# CURRENT-RTL SIGNAL/PG GEOMETRY PROTOTYPE ONLY. NOT A SIGNED VIEW.
# Fresh846-port contract; PG is the unchanged kit pdn.tcl grid, not routed evidence.
VERSION 5.8 ;
BUSBITCHARS "[]" ;
DIVIDERCHAR "/" ;
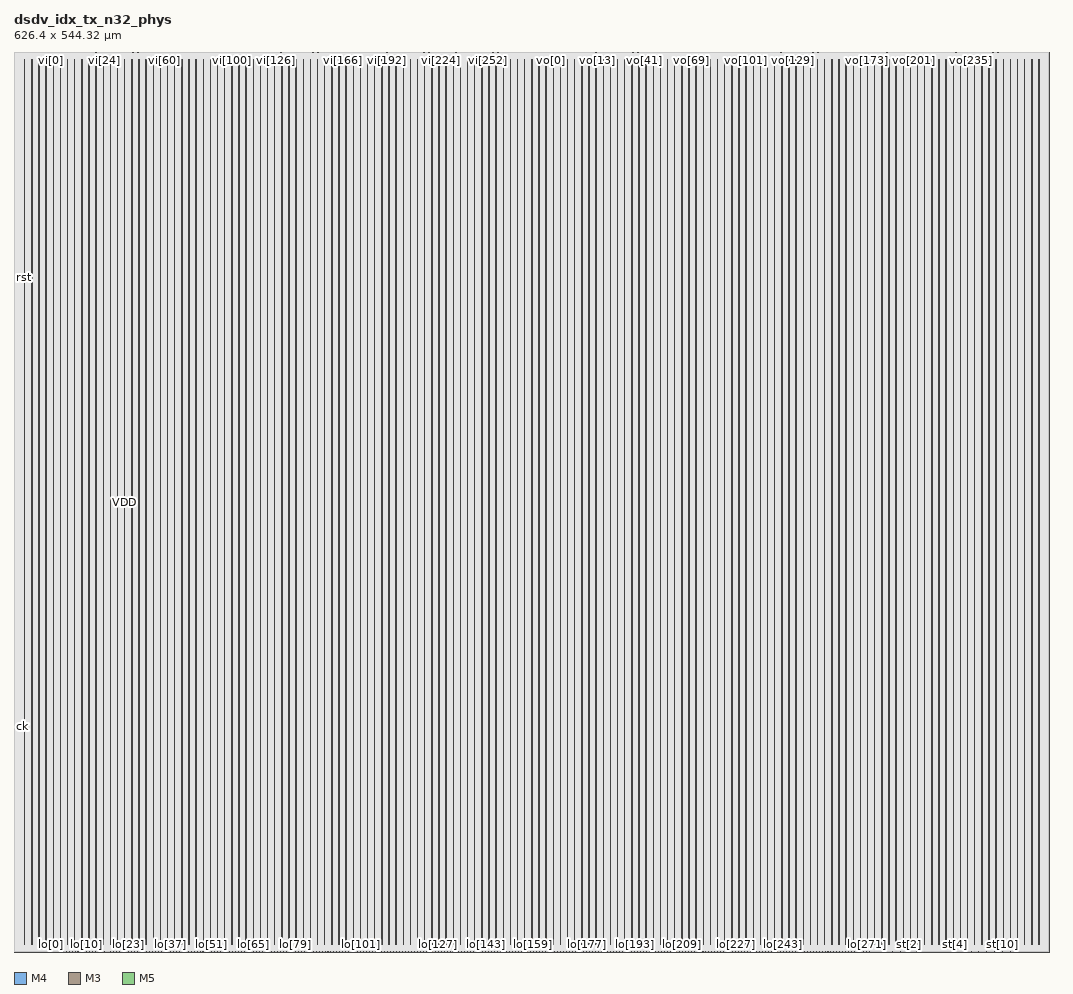
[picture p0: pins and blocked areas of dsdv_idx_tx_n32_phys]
MACRO dsdv_idx_tx_n32_phys
 CLASS BLOCK ;
 ORIGIN 0 0 ;
 SIZE 626.4 BY 544.32 ;
 SYMMETRY X Y ;
 PIN ck
  DIRECTION INPUT ;
  USE SIGNAL ;
  PORT
   LAYER M4 ;
   RECT 0.000000 136.560000 0.084000 136.584000 ;
  END
 END ck
 PIN lo[0]
  DIRECTION OUTPUT ;
  USE SIGNAL ;
  PORT
   LAYER M3 ;
   RECT 22.500000 0.000000 22.518000 0.038000 ;
  END
 END lo[0]
 PIN lo[97]
  DIRECTION OUTPUT ;
  USE SIGNAL ;
  PORT
   LAYER M3 ;
   RECT 202.500000 0.000000 202.518000 0.038000 ;
  END
 END lo[97]
 PIN lo[98]
  DIRECTION OUTPUT ;
  USE SIGNAL ;
  PORT
   LAYER M5 ;
   RECT 204.288000 0.000000 204.312000 0.084000 ;
  END
 END lo[98]
 PIN lo[99]
  DIRECTION OUTPUT ;
  USE SIGNAL ;
  PORT
   LAYER M3 ;
   RECT 206.100000 0.000000 206.118000 0.038000 ;
  END
 END lo[99]
 PIN lo[100]
  DIRECTION OUTPUT ;
  USE SIGNAL ;
  PORT
   LAYER M5 ;
   RECT 207.888000 0.000000 207.912000 0.084000 ;
  END
 END lo[100]
 PIN lo[101]
  DIRECTION OUTPUT ;
  USE SIGNAL ;
  PORT
   LAYER M3 ;
   RECT 209.700000 0.000000 209.718000 0.038000 ;
  END
 END lo[101]
 PIN lo[102]
  DIRECTION OUTPUT ;
  USE SIGNAL ;
  PORT
   LAYER M5 ;
   RECT 211.488000 0.000000 211.512000 0.084000 ;
  END
 END lo[102]
 PIN lo[103]
  DIRECTION OUTPUT ;
  USE SIGNAL ;
  PORT
   LAYER M3 ;
   RECT 213.300000 0.000000 213.318000 0.038000 ;
  END
 END lo[103]
 PIN lo[104]
  DIRECTION OUTPUT ;
  USE SIGNAL ;
  PORT
   LAYER M5 ;
   RECT 215.088000 0.000000 215.112000 0.084000 ;
  END
 END lo[104]
 PIN lo[105]
  DIRECTION OUTPUT ;
  USE SIGNAL ;
  PORT
   LAYER M3 ;
   RECT 216.900000 0.000000 216.918000 0.038000 ;
  END
 END lo[105]
 PIN lo[106]
  DIRECTION OUTPUT ;
  USE SIGNAL ;
  PORT
   LAYER M5 ;
   RECT 218.688000 0.000000 218.712000 0.084000 ;
  END
 END lo[106]
 PIN lo[8]
  DIRECTION OUTPUT ;
  USE SIGNAL ;
  PORT
   LAYER M3 ;
   RECT 40.500000 0.000000 40.518000 0.038000 ;
  END
 END lo[8]
 PIN lo[107]
  DIRECTION OUTPUT ;
  USE SIGNAL ;
  PORT
   LAYER M3 ;
   RECT 220.500000 0.000000 220.518000 0.038000 ;
  END
 END lo[107]
 PIN lo[108]
  DIRECTION OUTPUT ;
  USE SIGNAL ;
  PORT
   LAYER M5 ;
   RECT 222.288000 0.000000 222.312000 0.084000 ;
  END
 END lo[108]
 PIN lo[109]
  DIRECTION OUTPUT ;
  USE SIGNAL ;
  PORT
   LAYER M3 ;
   RECT 224.100000 0.000000 224.118000 0.038000 ;
  END
 END lo[109]
 PIN lo[110]
  DIRECTION OUTPUT ;
  USE SIGNAL ;
  PORT
   LAYER M5 ;
   RECT 225.888000 0.000000 225.912000 0.084000 ;
  END
 END lo[110]
 PIN lo[111]
  DIRECTION OUTPUT ;
  USE SIGNAL ;
  PORT
   LAYER M3 ;
   RECT 227.700000 0.000000 227.718000 0.038000 ;
  END
 END lo[111]
 PIN lo[112]
  DIRECTION OUTPUT ;
  USE SIGNAL ;
  PORT
   LAYER M5 ;
   RECT 229.488000 0.000000 229.512000 0.084000 ;
  END
 END lo[112]
 PIN lo[113]
  DIRECTION OUTPUT ;
  USE SIGNAL ;
  PORT
   LAYER M3 ;
   RECT 231.300000 0.000000 231.318000 0.038000 ;
  END
 END lo[113]
 PIN lo[114]
  DIRECTION OUTPUT ;
  USE SIGNAL ;
  PORT
   LAYER M5 ;
   RECT 233.088000 0.000000 233.112000 0.084000 ;
  END
 END lo[114]
 PIN lo[115]
  DIRECTION OUTPUT ;
  USE SIGNAL ;
  PORT
   LAYER M3 ;
   RECT 234.900000 0.000000 234.918000 0.038000 ;
  END
 END lo[115]
 PIN lo[116]
  DIRECTION OUTPUT ;
  USE SIGNAL ;
  PORT
   LAYER M5 ;
   RECT 236.688000 0.000000 236.712000 0.084000 ;
  END
 END lo[116]
 PIN lo[9]
  DIRECTION OUTPUT ;
  USE SIGNAL ;
  PORT
   LAYER M5 ;
   RECT 42.288000 0.000000 42.312000 0.084000 ;
  END
 END lo[9]
 PIN lo[117]
  DIRECTION OUTPUT ;
  USE SIGNAL ;
  PORT
   LAYER M3 ;
   RECT 238.500000 0.000000 238.518000 0.038000 ;
  END
 END lo[117]
 PIN lo[118]
  DIRECTION OUTPUT ;
  USE SIGNAL ;
  PORT
   LAYER M5 ;
   RECT 240.288000 0.000000 240.312000 0.084000 ;
  END
 END lo[118]
 PIN lo[119]
  DIRECTION OUTPUT ;
  USE SIGNAL ;
  PORT
   LAYER M3 ;
   RECT 242.100000 0.000000 242.118000 0.038000 ;
  END
 END lo[119]
 PIN lo[120]
  DIRECTION OUTPUT ;
  USE SIGNAL ;
  PORT
   LAYER M5 ;
   RECT 243.888000 0.000000 243.912000 0.084000 ;
  END
 END lo[120]
 PIN lo[121]
  DIRECTION OUTPUT ;
  USE SIGNAL ;
  PORT
   LAYER M3 ;
   RECT 245.700000 0.000000 245.718000 0.038000 ;
  END
 END lo[121]
 PIN lo[122]
  DIRECTION OUTPUT ;
  USE SIGNAL ;
  PORT
   LAYER M5 ;
   RECT 247.488000 0.000000 247.512000 0.084000 ;
  END
 END lo[122]
 PIN lo[123]
  DIRECTION OUTPUT ;
  USE SIGNAL ;
  PORT
   LAYER M3 ;
   RECT 249.300000 0.000000 249.318000 0.038000 ;
  END
 END lo[123]
 PIN lo[124]
  DIRECTION OUTPUT ;
  USE SIGNAL ;
  PORT
   LAYER M5 ;
   RECT 251.088000 0.000000 251.112000 0.084000 ;
  END
 END lo[124]
 PIN lo[125]
  DIRECTION OUTPUT ;
  USE SIGNAL ;
  PORT
   LAYER M3 ;
   RECT 252.900000 0.000000 252.918000 0.038000 ;
  END
 END lo[125]
 PIN lo[126]
  DIRECTION OUTPUT ;
  USE SIGNAL ;
  PORT
   LAYER M5 ;
   RECT 254.688000 0.000000 254.712000 0.084000 ;
  END
 END lo[126]
 PIN lo[10]
  DIRECTION OUTPUT ;
  USE SIGNAL ;
  PORT
   LAYER M3 ;
   RECT 44.100000 0.000000 44.118000 0.038000 ;
  END
 END lo[10]
 PIN lo[127]
  DIRECTION OUTPUT ;
  USE SIGNAL ;
  PORT
   LAYER M3 ;
   RECT 256.500000 0.000000 256.518000 0.038000 ;
  END
 END lo[127]
 PIN lo[128]
  DIRECTION OUTPUT ;
  USE SIGNAL ;
  PORT
   LAYER M5 ;
   RECT 258.288000 0.000000 258.312000 0.084000 ;
  END
 END lo[128]
 PIN lo[129]
  DIRECTION OUTPUT ;
  USE SIGNAL ;
  PORT
   LAYER M3 ;
   RECT 260.100000 0.000000 260.118000 0.038000 ;
  END
 END lo[129]
 PIN lo[130]
  DIRECTION OUTPUT ;
  USE SIGNAL ;
  PORT
   LAYER M5 ;
   RECT 261.888000 0.000000 261.912000 0.084000 ;
  END
 END lo[130]
 PIN lo[131]
  DIRECTION OUTPUT ;
  USE SIGNAL ;
  PORT
   LAYER M3 ;
   RECT 263.700000 0.000000 263.718000 0.038000 ;
  END
 END lo[131]
 PIN lo[132]
  DIRECTION OUTPUT ;
  USE SIGNAL ;
  PORT
   LAYER M5 ;
   RECT 265.488000 0.000000 265.512000 0.084000 ;
  END
 END lo[132]
 PIN lo[133]
  DIRECTION OUTPUT ;
  USE SIGNAL ;
  PORT
   LAYER M3 ;
   RECT 267.300000 0.000000 267.318000 0.038000 ;
  END
 END lo[133]
 PIN lo[134]
  DIRECTION OUTPUT ;
  USE SIGNAL ;
  PORT
   LAYER M5 ;
   RECT 269.088000 0.000000 269.112000 0.084000 ;
  END
 END lo[134]
 PIN lo[135]
  DIRECTION OUTPUT ;
  USE SIGNAL ;
  PORT
   LAYER M3 ;
   RECT 270.900000 0.000000 270.918000 0.038000 ;
  END
 END lo[135]
 PIN lo[136]
  DIRECTION OUTPUT ;
  USE SIGNAL ;
  PORT
   LAYER M5 ;
   RECT 272.688000 0.000000 272.712000 0.084000 ;
  END
 END lo[136]
 PIN lo[11]
  DIRECTION OUTPUT ;
  USE SIGNAL ;
  PORT
   LAYER M5 ;
   RECT 45.888000 0.000000 45.912000 0.084000 ;
  END
 END lo[11]
 PIN lo[137]
  DIRECTION OUTPUT ;
  USE SIGNAL ;
  PORT
   LAYER M3 ;
   RECT 274.500000 0.000000 274.518000 0.038000 ;
  END
 END lo[137]
 PIN lo[138]
  DIRECTION OUTPUT ;
  USE SIGNAL ;
  PORT
   LAYER M5 ;
   RECT 276.288000 0.000000 276.312000 0.084000 ;
  END
 END lo[138]
 PIN lo[139]
  DIRECTION OUTPUT ;
  USE SIGNAL ;
  PORT
   LAYER M3 ;
   RECT 278.100000 0.000000 278.118000 0.038000 ;
  END
 END lo[139]
 PIN lo[140]
  DIRECTION OUTPUT ;
  USE SIGNAL ;
  PORT
   LAYER M5 ;
   RECT 279.888000 0.000000 279.912000 0.084000 ;
  END
 END lo[140]
 PIN lo[141]
  DIRECTION OUTPUT ;
  USE SIGNAL ;
  PORT
   LAYER M3 ;
   RECT 281.700000 0.000000 281.718000 0.038000 ;
  END
 END lo[141]
 PIN lo[142]
  DIRECTION OUTPUT ;
  USE SIGNAL ;
  PORT
   LAYER M5 ;
   RECT 283.488000 0.000000 283.512000 0.084000 ;
  END
 END lo[142]
 PIN lo[143]
  DIRECTION OUTPUT ;
  USE SIGNAL ;
  PORT
   LAYER M3 ;
   RECT 285.300000 0.000000 285.318000 0.038000 ;
  END
 END lo[143]
 PIN lo[144]
  DIRECTION OUTPUT ;
  USE SIGNAL ;
  PORT
   LAYER M5 ;
   RECT 287.088000 0.000000 287.112000 0.084000 ;
  END
 END lo[144]
 PIN lo[145]
  DIRECTION OUTPUT ;
  USE SIGNAL ;
  PORT
   LAYER M3 ;
   RECT 288.900000 0.000000 288.918000 0.038000 ;
  END
 END lo[145]
 PIN lo[146]
  DIRECTION OUTPUT ;
  USE SIGNAL ;
  PORT
   LAYER M5 ;
   RECT 290.688000 0.000000 290.712000 0.084000 ;
  END
 END lo[146]
 PIN lo[12]
  DIRECTION OUTPUT ;
  USE SIGNAL ;
  PORT
   LAYER M3 ;
   RECT 47.700000 0.000000 47.718000 0.038000 ;
  END
 END lo[12]
 PIN lo[147]
  DIRECTION OUTPUT ;
  USE SIGNAL ;
  PORT
   LAYER M3 ;
   RECT 292.500000 0.000000 292.518000 0.038000 ;
  END
 END lo[147]
 PIN lo[148]
  DIRECTION OUTPUT ;
  USE SIGNAL ;
  PORT
   LAYER M5 ;
   RECT 294.288000 0.000000 294.312000 0.084000 ;
  END
 END lo[148]
 PIN lo[149]
  DIRECTION OUTPUT ;
  USE SIGNAL ;
  PORT
   LAYER M3 ;
   RECT 296.100000 0.000000 296.118000 0.038000 ;
  END
 END lo[149]
 PIN lo[150]
  DIRECTION OUTPUT ;
  USE SIGNAL ;
  PORT
   LAYER M5 ;
   RECT 297.888000 0.000000 297.912000 0.084000 ;
  END
 END lo[150]
 PIN lo[151]
  DIRECTION OUTPUT ;
  USE SIGNAL ;
  PORT
   LAYER M3 ;
   RECT 299.736000 0.000000 299.754000 0.038000 ;
  END
 END lo[151]
 PIN lo[152]
  DIRECTION OUTPUT ;
  USE SIGNAL ;
  PORT
   LAYER M5 ;
   RECT 301.488000 0.000000 301.512000 0.084000 ;
  END
 END lo[152]
 PIN lo[153]
  DIRECTION OUTPUT ;
  USE SIGNAL ;
  PORT
   LAYER M3 ;
   RECT 303.300000 0.000000 303.318000 0.038000 ;
  END
 END lo[153]
 PIN lo[154]
  DIRECTION OUTPUT ;
  USE SIGNAL ;
  PORT
   LAYER M5 ;
   RECT 305.088000 0.000000 305.112000 0.084000 ;
  END
 END lo[154]
 PIN lo[155]
  DIRECTION OUTPUT ;
  USE SIGNAL ;
  PORT
   LAYER M3 ;
   RECT 306.900000 0.000000 306.918000 0.038000 ;
  END
 END lo[155]
 PIN lo[156]
  DIRECTION OUTPUT ;
  USE SIGNAL ;
  PORT
   LAYER M5 ;
   RECT 308.688000 0.000000 308.712000 0.084000 ;
  END
 END lo[156]
 PIN lo[13]
  DIRECTION OUTPUT ;
  USE SIGNAL ;
  PORT
   LAYER M5 ;
   RECT 49.488000 0.000000 49.512000 0.084000 ;
  END
 END lo[13]
 PIN lo[157]
  DIRECTION OUTPUT ;
  USE SIGNAL ;
  PORT
   LAYER M3 ;
   RECT 310.500000 0.000000 310.518000 0.038000 ;
  END
 END lo[157]
 PIN lo[158]
  DIRECTION OUTPUT ;
  USE SIGNAL ;
  PORT
   LAYER M5 ;
   RECT 312.288000 0.000000 312.312000 0.084000 ;
  END
 END lo[158]
 PIN lo[159]
  DIRECTION OUTPUT ;
  USE SIGNAL ;
  PORT
   LAYER M3 ;
   RECT 314.100000 0.000000 314.118000 0.038000 ;
  END
 END lo[159]
 PIN lo[160]
  DIRECTION OUTPUT ;
  USE SIGNAL ;
  PORT
   LAYER M5 ;
   RECT 315.888000 0.000000 315.912000 0.084000 ;
  END
 END lo[160]
 PIN lo[161]
  DIRECTION OUTPUT ;
  USE SIGNAL ;
  PORT
   LAYER M3 ;
   RECT 317.700000 0.000000 317.718000 0.038000 ;
  END
 END lo[161]
 PIN lo[162]
  DIRECTION OUTPUT ;
  USE SIGNAL ;
  PORT
   LAYER M5 ;
   RECT 319.488000 0.000000 319.512000 0.084000 ;
  END
 END lo[162]
 PIN lo[163]
  DIRECTION OUTPUT ;
  USE SIGNAL ;
  PORT
   LAYER M3 ;
   RECT 321.300000 0.000000 321.318000 0.038000 ;
  END
 END lo[163]
 PIN lo[164]
  DIRECTION OUTPUT ;
  USE SIGNAL ;
  PORT
   LAYER M5 ;
   RECT 323.088000 0.000000 323.112000 0.084000 ;
  END
 END lo[164]
 PIN lo[165]
  DIRECTION OUTPUT ;
  USE SIGNAL ;
  PORT
   LAYER M3 ;
   RECT 324.900000 0.000000 324.918000 0.038000 ;
  END
 END lo[165]
 PIN lo[166]
  DIRECTION OUTPUT ;
  USE SIGNAL ;
  PORT
   LAYER M5 ;
   RECT 326.688000 0.000000 326.712000 0.084000 ;
  END
 END lo[166]
 PIN lo[14]
  DIRECTION OUTPUT ;
  USE SIGNAL ;
  PORT
   LAYER M3 ;
   RECT 51.300000 0.000000 51.318000 0.038000 ;
  END
 END lo[14]
 PIN lo[167]
  DIRECTION OUTPUT ;
  USE SIGNAL ;
  PORT
   LAYER M3 ;
   RECT 328.500000 0.000000 328.518000 0.038000 ;
  END
 END lo[167]
 PIN lo[168]
  DIRECTION OUTPUT ;
  USE SIGNAL ;
  PORT
   LAYER M5 ;
   RECT 330.288000 0.000000 330.312000 0.084000 ;
  END
 END lo[168]
 PIN lo[169]
  DIRECTION OUTPUT ;
  USE SIGNAL ;
  PORT
   LAYER M3 ;
   RECT 332.100000 0.000000 332.118000 0.038000 ;
  END
 END lo[169]
 PIN lo[170]
  DIRECTION OUTPUT ;
  USE SIGNAL ;
  PORT
   LAYER M5 ;
   RECT 333.888000 0.000000 333.912000 0.084000 ;
  END
 END lo[170]
 PIN lo[171]
  DIRECTION OUTPUT ;
  USE SIGNAL ;
  PORT
   LAYER M3 ;
   RECT 335.700000 0.000000 335.718000 0.038000 ;
  END
 END lo[171]
 PIN lo[172]
  DIRECTION OUTPUT ;
  USE SIGNAL ;
  PORT
   LAYER M5 ;
   RECT 337.488000 0.000000 337.512000 0.084000 ;
  END
 END lo[172]
 PIN lo[173]
  DIRECTION OUTPUT ;
  USE SIGNAL ;
  PORT
   LAYER M3 ;
   RECT 339.300000 0.000000 339.318000 0.038000 ;
  END
 END lo[173]
 PIN lo[174]
  DIRECTION OUTPUT ;
  USE SIGNAL ;
  PORT
   LAYER M5 ;
   RECT 341.088000 0.000000 341.112000 0.084000 ;
  END
 END lo[174]
 PIN lo[175]
  DIRECTION OUTPUT ;
  USE SIGNAL ;
  PORT
   LAYER M3 ;
   RECT 342.900000 0.000000 342.918000 0.038000 ;
  END
 END lo[175]
 PIN lo[176]
  DIRECTION OUTPUT ;
  USE SIGNAL ;
  PORT
   LAYER M5 ;
   RECT 344.688000 0.000000 344.712000 0.084000 ;
  END
 END lo[176]
 PIN lo[15]
  DIRECTION OUTPUT ;
  USE SIGNAL ;
  PORT
   LAYER M5 ;
   RECT 53.088000 0.000000 53.112000 0.084000 ;
  END
 END lo[15]
 PIN lo[177]
  DIRECTION OUTPUT ;
  USE SIGNAL ;
  PORT
   LAYER M3 ;
   RECT 346.500000 0.000000 346.518000 0.038000 ;
  END
 END lo[177]
 PIN lo[178]
  DIRECTION OUTPUT ;
  USE SIGNAL ;
  PORT
   LAYER M5 ;
   RECT 348.288000 0.000000 348.312000 0.084000 ;
  END
 END lo[178]
 PIN lo[179]
  DIRECTION OUTPUT ;
  USE SIGNAL ;
  PORT
   LAYER M3 ;
   RECT 350.100000 0.000000 350.118000 0.038000 ;
  END
 END lo[179]
 PIN lo[180]
  DIRECTION OUTPUT ;
  USE SIGNAL ;
  PORT
   LAYER M5 ;
   RECT 351.888000 0.000000 351.912000 0.084000 ;
  END
 END lo[180]
 PIN lo[181]
  DIRECTION OUTPUT ;
  USE SIGNAL ;
  PORT
   LAYER M3 ;
   RECT 353.700000 0.000000 353.718000 0.038000 ;
  END
 END lo[181]
 PIN lo[182]
  DIRECTION OUTPUT ;
  USE SIGNAL ;
  PORT
   LAYER M5 ;
   RECT 355.488000 0.000000 355.512000 0.084000 ;
  END
 END lo[182]
 PIN lo[183]
  DIRECTION OUTPUT ;
  USE SIGNAL ;
  PORT
   LAYER M3 ;
   RECT 357.300000 0.000000 357.318000 0.038000 ;
  END
 END lo[183]
 PIN lo[184]
  DIRECTION OUTPUT ;
  USE SIGNAL ;
  PORT
   LAYER M5 ;
   RECT 359.088000 0.000000 359.112000 0.084000 ;
  END
 END lo[184]
 PIN lo[185]
  DIRECTION OUTPUT ;
  USE SIGNAL ;
  PORT
   LAYER M3 ;
   RECT 360.900000 0.000000 360.918000 0.038000 ;
  END
 END lo[185]
 PIN lo[186]
  DIRECTION OUTPUT ;
  USE SIGNAL ;
  PORT
   LAYER M5 ;
   RECT 362.688000 0.000000 362.712000 0.084000 ;
  END
 END lo[186]
 PIN lo[16]
  DIRECTION OUTPUT ;
  USE SIGNAL ;
  PORT
   LAYER M3 ;
   RECT 54.900000 0.000000 54.918000 0.038000 ;
  END
 END lo[16]
 PIN lo[187]
  DIRECTION OUTPUT ;
  USE SIGNAL ;
  PORT
   LAYER M3 ;
   RECT 364.500000 0.000000 364.518000 0.038000 ;
  END
 END lo[187]
 PIN lo[188]
  DIRECTION OUTPUT ;
  USE SIGNAL ;
  PORT
   LAYER M5 ;
   RECT 366.288000 0.000000 366.312000 0.084000 ;
  END
 END lo[188]
 PIN lo[189]
  DIRECTION OUTPUT ;
  USE SIGNAL ;
  PORT
   LAYER M3 ;
   RECT 368.100000 0.000000 368.118000 0.038000 ;
  END
 END lo[189]
 PIN lo[190]
  DIRECTION OUTPUT ;
  USE SIGNAL ;
  PORT
   LAYER M5 ;
   RECT 369.888000 0.000000 369.912000 0.084000 ;
  END
 END lo[190]
 PIN lo[191]
  DIRECTION OUTPUT ;
  USE SIGNAL ;
  PORT
   LAYER M3 ;
   RECT 371.700000 0.000000 371.718000 0.038000 ;
  END
 END lo[191]
 PIN lo[192]
  DIRECTION OUTPUT ;
  USE SIGNAL ;
  PORT
   LAYER M5 ;
   RECT 373.488000 0.000000 373.512000 0.084000 ;
  END
 END lo[192]
 PIN lo[193]
  DIRECTION OUTPUT ;
  USE SIGNAL ;
  PORT
   LAYER M3 ;
   RECT 375.300000 0.000000 375.318000 0.038000 ;
  END
 END lo[193]
 PIN lo[194]
  DIRECTION OUTPUT ;
  USE SIGNAL ;
  PORT
   LAYER M5 ;
   RECT 377.088000 0.000000 377.112000 0.084000 ;
  END
 END lo[194]
 PIN lo[195]
  DIRECTION OUTPUT ;
  USE SIGNAL ;
  PORT
   LAYER M3 ;
   RECT 378.900000 0.000000 378.918000 0.038000 ;
  END
 END lo[195]
 PIN lo[196]
  DIRECTION OUTPUT ;
  USE SIGNAL ;
  PORT
   LAYER M5 ;
   RECT 380.688000 0.000000 380.712000 0.084000 ;
  END
 END lo[196]
 PIN lo[197]
  DIRECTION OUTPUT ;
  USE SIGNAL ;
  PORT
   LAYER M3 ;
   RECT 382.500000 0.000000 382.518000 0.038000 ;
  END
 END lo[197]
 PIN lo[198]
  DIRECTION OUTPUT ;
  USE SIGNAL ;
  PORT
   LAYER M5 ;
   RECT 384.288000 0.000000 384.312000 0.084000 ;
  END
 END lo[198]
 PIN lo[199]
  DIRECTION OUTPUT ;
  USE SIGNAL ;
  PORT
   LAYER M3 ;
   RECT 386.100000 0.000000 386.118000 0.038000 ;
  END
 END lo[199]
 PIN lo[200]
  DIRECTION OUTPUT ;
  USE SIGNAL ;
  PORT
   LAYER M5 ;
   RECT 387.888000 0.000000 387.912000 0.084000 ;
  END
 END lo[200]
 PIN lo[201]
  DIRECTION OUTPUT ;
  USE SIGNAL ;
  PORT
   LAYER M3 ;
   RECT 389.700000 0.000000 389.718000 0.038000 ;
  END
 END lo[201]
 PIN lo[202]
  DIRECTION OUTPUT ;
  USE SIGNAL ;
  PORT
   LAYER M5 ;
   RECT 391.488000 0.000000 391.512000 0.084000 ;
  END
 END lo[202]
 PIN lo[203]
  DIRECTION OUTPUT ;
  USE SIGNAL ;
  PORT
   LAYER M3 ;
   RECT 393.300000 0.000000 393.318000 0.038000 ;
  END
 END lo[203]
 PIN lo[204]
  DIRECTION OUTPUT ;
  USE SIGNAL ;
  PORT
   LAYER M5 ;
   RECT 395.088000 0.000000 395.112000 0.084000 ;
  END
 END lo[204]
 PIN lo[205]
  DIRECTION OUTPUT ;
  USE SIGNAL ;
  PORT
   LAYER M3 ;
   RECT 396.900000 0.000000 396.918000 0.038000 ;
  END
 END lo[205]
 PIN lo[206]
  DIRECTION OUTPUT ;
  USE SIGNAL ;
  PORT
   LAYER M5 ;
   RECT 398.688000 0.000000 398.712000 0.084000 ;
  END
 END lo[206]
 PIN lo[17]
  DIRECTION OUTPUT ;
  USE SIGNAL ;
  PORT
   LAYER M3 ;
   RECT 58.500000 0.000000 58.518000 0.038000 ;
  END
 END lo[17]
 PIN lo[207]
  DIRECTION OUTPUT ;
  USE SIGNAL ;
  PORT
   LAYER M3 ;
   RECT 400.500000 0.000000 400.518000 0.038000 ;
  END
 END lo[207]
 PIN lo[208]
  DIRECTION OUTPUT ;
  USE SIGNAL ;
  PORT
   LAYER M5 ;
   RECT 402.288000 0.000000 402.312000 0.084000 ;
  END
 END lo[208]
 PIN lo[209]
  DIRECTION OUTPUT ;
  USE SIGNAL ;
  PORT
   LAYER M3 ;
   RECT 404.100000 0.000000 404.118000 0.038000 ;
  END
 END lo[209]
 PIN lo[210]
  DIRECTION OUTPUT ;
  USE SIGNAL ;
  PORT
   LAYER M5 ;
   RECT 405.888000 0.000000 405.912000 0.084000 ;
  END
 END lo[210]
 PIN lo[211]
  DIRECTION OUTPUT ;
  USE SIGNAL ;
  PORT
   LAYER M3 ;
   RECT 407.700000 0.000000 407.718000 0.038000 ;
  END
 END lo[211]
 PIN lo[212]
  DIRECTION OUTPUT ;
  USE SIGNAL ;
  PORT
   LAYER M5 ;
   RECT 409.488000 0.000000 409.512000 0.084000 ;
  END
 END lo[212]
 PIN lo[213]
  DIRECTION OUTPUT ;
  USE SIGNAL ;
  PORT
   LAYER M3 ;
   RECT 411.300000 0.000000 411.318000 0.038000 ;
  END
 END lo[213]
 PIN lo[214]
  DIRECTION OUTPUT ;
  USE SIGNAL ;
  PORT
   LAYER M5 ;
   RECT 413.088000 0.000000 413.112000 0.084000 ;
  END
 END lo[214]
 PIN lo[215]
  DIRECTION OUTPUT ;
  USE SIGNAL ;
  PORT
   LAYER M3 ;
   RECT 414.900000 0.000000 414.918000 0.038000 ;
  END
 END lo[215]
 PIN lo[216]
  DIRECTION OUTPUT ;
  USE SIGNAL ;
  PORT
   LAYER M5 ;
   RECT 416.688000 0.000000 416.712000 0.084000 ;
  END
 END lo[216]
 PIN lo[18]
  DIRECTION OUTPUT ;
  USE SIGNAL ;
  PORT
   LAYER M5 ;
   RECT 60.288000 0.000000 60.312000 0.084000 ;
  END
 END lo[18]
 PIN lo[217]
  DIRECTION OUTPUT ;
  USE SIGNAL ;
  PORT
   LAYER M3 ;
   RECT 418.500000 0.000000 418.518000 0.038000 ;
  END
 END lo[217]
 PIN lo[218]
  DIRECTION OUTPUT ;
  USE SIGNAL ;
  PORT
   LAYER M5 ;
   RECT 420.288000 0.000000 420.312000 0.084000 ;
  END
 END lo[218]
 PIN lo[219]
  DIRECTION OUTPUT ;
  USE SIGNAL ;
  PORT
   LAYER M3 ;
   RECT 422.100000 0.000000 422.118000 0.038000 ;
  END
 END lo[219]
 PIN lo[220]
  DIRECTION OUTPUT ;
  USE SIGNAL ;
  PORT
   LAYER M5 ;
   RECT 423.888000 0.000000 423.912000 0.084000 ;
  END
 END lo[220]
 PIN lo[221]
  DIRECTION OUTPUT ;
  USE SIGNAL ;
  PORT
   LAYER M3 ;
   RECT 425.700000 0.000000 425.718000 0.038000 ;
  END
 END lo[221]
 PIN lo[222]
  DIRECTION OUTPUT ;
  USE SIGNAL ;
  PORT
   LAYER M5 ;
   RECT 427.488000 0.000000 427.512000 0.084000 ;
  END
 END lo[222]
 PIN lo[223]
  DIRECTION OUTPUT ;
  USE SIGNAL ;
  PORT
   LAYER M3 ;
   RECT 429.300000 0.000000 429.318000 0.038000 ;
  END
 END lo[223]
 PIN lo[224]
  DIRECTION OUTPUT ;
  USE SIGNAL ;
  PORT
   LAYER M5 ;
   RECT 431.088000 0.000000 431.112000 0.084000 ;
  END
 END lo[224]
 PIN lo[225]
  DIRECTION OUTPUT ;
  USE SIGNAL ;
  PORT
   LAYER M3 ;
   RECT 432.900000 0.000000 432.918000 0.038000 ;
  END
 END lo[225]
 PIN lo[226]
  DIRECTION OUTPUT ;
  USE SIGNAL ;
  PORT
   LAYER M5 ;
   RECT 434.688000 0.000000 434.712000 0.084000 ;
  END
 END lo[226]
 PIN lo[19]
  DIRECTION OUTPUT ;
  USE SIGNAL ;
  PORT
   LAYER M3 ;
   RECT 62.100000 0.000000 62.118000 0.038000 ;
  END
 END lo[19]
 PIN lo[227]
  DIRECTION OUTPUT ;
  USE SIGNAL ;
  PORT
   LAYER M3 ;
   RECT 436.500000 0.000000 436.518000 0.038000 ;
  END
 END lo[227]
 PIN lo[228]
  DIRECTION OUTPUT ;
  USE SIGNAL ;
  PORT
   LAYER M5 ;
   RECT 438.288000 0.000000 438.312000 0.084000 ;
  END
 END lo[228]
 PIN lo[229]
  DIRECTION OUTPUT ;
  USE SIGNAL ;
  PORT
   LAYER M3 ;
   RECT 440.100000 0.000000 440.118000 0.038000 ;
  END
 END lo[229]
 PIN lo[230]
  DIRECTION OUTPUT ;
  USE SIGNAL ;
  PORT
   LAYER M5 ;
   RECT 441.888000 0.000000 441.912000 0.084000 ;
  END
 END lo[230]
 PIN lo[231]
  DIRECTION OUTPUT ;
  USE SIGNAL ;
  PORT
   LAYER M3 ;
   RECT 443.700000 0.000000 443.718000 0.038000 ;
  END
 END lo[231]
 PIN lo[232]
  DIRECTION OUTPUT ;
  USE SIGNAL ;
  PORT
   LAYER M5 ;
   RECT 445.488000 0.000000 445.512000 0.084000 ;
  END
 END lo[232]
 PIN lo[233]
  DIRECTION OUTPUT ;
  USE SIGNAL ;
  PORT
   LAYER M3 ;
   RECT 447.300000 0.000000 447.318000 0.038000 ;
  END
 END lo[233]
 PIN lo[234]
  DIRECTION OUTPUT ;
  USE SIGNAL ;
  PORT
   LAYER M5 ;
   RECT 449.088000 0.000000 449.112000 0.084000 ;
  END
 END lo[234]
 PIN lo[235]
  DIRECTION OUTPUT ;
  USE SIGNAL ;
  PORT
   LAYER M3 ;
   RECT 450.900000 0.000000 450.918000 0.038000 ;
  END
 END lo[235]
 PIN lo[236]
  DIRECTION OUTPUT ;
  USE SIGNAL ;
  PORT
   LAYER M5 ;
   RECT 452.688000 0.000000 452.712000 0.084000 ;
  END
 END lo[236]
 PIN lo[20]
  DIRECTION OUTPUT ;
  USE SIGNAL ;
  PORT
   LAYER M5 ;
   RECT 63.888000 0.000000 63.912000 0.084000 ;
  END
 END lo[20]
 PIN lo[237]
  DIRECTION OUTPUT ;
  USE SIGNAL ;
  PORT
   LAYER M3 ;
   RECT 454.500000 0.000000 454.518000 0.038000 ;
  END
 END lo[237]
 PIN lo[238]
  DIRECTION OUTPUT ;
  USE SIGNAL ;
  PORT
   LAYER M5 ;
   RECT 456.288000 0.000000 456.312000 0.084000 ;
  END
 END lo[238]
 PIN lo[239]
  DIRECTION OUTPUT ;
  USE SIGNAL ;
  PORT
   LAYER M3 ;
   RECT 458.100000 0.000000 458.118000 0.038000 ;
  END
 END lo[239]
 PIN lo[240]
  DIRECTION OUTPUT ;
  USE SIGNAL ;
  PORT
   LAYER M5 ;
   RECT 459.888000 0.000000 459.912000 0.084000 ;
  END
 END lo[240]
 PIN lo[241]
  DIRECTION OUTPUT ;
  USE SIGNAL ;
  PORT
   LAYER M3 ;
   RECT 461.700000 0.000000 461.718000 0.038000 ;
  END
 END lo[241]
 PIN lo[242]
  DIRECTION OUTPUT ;
  USE SIGNAL ;
  PORT
   LAYER M5 ;
   RECT 463.488000 0.000000 463.512000 0.084000 ;
  END
 END lo[242]
 PIN lo[243]
  DIRECTION OUTPUT ;
  USE SIGNAL ;
  PORT
   LAYER M3 ;
   RECT 465.300000 0.000000 465.318000 0.038000 ;
  END
 END lo[243]
 PIN lo[244]
  DIRECTION OUTPUT ;
  USE SIGNAL ;
  PORT
   LAYER M5 ;
   RECT 467.088000 0.000000 467.112000 0.084000 ;
  END
 END lo[244]
 PIN lo[245]
  DIRECTION OUTPUT ;
  USE SIGNAL ;
  PORT
   LAYER M3 ;
   RECT 468.900000 0.000000 468.918000 0.038000 ;
  END
 END lo[245]
 PIN lo[246]
  DIRECTION OUTPUT ;
  USE SIGNAL ;
  PORT
   LAYER M5 ;
   RECT 470.688000 0.000000 470.712000 0.084000 ;
  END
 END lo[246]
 PIN lo[21]
  DIRECTION OUTPUT ;
  USE SIGNAL ;
  PORT
   LAYER M3 ;
   RECT 65.700000 0.000000 65.718000 0.038000 ;
  END
 END lo[21]
 PIN lo[247]
  DIRECTION OUTPUT ;
  USE SIGNAL ;
  PORT
   LAYER M3 ;
   RECT 472.500000 0.000000 472.518000 0.038000 ;
  END
 END lo[247]
 PIN lo[248]
  DIRECTION OUTPUT ;
  USE SIGNAL ;
  PORT
   LAYER M5 ;
   RECT 474.288000 0.000000 474.312000 0.084000 ;
  END
 END lo[248]
 PIN lo[249]
  DIRECTION OUTPUT ;
  USE SIGNAL ;
  PORT
   LAYER M3 ;
   RECT 476.100000 0.000000 476.118000 0.038000 ;
  END
 END lo[249]
 PIN lo[250]
  DIRECTION OUTPUT ;
  USE SIGNAL ;
  PORT
   LAYER M5 ;
   RECT 477.888000 0.000000 477.912000 0.084000 ;
  END
 END lo[250]
 PIN lo[251]
  DIRECTION OUTPUT ;
  USE SIGNAL ;
  PORT
   LAYER M3 ;
   RECT 479.700000 0.000000 479.718000 0.038000 ;
  END
 END lo[251]
 PIN lo[252]
  DIRECTION OUTPUT ;
  USE SIGNAL ;
  PORT
   LAYER M5 ;
   RECT 481.488000 0.000000 481.512000 0.084000 ;
  END
 END lo[252]
 PIN lo[253]
  DIRECTION OUTPUT ;
  USE SIGNAL ;
  PORT
   LAYER M3 ;
   RECT 483.300000 0.000000 483.318000 0.038000 ;
  END
 END lo[253]
 PIN lo[254]
  DIRECTION OUTPUT ;
  USE SIGNAL ;
  PORT
   LAYER M5 ;
   RECT 485.088000 0.000000 485.112000 0.084000 ;
  END
 END lo[254]
 PIN lo[255]
  DIRECTION OUTPUT ;
  USE SIGNAL ;
  PORT
   LAYER M3 ;
   RECT 486.900000 0.000000 486.918000 0.038000 ;
  END
 END lo[255]
 PIN lo[256]
  DIRECTION OUTPUT ;
  USE SIGNAL ;
  PORT
   LAYER M5 ;
   RECT 488.688000 0.000000 488.712000 0.084000 ;
  END
 END lo[256]
 PIN lo[22]
  DIRECTION OUTPUT ;
  USE SIGNAL ;
  PORT
   LAYER M5 ;
   RECT 67.488000 0.000000 67.512000 0.084000 ;
  END
 END lo[22]
 PIN lo[257]
  DIRECTION OUTPUT ;
  USE SIGNAL ;
  PORT
   LAYER M3 ;
   RECT 490.500000 0.000000 490.518000 0.038000 ;
  END
 END lo[257]
 PIN lo[258]
  DIRECTION OUTPUT ;
  USE SIGNAL ;
  PORT
   LAYER M5 ;
   RECT 492.288000 0.000000 492.312000 0.084000 ;
  END
 END lo[258]
 PIN lo[259]
  DIRECTION OUTPUT ;
  USE SIGNAL ;
  PORT
   LAYER M3 ;
   RECT 494.100000 0.000000 494.118000 0.038000 ;
  END
 END lo[259]
 PIN lo[260]
  DIRECTION OUTPUT ;
  USE SIGNAL ;
  PORT
   LAYER M5 ;
   RECT 495.888000 0.000000 495.912000 0.084000 ;
  END
 END lo[260]
 PIN lo[261]
  DIRECTION OUTPUT ;
  USE SIGNAL ;
  PORT
   LAYER M3 ;
   RECT 497.700000 0.000000 497.718000 0.038000 ;
  END
 END lo[261]
 PIN lo[262]
  DIRECTION OUTPUT ;
  USE SIGNAL ;
  PORT
   LAYER M5 ;
   RECT 499.488000 0.000000 499.512000 0.084000 ;
  END
 END lo[262]
 PIN lo[263]
  DIRECTION OUTPUT ;
  USE SIGNAL ;
  PORT
   LAYER M3 ;
   RECT 501.300000 0.000000 501.318000 0.038000 ;
  END
 END lo[263]
 PIN lo[264]
  DIRECTION OUTPUT ;
  USE SIGNAL ;
  PORT
   LAYER M5 ;
   RECT 503.088000 0.000000 503.112000 0.084000 ;
  END
 END lo[264]
 PIN lo[265]
  DIRECTION OUTPUT ;
  USE SIGNAL ;
  PORT
   LAYER M3 ;
   RECT 504.900000 0.000000 504.918000 0.038000 ;
  END
 END lo[265]
 PIN lo[266]
  DIRECTION OUTPUT ;
  USE SIGNAL ;
  PORT
   LAYER M5 ;
   RECT 506.688000 0.000000 506.712000 0.084000 ;
  END
 END lo[266]
 PIN lo[23]
  DIRECTION OUTPUT ;
  USE SIGNAL ;
  PORT
   LAYER M3 ;
   RECT 69.300000 0.000000 69.318000 0.038000 ;
  END
 END lo[23]
 PIN lo[267]
  DIRECTION OUTPUT ;
  USE SIGNAL ;
  PORT
   LAYER M3 ;
   RECT 508.500000 0.000000 508.518000 0.038000 ;
  END
 END lo[267]
 PIN lo[268]
  DIRECTION OUTPUT ;
  USE SIGNAL ;
  PORT
   LAYER M5 ;
   RECT 510.288000 0.000000 510.312000 0.084000 ;
  END
 END lo[268]
 PIN lo[269]
  DIRECTION OUTPUT ;
  USE SIGNAL ;
  PORT
   LAYER M3 ;
   RECT 512.100000 0.000000 512.118000 0.038000 ;
  END
 END lo[269]
 PIN lo[270]
  DIRECTION OUTPUT ;
  USE SIGNAL ;
  PORT
   LAYER M5 ;
   RECT 513.888000 0.000000 513.912000 0.084000 ;
  END
 END lo[270]
 PIN lo[271]
  DIRECTION OUTPUT ;
  USE SIGNAL ;
  PORT
   LAYER M3 ;
   RECT 515.700000 0.000000 515.718000 0.038000 ;
  END
 END lo[271]
 PIN lo[272]
  DIRECTION OUTPUT ;
  USE SIGNAL ;
  PORT
   LAYER M5 ;
   RECT 517.488000 0.000000 517.512000 0.084000 ;
  END
 END lo[272]
 PIN lo[24]
  DIRECTION OUTPUT ;
  USE SIGNAL ;
  PORT
   LAYER M5 ;
   RECT 71.088000 0.000000 71.112000 0.084000 ;
  END
 END lo[24]
 PIN lo[25]
  DIRECTION OUTPUT ;
  USE SIGNAL ;
  PORT
   LAYER M3 ;
   RECT 72.900000 0.000000 72.918000 0.038000 ;
  END
 END lo[25]
 PIN lo[26]
  DIRECTION OUTPUT ;
  USE SIGNAL ;
  PORT
   LAYER M5 ;
   RECT 74.688000 0.000000 74.712000 0.084000 ;
  END
 END lo[26]
 PIN lo[27]
  DIRECTION OUTPUT ;
  USE SIGNAL ;
  PORT
   LAYER M3 ;
   RECT 76.500000 0.000000 76.518000 0.038000 ;
  END
 END lo[27]
 PIN lo[28]
  DIRECTION OUTPUT ;
  USE SIGNAL ;
  PORT
   LAYER M5 ;
   RECT 78.288000 0.000000 78.312000 0.084000 ;
  END
 END lo[28]
 PIN lo[29]
  DIRECTION OUTPUT ;
  USE SIGNAL ;
  PORT
   LAYER M3 ;
   RECT 80.100000 0.000000 80.118000 0.038000 ;
  END
 END lo[29]
 PIN lo[30]
  DIRECTION OUTPUT ;
  USE SIGNAL ;
  PORT
   LAYER M5 ;
   RECT 81.888000 0.000000 81.912000 0.084000 ;
  END
 END lo[30]
 PIN lo[31]
  DIRECTION OUTPUT ;
  USE SIGNAL ;
  PORT
   LAYER M3 ;
   RECT 83.700000 0.000000 83.718000 0.038000 ;
  END
 END lo[31]
 PIN lo[32]
  DIRECTION OUTPUT ;
  USE SIGNAL ;
  PORT
   LAYER M5 ;
   RECT 85.488000 0.000000 85.512000 0.084000 ;
  END
 END lo[32]
 PIN lo[33]
  DIRECTION OUTPUT ;
  USE SIGNAL ;
  PORT
   LAYER M3 ;
   RECT 87.300000 0.000000 87.318000 0.038000 ;
  END
 END lo[33]
 PIN lo[34]
  DIRECTION OUTPUT ;
  USE SIGNAL ;
  PORT
   LAYER M5 ;
   RECT 89.088000 0.000000 89.112000 0.084000 ;
  END
 END lo[34]
 PIN lo[35]
  DIRECTION OUTPUT ;
  USE SIGNAL ;
  PORT
   LAYER M3 ;
   RECT 90.900000 0.000000 90.918000 0.038000 ;
  END
 END lo[35]
 PIN lo[36]
  DIRECTION OUTPUT ;
  USE SIGNAL ;
  PORT
   LAYER M5 ;
   RECT 92.688000 0.000000 92.712000 0.084000 ;
  END
 END lo[36]
 PIN lo[1]
  DIRECTION OUTPUT ;
  USE SIGNAL ;
  PORT
   LAYER M5 ;
   RECT 27.888000 0.000000 27.912000 0.084000 ;
  END
 END lo[1]
 PIN lo[37]
  DIRECTION OUTPUT ;
  USE SIGNAL ;
  PORT
   LAYER M3 ;
   RECT 94.500000 0.000000 94.518000 0.038000 ;
  END
 END lo[37]
 PIN lo[38]
  DIRECTION OUTPUT ;
  USE SIGNAL ;
  PORT
   LAYER M5 ;
   RECT 96.288000 0.000000 96.312000 0.084000 ;
  END
 END lo[38]
 PIN lo[39]
  DIRECTION OUTPUT ;
  USE SIGNAL ;
  PORT
   LAYER M3 ;
   RECT 98.100000 0.000000 98.118000 0.038000 ;
  END
 END lo[39]
 PIN lo[40]
  DIRECTION OUTPUT ;
  USE SIGNAL ;
  PORT
   LAYER M5 ;
   RECT 99.888000 0.000000 99.912000 0.084000 ;
  END
 END lo[40]
 PIN lo[41]
  DIRECTION OUTPUT ;
  USE SIGNAL ;
  PORT
   LAYER M3 ;
   RECT 101.700000 0.000000 101.718000 0.038000 ;
  END
 END lo[41]
 PIN lo[42]
  DIRECTION OUTPUT ;
  USE SIGNAL ;
  PORT
   LAYER M5 ;
   RECT 103.488000 0.000000 103.512000 0.084000 ;
  END
 END lo[42]
 PIN lo[43]
  DIRECTION OUTPUT ;
  USE SIGNAL ;
  PORT
   LAYER M3 ;
   RECT 105.300000 0.000000 105.318000 0.038000 ;
  END
 END lo[43]
 PIN lo[44]
  DIRECTION OUTPUT ;
  USE SIGNAL ;
  PORT
   LAYER M5 ;
   RECT 107.088000 0.000000 107.112000 0.084000 ;
  END
 END lo[44]
 PIN lo[45]
  DIRECTION OUTPUT ;
  USE SIGNAL ;
  PORT
   LAYER M3 ;
   RECT 108.900000 0.000000 108.918000 0.038000 ;
  END
 END lo[45]
 PIN lo[46]
  DIRECTION OUTPUT ;
  USE SIGNAL ;
  PORT
   LAYER M5 ;
   RECT 110.688000 0.000000 110.712000 0.084000 ;
  END
 END lo[46]
 PIN lo[2]
  DIRECTION OUTPUT ;
  USE SIGNAL ;
  PORT
   LAYER M3 ;
   RECT 29.700000 0.000000 29.718000 0.038000 ;
  END
 END lo[2]
 PIN lo[47]
  DIRECTION OUTPUT ;
  USE SIGNAL ;
  PORT
   LAYER M3 ;
   RECT 112.500000 0.000000 112.518000 0.038000 ;
  END
 END lo[47]
 PIN lo[48]
  DIRECTION OUTPUT ;
  USE SIGNAL ;
  PORT
   LAYER M5 ;
   RECT 114.288000 0.000000 114.312000 0.084000 ;
  END
 END lo[48]
 PIN lo[49]
  DIRECTION OUTPUT ;
  USE SIGNAL ;
  PORT
   LAYER M3 ;
   RECT 116.100000 0.000000 116.118000 0.038000 ;
  END
 END lo[49]
 PIN lo[50]
  DIRECTION OUTPUT ;
  USE SIGNAL ;
  PORT
   LAYER M5 ;
   RECT 117.888000 0.000000 117.912000 0.084000 ;
  END
 END lo[50]
 PIN lo[51]
  DIRECTION OUTPUT ;
  USE SIGNAL ;
  PORT
   LAYER M3 ;
   RECT 119.700000 0.000000 119.718000 0.038000 ;
  END
 END lo[51]
 PIN lo[52]
  DIRECTION OUTPUT ;
  USE SIGNAL ;
  PORT
   LAYER M5 ;
   RECT 121.488000 0.000000 121.512000 0.084000 ;
  END
 END lo[52]
 PIN lo[53]
  DIRECTION OUTPUT ;
  USE SIGNAL ;
  PORT
   LAYER M3 ;
   RECT 123.300000 0.000000 123.318000 0.038000 ;
  END
 END lo[53]
 PIN lo[54]
  DIRECTION OUTPUT ;
  USE SIGNAL ;
  PORT
   LAYER M5 ;
   RECT 125.088000 0.000000 125.112000 0.084000 ;
  END
 END lo[54]
 PIN lo[55]
  DIRECTION OUTPUT ;
  USE SIGNAL ;
  PORT
   LAYER M3 ;
   RECT 126.900000 0.000000 126.918000 0.038000 ;
  END
 END lo[55]
 PIN lo[56]
  DIRECTION OUTPUT ;
  USE SIGNAL ;
  PORT
   LAYER M5 ;
   RECT 128.688000 0.000000 128.712000 0.084000 ;
  END
 END lo[56]
 PIN lo[3]
  DIRECTION OUTPUT ;
  USE SIGNAL ;
  PORT
   LAYER M5 ;
   RECT 31.488000 0.000000 31.512000 0.084000 ;
  END
 END lo[3]
 PIN lo[57]
  DIRECTION OUTPUT ;
  USE SIGNAL ;
  PORT
   LAYER M3 ;
   RECT 130.500000 0.000000 130.518000 0.038000 ;
  END
 END lo[57]
 PIN lo[58]
  DIRECTION OUTPUT ;
  USE SIGNAL ;
  PORT
   LAYER M5 ;
   RECT 132.288000 0.000000 132.312000 0.084000 ;
  END
 END lo[58]
 PIN lo[59]
  DIRECTION OUTPUT ;
  USE SIGNAL ;
  PORT
   LAYER M3 ;
   RECT 134.100000 0.000000 134.118000 0.038000 ;
  END
 END lo[59]
 PIN lo[60]
  DIRECTION OUTPUT ;
  USE SIGNAL ;
  PORT
   LAYER M5 ;
   RECT 135.888000 0.000000 135.912000 0.084000 ;
  END
 END lo[60]
 PIN lo[61]
  DIRECTION OUTPUT ;
  USE SIGNAL ;
  PORT
   LAYER M3 ;
   RECT 137.700000 0.000000 137.718000 0.038000 ;
  END
 END lo[61]
 PIN lo[62]
  DIRECTION OUTPUT ;
  USE SIGNAL ;
  PORT
   LAYER M5 ;
   RECT 139.488000 0.000000 139.512000 0.084000 ;
  END
 END lo[62]
 PIN lo[63]
  DIRECTION OUTPUT ;
  USE SIGNAL ;
  PORT
   LAYER M3 ;
   RECT 141.300000 0.000000 141.318000 0.038000 ;
  END
 END lo[63]
 PIN lo[64]
  DIRECTION OUTPUT ;
  USE SIGNAL ;
  PORT
   LAYER M5 ;
   RECT 143.088000 0.000000 143.112000 0.084000 ;
  END
 END lo[64]
 PIN lo[65]
  DIRECTION OUTPUT ;
  USE SIGNAL ;
  PORT
   LAYER M3 ;
   RECT 144.900000 0.000000 144.918000 0.038000 ;
  END
 END lo[65]
 PIN lo[66]
  DIRECTION OUTPUT ;
  USE SIGNAL ;
  PORT
   LAYER M5 ;
   RECT 146.688000 0.000000 146.712000 0.084000 ;
  END
 END lo[66]
 PIN lo[4]
  DIRECTION OUTPUT ;
  USE SIGNAL ;
  PORT
   LAYER M3 ;
   RECT 33.300000 0.000000 33.318000 0.038000 ;
  END
 END lo[4]
 PIN lo[67]
  DIRECTION OUTPUT ;
  USE SIGNAL ;
  PORT
   LAYER M3 ;
   RECT 148.500000 0.000000 148.518000 0.038000 ;
  END
 END lo[67]
 PIN lo[68]
  DIRECTION OUTPUT ;
  USE SIGNAL ;
  PORT
   LAYER M5 ;
   RECT 150.288000 0.000000 150.312000 0.084000 ;
  END
 END lo[68]
 PIN lo[69]
  DIRECTION OUTPUT ;
  USE SIGNAL ;
  PORT
   LAYER M3 ;
   RECT 152.100000 0.000000 152.118000 0.038000 ;
  END
 END lo[69]
 PIN lo[70]
  DIRECTION OUTPUT ;
  USE SIGNAL ;
  PORT
   LAYER M5 ;
   RECT 153.888000 0.000000 153.912000 0.084000 ;
  END
 END lo[70]
 PIN lo[71]
  DIRECTION OUTPUT ;
  USE SIGNAL ;
  PORT
   LAYER M3 ;
   RECT 155.700000 0.000000 155.718000 0.038000 ;
  END
 END lo[71]
 PIN lo[72]
  DIRECTION OUTPUT ;
  USE SIGNAL ;
  PORT
   LAYER M5 ;
   RECT 157.488000 0.000000 157.512000 0.084000 ;
  END
 END lo[72]
 PIN lo[73]
  DIRECTION OUTPUT ;
  USE SIGNAL ;
  PORT
   LAYER M3 ;
   RECT 159.300000 0.000000 159.318000 0.038000 ;
  END
 END lo[73]
 PIN lo[74]
  DIRECTION OUTPUT ;
  USE SIGNAL ;
  PORT
   LAYER M5 ;
   RECT 161.088000 0.000000 161.112000 0.084000 ;
  END
 END lo[74]
 PIN lo[75]
  DIRECTION OUTPUT ;
  USE SIGNAL ;
  PORT
   LAYER M3 ;
   RECT 162.900000 0.000000 162.918000 0.038000 ;
  END
 END lo[75]
 PIN lo[76]
  DIRECTION OUTPUT ;
  USE SIGNAL ;
  PORT
   LAYER M5 ;
   RECT 164.688000 0.000000 164.712000 0.084000 ;
  END
 END lo[76]
 PIN lo[5]
  DIRECTION OUTPUT ;
  USE SIGNAL ;
  PORT
   LAYER M5 ;
   RECT 35.088000 0.000000 35.112000 0.084000 ;
  END
 END lo[5]
 PIN lo[77]
  DIRECTION OUTPUT ;
  USE SIGNAL ;
  PORT
   LAYER M3 ;
   RECT 166.500000 0.000000 166.518000 0.038000 ;
  END
 END lo[77]
 PIN lo[78]
  DIRECTION OUTPUT ;
  USE SIGNAL ;
  PORT
   LAYER M5 ;
   RECT 168.288000 0.000000 168.312000 0.084000 ;
  END
 END lo[78]
 PIN lo[79]
  DIRECTION OUTPUT ;
  USE SIGNAL ;
  PORT
   LAYER M3 ;
   RECT 170.100000 0.000000 170.118000 0.038000 ;
  END
 END lo[79]
 PIN lo[80]
  DIRECTION OUTPUT ;
  USE SIGNAL ;
  PORT
   LAYER M5 ;
   RECT 171.888000 0.000000 171.912000 0.084000 ;
  END
 END lo[80]
 PIN lo[81]
  DIRECTION OUTPUT ;
  USE SIGNAL ;
  PORT
   LAYER M3 ;
   RECT 173.700000 0.000000 173.718000 0.038000 ;
  END
 END lo[81]
 PIN lo[82]
  DIRECTION OUTPUT ;
  USE SIGNAL ;
  PORT
   LAYER M5 ;
   RECT 175.488000 0.000000 175.512000 0.084000 ;
  END
 END lo[82]
 PIN lo[83]
  DIRECTION OUTPUT ;
  USE SIGNAL ;
  PORT
   LAYER M3 ;
   RECT 177.300000 0.000000 177.318000 0.038000 ;
  END
 END lo[83]
 PIN lo[84]
  DIRECTION OUTPUT ;
  USE SIGNAL ;
  PORT
   LAYER M5 ;
   RECT 179.088000 0.000000 179.112000 0.084000 ;
  END
 END lo[84]
 PIN lo[85]
  DIRECTION OUTPUT ;
  USE SIGNAL ;
  PORT
   LAYER M3 ;
   RECT 180.900000 0.000000 180.918000 0.038000 ;
  END
 END lo[85]
 PIN lo[86]
  DIRECTION OUTPUT ;
  USE SIGNAL ;
  PORT
   LAYER M5 ;
   RECT 182.688000 0.000000 182.712000 0.084000 ;
  END
 END lo[86]
 PIN lo[6]
  DIRECTION OUTPUT ;
  USE SIGNAL ;
  PORT
   LAYER M3 ;
   RECT 36.900000 0.000000 36.918000 0.038000 ;
  END
 END lo[6]
 PIN lo[87]
  DIRECTION OUTPUT ;
  USE SIGNAL ;
  PORT
   LAYER M3 ;
   RECT 184.500000 0.000000 184.518000 0.038000 ;
  END
 END lo[87]
 PIN lo[88]
  DIRECTION OUTPUT ;
  USE SIGNAL ;
  PORT
   LAYER M5 ;
   RECT 186.288000 0.000000 186.312000 0.084000 ;
  END
 END lo[88]
 PIN lo[89]
  DIRECTION OUTPUT ;
  USE SIGNAL ;
  PORT
   LAYER M3 ;
   RECT 188.100000 0.000000 188.118000 0.038000 ;
  END
 END lo[89]
 PIN lo[90]
  DIRECTION OUTPUT ;
  USE SIGNAL ;
  PORT
   LAYER M5 ;
   RECT 189.888000 0.000000 189.912000 0.084000 ;
  END
 END lo[90]
 PIN lo[91]
  DIRECTION OUTPUT ;
  USE SIGNAL ;
  PORT
   LAYER M3 ;
   RECT 191.700000 0.000000 191.718000 0.038000 ;
  END
 END lo[91]
 PIN lo[92]
  DIRECTION OUTPUT ;
  USE SIGNAL ;
  PORT
   LAYER M5 ;
   RECT 193.488000 0.000000 193.512000 0.084000 ;
  END
 END lo[92]
 PIN lo[93]
  DIRECTION OUTPUT ;
  USE SIGNAL ;
  PORT
   LAYER M3 ;
   RECT 195.300000 0.000000 195.318000 0.038000 ;
  END
 END lo[93]
 PIN lo[94]
  DIRECTION OUTPUT ;
  USE SIGNAL ;
  PORT
   LAYER M5 ;
   RECT 197.088000 0.000000 197.112000 0.084000 ;
  END
 END lo[94]
 PIN lo[95]
  DIRECTION OUTPUT ;
  USE SIGNAL ;
  PORT
   LAYER M3 ;
   RECT 198.900000 0.000000 198.918000 0.038000 ;
  END
 END lo[95]
 PIN lo[96]
  DIRECTION OUTPUT ;
  USE SIGNAL ;
  PORT
   LAYER M5 ;
   RECT 200.688000 0.000000 200.712000 0.084000 ;
  END
 END lo[96]
 PIN lo[7]
  DIRECTION OUTPUT ;
  USE SIGNAL ;
  PORT
   LAYER M5 ;
   RECT 38.688000 0.000000 38.712000 0.084000 ;
  END
 END lo[7]
 PIN rst
  DIRECTION INPUT ;
  USE SIGNAL ;
  PORT
   LAYER M4 ;
   RECT 0.000000 407.712000 0.084000 407.736000 ;
  END
 END rst
 PIN st[0]
  DIRECTION OUTPUT ;
  USE SIGNAL ;
  PORT
   LAYER M3 ;
   RECT 531.540000 0.000000 531.558000 0.038000 ;
  END
 END st[0]
 PIN st[6]
  DIRECTION OUTPUT ;
  USE SIGNAL ;
  PORT
   LAYER M3 ;
   RECT 578.808000 0.000000 578.826000 0.038000 ;
  END
 END st[6]
 PIN st[7]
  DIRECTION OUTPUT ;
  USE SIGNAL ;
  PORT
   LAYER M5 ;
   RECT 583.536000 0.000000 583.560000 0.084000 ;
  END
 END st[7]
 PIN st[8]
  DIRECTION OUTPUT ;
  USE SIGNAL ;
  PORT
   LAYER M3 ;
   RECT 588.240000 0.000000 588.258000 0.038000 ;
  END
 END st[8]
 PIN st[9]
  DIRECTION OUTPUT ;
  USE SIGNAL ;
  PORT
   LAYER M5 ;
   RECT 592.992000 0.000000 593.016000 0.084000 ;
  END
 END st[9]
 PIN st[10]
  DIRECTION OUTPUT ;
  USE SIGNAL ;
  PORT
   LAYER M3 ;
   RECT 597.708000 0.000000 597.726000 0.038000 ;
  END
 END st[10]
 PIN st[11]
  DIRECTION OUTPUT ;
  USE SIGNAL ;
  PORT
   LAYER M5 ;
   RECT 602.448000 0.000000 602.472000 0.084000 ;
  END
 END st[11]
 PIN st[1]
  DIRECTION OUTPUT ;
  USE SIGNAL ;
  PORT
   LAYER M5 ;
   RECT 536.256000 0.000000 536.280000 0.084000 ;
  END
 END st[1]
 PIN st[2]
  DIRECTION OUTPUT ;
  USE SIGNAL ;
  PORT
   LAYER M3 ;
   RECT 541.008000 0.000000 541.026000 0.038000 ;
  END
 END st[2]
 PIN st[3]
  DIRECTION OUTPUT ;
  USE SIGNAL ;
  PORT
   LAYER M5 ;
   RECT 545.712000 0.000000 545.736000 0.084000 ;
  END
 END st[3]
 PIN st[4]
  DIRECTION OUTPUT ;
  USE SIGNAL ;
  PORT
   LAYER M3 ;
   RECT 569.340000 0.000000 569.358000 0.038000 ;
  END
 END st[4]
 PIN st[5]
  DIRECTION OUTPUT ;
  USE SIGNAL ;
  PORT
   LAYER M5 ;
   RECT 574.080000 0.000000 574.104000 0.084000 ;
  END
 END st[5]
 PIN vi[0]
  DIRECTION INPUT ;
  USE SIGNAL ;
  PORT
   LAYER M3 ;
   RECT 22.104000 544.282000 22.122000 544.320000 ;
  END
 END vi[0]
 PIN vi[92]
  DIRECTION INPUT ;
  USE SIGNAL ;
  PORT
   LAYER M3 ;
   RECT 123.840000 544.282000 123.858000 544.320000 ;
  END
 END vi[92]
 PIN vi[93]
  DIRECTION INPUT ;
  USE SIGNAL ;
  PORT
   LAYER M5 ;
   RECT 124.848000 544.236000 124.872000 544.320000 ;
  END
 END vi[93]
 PIN vi[94]
  DIRECTION INPUT ;
  USE SIGNAL ;
  PORT
   LAYER M3 ;
   RECT 125.892000 544.282000 125.910000 544.320000 ;
  END
 END vi[94]
 PIN vi[95]
  DIRECTION INPUT ;
  USE SIGNAL ;
  PORT
   LAYER M5 ;
   RECT 126.912000 544.236000 126.936000 544.320000 ;
  END
 END vi[95]
 PIN vi[96]
  DIRECTION INPUT ;
  USE SIGNAL ;
  PORT
   LAYER M3 ;
   RECT 127.908000 544.282000 127.926000 544.320000 ;
  END
 END vi[96]
 PIN vi[97]
  DIRECTION INPUT ;
  USE SIGNAL ;
  PORT
   LAYER M5 ;
   RECT 128.928000 544.236000 128.952000 544.320000 ;
  END
 END vi[97]
 PIN vi[98]
  DIRECTION INPUT ;
  USE SIGNAL ;
  PORT
   LAYER M3 ;
   RECT 129.960000 544.282000 129.978000 544.320000 ;
  END
 END vi[98]
 PIN vi[99]
  DIRECTION INPUT ;
  USE SIGNAL ;
  PORT
   LAYER M5 ;
   RECT 130.944000 544.236000 130.968000 544.320000 ;
  END
 END vi[99]
 PIN vi[100]
  DIRECTION INPUT ;
  USE SIGNAL ;
  PORT
   LAYER M3 ;
   RECT 131.976000 544.282000 131.994000 544.320000 ;
  END
 END vi[100]
 PIN vi[101]
  DIRECTION INPUT ;
  USE SIGNAL ;
  PORT
   LAYER M5 ;
   RECT 133.008000 544.236000 133.032000 544.320000 ;
  END
 END vi[101]
 PIN vi[102]
  DIRECTION INPUT ;
  USE SIGNAL ;
  PORT
   LAYER M3 ;
   RECT 134.028000 544.282000 134.046000 544.320000 ;
  END
 END vi[102]
 PIN vi[103]
  DIRECTION INPUT ;
  USE SIGNAL ;
  PORT
   LAYER M5 ;
   RECT 135.024000 544.236000 135.048000 544.320000 ;
  END
 END vi[103]
 PIN vi[104]
  DIRECTION INPUT ;
  USE SIGNAL ;
  PORT
   LAYER M3 ;
   RECT 136.044000 544.282000 136.062000 544.320000 ;
  END
 END vi[104]
 PIN vi[105]
  DIRECTION INPUT ;
  USE SIGNAL ;
  PORT
   LAYER M5 ;
   RECT 137.040000 544.236000 137.064000 544.320000 ;
  END
 END vi[105]
 PIN vi[106]
  DIRECTION INPUT ;
  USE SIGNAL ;
  PORT
   LAYER M3 ;
   RECT 138.096000 544.282000 138.114000 544.320000 ;
  END
 END vi[106]
 PIN vi[107]
  DIRECTION INPUT ;
  USE SIGNAL ;
  PORT
   LAYER M5 ;
   RECT 139.104000 544.236000 139.128000 544.320000 ;
  END
 END vi[107]
 PIN vi[108]
  DIRECTION INPUT ;
  USE SIGNAL ;
  PORT
   LAYER M3 ;
   RECT 140.112000 544.282000 140.130000 544.320000 ;
  END
 END vi[108]
 PIN vi[109]
  DIRECTION INPUT ;
  USE SIGNAL ;
  PORT
   LAYER M5 ;
   RECT 141.120000 544.236000 141.144000 544.320000 ;
  END
 END vi[109]
 PIN vi[110]
  DIRECTION INPUT ;
  USE SIGNAL ;
  PORT
   LAYER M3 ;
   RECT 142.164000 544.282000 142.182000 544.320000 ;
  END
 END vi[110]
 PIN vi[111]
  DIRECTION INPUT ;
  USE SIGNAL ;
  PORT
   LAYER M5 ;
   RECT 143.184000 544.236000 143.208000 544.320000 ;
  END
 END vi[111]
 PIN vi[112]
  DIRECTION INPUT ;
  USE SIGNAL ;
  PORT
   LAYER M3 ;
   RECT 144.180000 544.282000 144.198000 544.320000 ;
  END
 END vi[112]
 PIN vi[113]
  DIRECTION INPUT ;
  USE SIGNAL ;
  PORT
   LAYER M5 ;
   RECT 145.200000 544.236000 145.224000 544.320000 ;
  END
 END vi[113]
 PIN vi[114]
  DIRECTION INPUT ;
  USE SIGNAL ;
  PORT
   LAYER M3 ;
   RECT 146.232000 544.282000 146.250000 544.320000 ;
  END
 END vi[114]
 PIN vi[115]
  DIRECTION INPUT ;
  USE SIGNAL ;
  PORT
   LAYER M5 ;
   RECT 147.216000 544.236000 147.240000 544.320000 ;
  END
 END vi[115]
 PIN vi[116]
  DIRECTION INPUT ;
  USE SIGNAL ;
  PORT
   LAYER M3 ;
   RECT 148.248000 544.282000 148.266000 544.320000 ;
  END
 END vi[116]
 PIN vi[117]
  DIRECTION INPUT ;
  USE SIGNAL ;
  PORT
   LAYER M5 ;
   RECT 149.280000 544.236000 149.304000 544.320000 ;
  END
 END vi[117]
 PIN vi[118]
  DIRECTION INPUT ;
  USE SIGNAL ;
  PORT
   LAYER M3 ;
   RECT 150.300000 544.282000 150.318000 544.320000 ;
  END
 END vi[118]
 PIN vi[119]
  DIRECTION INPUT ;
  USE SIGNAL ;
  PORT
   LAYER M5 ;
   RECT 151.296000 544.236000 151.320000 544.320000 ;
  END
 END vi[119]
 PIN vi[120]
  DIRECTION INPUT ;
  USE SIGNAL ;
  PORT
   LAYER M3 ;
   RECT 152.316000 544.282000 152.334000 544.320000 ;
  END
 END vi[120]
 PIN vi[121]
  DIRECTION INPUT ;
  USE SIGNAL ;
  PORT
   LAYER M5 ;
   RECT 153.360000 544.236000 153.384000 544.320000 ;
  END
 END vi[121]
 PIN vi[122]
  DIRECTION INPUT ;
  USE SIGNAL ;
  PORT
   LAYER M3 ;
   RECT 154.368000 544.282000 154.386000 544.320000 ;
  END
 END vi[122]
 PIN vi[123]
  DIRECTION INPUT ;
  USE SIGNAL ;
  PORT
   LAYER M5 ;
   RECT 155.376000 544.236000 155.400000 544.320000 ;
  END
 END vi[123]
 PIN vi[124]
  DIRECTION INPUT ;
  USE SIGNAL ;
  PORT
   LAYER M3 ;
   RECT 156.384000 544.282000 156.402000 544.320000 ;
  END
 END vi[124]
 PIN vi[125]
  DIRECTION INPUT ;
  USE SIGNAL ;
  PORT
   LAYER M5 ;
   RECT 157.392000 544.236000 157.416000 544.320000 ;
  END
 END vi[125]
 PIN vi[126]
  DIRECTION INPUT ;
  USE SIGNAL ;
  PORT
   LAYER M3 ;
   RECT 158.436000 544.282000 158.454000 544.320000 ;
  END
 END vi[126]
 PIN vi[127]
  DIRECTION INPUT ;
  USE SIGNAL ;
  PORT
   LAYER M5 ;
   RECT 159.456000 544.236000 159.480000 544.320000 ;
  END
 END vi[127]
 PIN vi[128]
  DIRECTION INPUT ;
  USE SIGNAL ;
  PORT
   LAYER M3 ;
   RECT 160.452000 544.282000 160.470000 544.320000 ;
  END
 END vi[128]
 PIN vi[129]
  DIRECTION INPUT ;
  USE SIGNAL ;
  PORT
   LAYER M5 ;
   RECT 161.472000 544.236000 161.496000 544.320000 ;
  END
 END vi[129]
 PIN vi[130]
  DIRECTION INPUT ;
  USE SIGNAL ;
  PORT
   LAYER M3 ;
   RECT 162.504000 544.282000 162.522000 544.320000 ;
  END
 END vi[130]
 PIN vi[131]
  DIRECTION INPUT ;
  USE SIGNAL ;
  PORT
   LAYER M5 ;
   RECT 163.536000 544.236000 163.560000 544.320000 ;
  END
 END vi[131]
 PIN vi[132]
  DIRECTION INPUT ;
  USE SIGNAL ;
  PORT
   LAYER M3 ;
   RECT 164.520000 544.282000 164.538000 544.320000 ;
  END
 END vi[132]
 PIN vi[133]
  DIRECTION INPUT ;
  USE SIGNAL ;
  PORT
   LAYER M5 ;
   RECT 165.552000 544.236000 165.576000 544.320000 ;
  END
 END vi[133]
 PIN vi[134]
  DIRECTION INPUT ;
  USE SIGNAL ;
  PORT
   LAYER M3 ;
   RECT 166.572000 544.282000 166.590000 544.320000 ;
  END
 END vi[134]
 PIN vi[135]
  DIRECTION INPUT ;
  USE SIGNAL ;
  PORT
   LAYER M5 ;
   RECT 167.568000 544.236000 167.592000 544.320000 ;
  END
 END vi[135]
 PIN vi[136]
  DIRECTION INPUT ;
  USE SIGNAL ;
  PORT
   LAYER M3 ;
   RECT 168.588000 544.282000 168.606000 544.320000 ;
  END
 END vi[136]
 PIN vi[137]
  DIRECTION INPUT ;
  USE SIGNAL ;
  PORT
   LAYER M5 ;
   RECT 169.632000 544.236000 169.656000 544.320000 ;
  END
 END vi[137]
 PIN vi[138]
  DIRECTION INPUT ;
  USE SIGNAL ;
  PORT
   LAYER M3 ;
   RECT 170.640000 544.282000 170.658000 544.320000 ;
  END
 END vi[138]
 PIN vi[139]
  DIRECTION INPUT ;
  USE SIGNAL ;
  PORT
   LAYER M5 ;
   RECT 171.648000 544.236000 171.672000 544.320000 ;
  END
 END vi[139]
 PIN vi[140]
  DIRECTION INPUT ;
  USE SIGNAL ;
  PORT
   LAYER M3 ;
   RECT 172.692000 544.282000 172.710000 544.320000 ;
  END
 END vi[140]
 PIN vi[141]
  DIRECTION INPUT ;
  USE SIGNAL ;
  PORT
   LAYER M5 ;
   RECT 173.712000 544.236000 173.736000 544.320000 ;
  END
 END vi[141]
 PIN vi[142]
  DIRECTION INPUT ;
  USE SIGNAL ;
  PORT
   LAYER M3 ;
   RECT 174.852000 544.282000 174.870000 544.320000 ;
  END
 END vi[142]
 PIN vi[143]
  DIRECTION INPUT ;
  USE SIGNAL ;
  PORT
   LAYER M5 ;
   RECT 175.728000 544.236000 175.752000 544.320000 ;
  END
 END vi[143]
 PIN vi[144]
  DIRECTION INPUT ;
  USE SIGNAL ;
  PORT
   LAYER M3 ;
   RECT 176.760000 544.282000 176.778000 544.320000 ;
  END
 END vi[144]
 PIN vi[145]
  DIRECTION INPUT ;
  USE SIGNAL ;
  PORT
   LAYER M5 ;
   RECT 177.744000 544.236000 177.768000 544.320000 ;
  END
 END vi[145]
 PIN vi[146]
  DIRECTION INPUT ;
  USE SIGNAL ;
  PORT
   LAYER M3 ;
   RECT 178.776000 544.282000 178.794000 544.320000 ;
  END
 END vi[146]
 PIN vi[147]
  DIRECTION INPUT ;
  USE SIGNAL ;
  PORT
   LAYER M5 ;
   RECT 179.808000 544.236000 179.832000 544.320000 ;
  END
 END vi[147]
 PIN vi[148]
  DIRECTION INPUT ;
  USE SIGNAL ;
  PORT
   LAYER M3 ;
   RECT 180.828000 544.282000 180.846000 544.320000 ;
  END
 END vi[148]
 PIN vi[149]
  DIRECTION INPUT ;
  USE SIGNAL ;
  PORT
   LAYER M5 ;
   RECT 181.824000 544.236000 181.848000 544.320000 ;
  END
 END vi[149]
 PIN vi[150]
  DIRECTION INPUT ;
  USE SIGNAL ;
  PORT
   LAYER M3 ;
   RECT 182.844000 544.282000 182.862000 544.320000 ;
  END
 END vi[150]
 PIN vi[151]
  DIRECTION INPUT ;
  USE SIGNAL ;
  PORT
   LAYER M5 ;
   RECT 183.840000 544.236000 183.864000 544.320000 ;
  END
 END vi[151]
 PIN vi[152]
  DIRECTION INPUT ;
  USE SIGNAL ;
  PORT
   LAYER M3 ;
   RECT 184.896000 544.282000 184.914000 544.320000 ;
  END
 END vi[152]
 PIN vi[153]
  DIRECTION INPUT ;
  USE SIGNAL ;
  PORT
   LAYER M5 ;
   RECT 185.904000 544.236000 185.928000 544.320000 ;
  END
 END vi[153]
 PIN vi[154]
  DIRECTION INPUT ;
  USE SIGNAL ;
  PORT
   LAYER M3 ;
   RECT 186.912000 544.282000 186.930000 544.320000 ;
  END
 END vi[154]
 PIN vi[155]
  DIRECTION INPUT ;
  USE SIGNAL ;
  PORT
   LAYER M5 ;
   RECT 187.920000 544.236000 187.944000 544.320000 ;
  END
 END vi[155]
 PIN vi[156]
  DIRECTION INPUT ;
  USE SIGNAL ;
  PORT
   LAYER M3 ;
   RECT 188.964000 544.282000 188.982000 544.320000 ;
  END
 END vi[156]
 PIN vi[157]
  DIRECTION INPUT ;
  USE SIGNAL ;
  PORT
   LAYER M5 ;
   RECT 189.984000 544.236000 190.008000 544.320000 ;
  END
 END vi[157]
 PIN vi[158]
  DIRECTION INPUT ;
  USE SIGNAL ;
  PORT
   LAYER M3 ;
   RECT 190.980000 544.282000 190.998000 544.320000 ;
  END
 END vi[158]
 PIN vi[159]
  DIRECTION INPUT ;
  USE SIGNAL ;
  PORT
   LAYER M5 ;
   RECT 192.000000 544.236000 192.024000 544.320000 ;
  END
 END vi[159]
 PIN vi[160]
  DIRECTION INPUT ;
  USE SIGNAL ;
  PORT
   LAYER M3 ;
   RECT 193.032000 544.282000 193.050000 544.320000 ;
  END
 END vi[160]
 PIN vi[161]
  DIRECTION INPUT ;
  USE SIGNAL ;
  PORT
   LAYER M5 ;
   RECT 194.016000 544.236000 194.040000 544.320000 ;
  END
 END vi[161]
 PIN vi[8]
  DIRECTION INPUT ;
  USE SIGNAL ;
  PORT
   LAYER M3 ;
   RECT 38.376000 544.282000 38.394000 544.320000 ;
  END
 END vi[8]
 PIN vi[162]
  DIRECTION INPUT ;
  USE SIGNAL ;
  PORT
   LAYER M3 ;
   RECT 195.048000 544.282000 195.066000 544.320000 ;
  END
 END vi[162]
 PIN vi[163]
  DIRECTION INPUT ;
  USE SIGNAL ;
  PORT
   LAYER M5 ;
   RECT 196.080000 544.236000 196.104000 544.320000 ;
  END
 END vi[163]
 PIN vi[164]
  DIRECTION INPUT ;
  USE SIGNAL ;
  PORT
   LAYER M3 ;
   RECT 197.100000 544.282000 197.118000 544.320000 ;
  END
 END vi[164]
 PIN vi[165]
  DIRECTION INPUT ;
  USE SIGNAL ;
  PORT
   LAYER M5 ;
   RECT 198.096000 544.236000 198.120000 544.320000 ;
  END
 END vi[165]
 PIN vi[166]
  DIRECTION INPUT ;
  USE SIGNAL ;
  PORT
   LAYER M3 ;
   RECT 199.116000 544.282000 199.134000 544.320000 ;
  END
 END vi[166]
 PIN vi[167]
  DIRECTION INPUT ;
  USE SIGNAL ;
  PORT
   LAYER M5 ;
   RECT 200.160000 544.236000 200.184000 544.320000 ;
  END
 END vi[167]
 PIN vi[168]
  DIRECTION INPUT ;
  USE SIGNAL ;
  PORT
   LAYER M3 ;
   RECT 201.168000 544.282000 201.186000 544.320000 ;
  END
 END vi[168]
 PIN vi[169]
  DIRECTION INPUT ;
  USE SIGNAL ;
  PORT
   LAYER M5 ;
   RECT 202.176000 544.236000 202.200000 544.320000 ;
  END
 END vi[169]
 PIN vi[170]
  DIRECTION INPUT ;
  USE SIGNAL ;
  PORT
   LAYER M3 ;
   RECT 203.184000 544.282000 203.202000 544.320000 ;
  END
 END vi[170]
 PIN vi[171]
  DIRECTION INPUT ;
  USE SIGNAL ;
  PORT
   LAYER M5 ;
   RECT 204.192000 544.236000 204.216000 544.320000 ;
  END
 END vi[171]
 PIN vi[9]
  DIRECTION INPUT ;
  USE SIGNAL ;
  PORT
   LAYER M5 ;
   RECT 39.408000 544.236000 39.432000 544.320000 ;
  END
 END vi[9]
 PIN vi[172]
  DIRECTION INPUT ;
  USE SIGNAL ;
  PORT
   LAYER M3 ;
   RECT 205.236000 544.282000 205.254000 544.320000 ;
  END
 END vi[172]
 PIN vi[173]
  DIRECTION INPUT ;
  USE SIGNAL ;
  PORT
   LAYER M5 ;
   RECT 206.256000 544.236000 206.280000 544.320000 ;
  END
 END vi[173]
 PIN vi[174]
  DIRECTION INPUT ;
  USE SIGNAL ;
  PORT
   LAYER M3 ;
   RECT 207.252000 544.282000 207.270000 544.320000 ;
  END
 END vi[174]
 PIN vi[175]
  DIRECTION INPUT ;
  USE SIGNAL ;
  PORT
   LAYER M5 ;
   RECT 208.272000 544.236000 208.296000 544.320000 ;
  END
 END vi[175]
 PIN vi[176]
  DIRECTION INPUT ;
  USE SIGNAL ;
  PORT
   LAYER M3 ;
   RECT 209.304000 544.282000 209.322000 544.320000 ;
  END
 END vi[176]
 PIN vi[177]
  DIRECTION INPUT ;
  USE SIGNAL ;
  PORT
   LAYER M5 ;
   RECT 210.336000 544.236000 210.360000 544.320000 ;
  END
 END vi[177]
 PIN vi[178]
  DIRECTION INPUT ;
  USE SIGNAL ;
  PORT
   LAYER M3 ;
   RECT 211.320000 544.282000 211.338000 544.320000 ;
  END
 END vi[178]
 PIN vi[179]
  DIRECTION INPUT ;
  USE SIGNAL ;
  PORT
   LAYER M5 ;
   RECT 212.352000 544.236000 212.376000 544.320000 ;
  END
 END vi[179]
 PIN vi[180]
  DIRECTION INPUT ;
  USE SIGNAL ;
  PORT
   LAYER M3 ;
   RECT 213.372000 544.282000 213.390000 544.320000 ;
  END
 END vi[180]
 PIN vi[181]
  DIRECTION INPUT ;
  USE SIGNAL ;
  PORT
   LAYER M5 ;
   RECT 214.368000 544.236000 214.392000 544.320000 ;
  END
 END vi[181]
 PIN vi[10]
  DIRECTION INPUT ;
  USE SIGNAL ;
  PORT
   LAYER M3 ;
   RECT 40.428000 544.282000 40.446000 544.320000 ;
  END
 END vi[10]
 PIN vi[182]
  DIRECTION INPUT ;
  USE SIGNAL ;
  PORT
   LAYER M3 ;
   RECT 215.388000 544.282000 215.406000 544.320000 ;
  END
 END vi[182]
 PIN vi[183]
  DIRECTION INPUT ;
  USE SIGNAL ;
  PORT
   LAYER M5 ;
   RECT 216.432000 544.236000 216.456000 544.320000 ;
  END
 END vi[183]
 PIN vi[184]
  DIRECTION INPUT ;
  USE SIGNAL ;
  PORT
   LAYER M3 ;
   RECT 217.440000 544.282000 217.458000 544.320000 ;
  END
 END vi[184]
 PIN vi[185]
  DIRECTION INPUT ;
  USE SIGNAL ;
  PORT
   LAYER M5 ;
   RECT 218.448000 544.236000 218.472000 544.320000 ;
  END
 END vi[185]
 PIN vi[186]
  DIRECTION INPUT ;
  USE SIGNAL ;
  PORT
   LAYER M3 ;
   RECT 219.492000 544.282000 219.510000 544.320000 ;
  END
 END vi[186]
 PIN vi[187]
  DIRECTION INPUT ;
  USE SIGNAL ;
  PORT
   LAYER M5 ;
   RECT 220.512000 544.236000 220.536000 544.320000 ;
  END
 END vi[187]
 PIN vi[188]
  DIRECTION INPUT ;
  USE SIGNAL ;
  PORT
   LAYER M3 ;
   RECT 221.508000 544.282000 221.526000 544.320000 ;
  END
 END vi[188]
 PIN vi[189]
  DIRECTION INPUT ;
  USE SIGNAL ;
  PORT
   LAYER M5 ;
   RECT 222.528000 544.236000 222.552000 544.320000 ;
  END
 END vi[189]
 PIN vi[190]
  DIRECTION INPUT ;
  USE SIGNAL ;
  PORT
   LAYER M3 ;
   RECT 223.560000 544.282000 223.578000 544.320000 ;
  END
 END vi[190]
 PIN vi[191]
  DIRECTION INPUT ;
  USE SIGNAL ;
  PORT
   LAYER M5 ;
   RECT 224.544000 544.236000 224.568000 544.320000 ;
  END
 END vi[191]
 PIN vi[11]
  DIRECTION INPUT ;
  USE SIGNAL ;
  PORT
   LAYER M5 ;
   RECT 41.424000 544.236000 41.448000 544.320000 ;
  END
 END vi[11]
 PIN vi[1]
  DIRECTION INPUT ;
  USE SIGNAL ;
  PORT
   LAYER M5 ;
   RECT 23.136000 544.236000 23.160000 544.320000 ;
  END
 END vi[1]
 PIN vi[192]
  DIRECTION INPUT ;
  USE SIGNAL ;
  PORT
   LAYER M3 ;
   RECT 225.576000 544.282000 225.594000 544.320000 ;
  END
 END vi[192]
 PIN vi[193]
  DIRECTION INPUT ;
  USE SIGNAL ;
  PORT
   LAYER M5 ;
   RECT 226.608000 544.236000 226.632000 544.320000 ;
  END
 END vi[193]
 PIN vi[194]
  DIRECTION INPUT ;
  USE SIGNAL ;
  PORT
   LAYER M3 ;
   RECT 227.628000 544.282000 227.646000 544.320000 ;
  END
 END vi[194]
 PIN vi[195]
  DIRECTION INPUT ;
  USE SIGNAL ;
  PORT
   LAYER M5 ;
   RECT 228.624000 544.236000 228.648000 544.320000 ;
  END
 END vi[195]
 PIN vi[196]
  DIRECTION INPUT ;
  USE SIGNAL ;
  PORT
   LAYER M3 ;
   RECT 229.644000 544.282000 229.662000 544.320000 ;
  END
 END vi[196]
 PIN vi[197]
  DIRECTION INPUT ;
  USE SIGNAL ;
  PORT
   LAYER M5 ;
   RECT 230.640000 544.236000 230.664000 544.320000 ;
  END
 END vi[197]
 PIN vi[198]
  DIRECTION INPUT ;
  USE SIGNAL ;
  PORT
   LAYER M3 ;
   RECT 231.696000 544.282000 231.714000 544.320000 ;
  END
 END vi[198]
 PIN vi[199]
  DIRECTION INPUT ;
  USE SIGNAL ;
  PORT
   LAYER M5 ;
   RECT 232.704000 544.236000 232.728000 544.320000 ;
  END
 END vi[199]
 PIN vi[200]
  DIRECTION INPUT ;
  USE SIGNAL ;
  PORT
   LAYER M3 ;
   RECT 233.712000 544.282000 233.730000 544.320000 ;
  END
 END vi[200]
 PIN vi[201]
  DIRECTION INPUT ;
  USE SIGNAL ;
  PORT
   LAYER M5 ;
   RECT 234.720000 544.236000 234.744000 544.320000 ;
  END
 END vi[201]
 PIN vi[12]
  DIRECTION INPUT ;
  USE SIGNAL ;
  PORT
   LAYER M3 ;
   RECT 42.444000 544.282000 42.462000 544.320000 ;
  END
 END vi[12]
 PIN vi[202]
  DIRECTION INPUT ;
  USE SIGNAL ;
  PORT
   LAYER M3 ;
   RECT 235.764000 544.282000 235.782000 544.320000 ;
  END
 END vi[202]
 PIN vi[203]
  DIRECTION INPUT ;
  USE SIGNAL ;
  PORT
   LAYER M5 ;
   RECT 236.784000 544.236000 236.808000 544.320000 ;
  END
 END vi[203]
 PIN vi[204]
  DIRECTION INPUT ;
  USE SIGNAL ;
  PORT
   LAYER M3 ;
   RECT 237.780000 544.282000 237.798000 544.320000 ;
  END
 END vi[204]
 PIN vi[205]
  DIRECTION INPUT ;
  USE SIGNAL ;
  PORT
   LAYER M5 ;
   RECT 238.800000 544.236000 238.824000 544.320000 ;
  END
 END vi[205]
 PIN vi[206]
  DIRECTION INPUT ;
  USE SIGNAL ;
  PORT
   LAYER M3 ;
   RECT 239.832000 544.282000 239.850000 544.320000 ;
  END
 END vi[206]
 PIN vi[207]
  DIRECTION INPUT ;
  USE SIGNAL ;
  PORT
   LAYER M5 ;
   RECT 240.336000 544.236000 240.360000 544.320000 ;
  END
 END vi[207]
 PIN vi[208]
  DIRECTION INPUT ;
  USE SIGNAL ;
  PORT
   LAYER M3 ;
   RECT 241.848000 544.282000 241.866000 544.320000 ;
  END
 END vi[208]
 PIN vi[209]
  DIRECTION INPUT ;
  USE SIGNAL ;
  PORT
   LAYER M5 ;
   RECT 242.880000 544.236000 242.904000 544.320000 ;
  END
 END vi[209]
 PIN vi[210]
  DIRECTION INPUT ;
  USE SIGNAL ;
  PORT
   LAYER M3 ;
   RECT 243.900000 544.282000 243.918000 544.320000 ;
  END
 END vi[210]
 PIN vi[211]
  DIRECTION INPUT ;
  USE SIGNAL ;
  PORT
   LAYER M5 ;
   RECT 244.896000 544.236000 244.920000 544.320000 ;
  END
 END vi[211]
 PIN vi[13]
  DIRECTION INPUT ;
  USE SIGNAL ;
  PORT
   LAYER M5 ;
   RECT 43.440000 544.236000 43.464000 544.320000 ;
  END
 END vi[13]
 PIN vi[212]
  DIRECTION INPUT ;
  USE SIGNAL ;
  PORT
   LAYER M3 ;
   RECT 245.916000 544.282000 245.934000 544.320000 ;
  END
 END vi[212]
 PIN vi[213]
  DIRECTION INPUT ;
  USE SIGNAL ;
  PORT
   LAYER M5 ;
   RECT 246.960000 544.236000 246.984000 544.320000 ;
  END
 END vi[213]
 PIN vi[214]
  DIRECTION INPUT ;
  USE SIGNAL ;
  PORT
   LAYER M3 ;
   RECT 247.968000 544.282000 247.986000 544.320000 ;
  END
 END vi[214]
 PIN vi[215]
  DIRECTION INPUT ;
  USE SIGNAL ;
  PORT
   LAYER M5 ;
   RECT 248.976000 544.236000 249.000000 544.320000 ;
  END
 END vi[215]
 PIN vi[216]
  DIRECTION INPUT ;
  USE SIGNAL ;
  PORT
   LAYER M3 ;
   RECT 249.984000 544.282000 250.002000 544.320000 ;
  END
 END vi[216]
 PIN vi[217]
  DIRECTION INPUT ;
  USE SIGNAL ;
  PORT
   LAYER M5 ;
   RECT 250.992000 544.236000 251.016000 544.320000 ;
  END
 END vi[217]
 PIN vi[218]
  DIRECTION INPUT ;
  USE SIGNAL ;
  PORT
   LAYER M3 ;
   RECT 252.036000 544.282000 252.054000 544.320000 ;
  END
 END vi[218]
 PIN vi[219]
  DIRECTION INPUT ;
  USE SIGNAL ;
  PORT
   LAYER M5 ;
   RECT 253.056000 544.236000 253.080000 544.320000 ;
  END
 END vi[219]
 PIN vi[220]
  DIRECTION INPUT ;
  USE SIGNAL ;
  PORT
   LAYER M3 ;
   RECT 254.052000 544.282000 254.070000 544.320000 ;
  END
 END vi[220]
 PIN vi[221]
  DIRECTION INPUT ;
  USE SIGNAL ;
  PORT
   LAYER M5 ;
   RECT 255.072000 544.236000 255.096000 544.320000 ;
  END
 END vi[221]
 PIN vi[14]
  DIRECTION INPUT ;
  USE SIGNAL ;
  PORT
   LAYER M3 ;
   RECT 44.496000 544.282000 44.514000 544.320000 ;
  END
 END vi[14]
 PIN vi[222]
  DIRECTION INPUT ;
  USE SIGNAL ;
  PORT
   LAYER M3 ;
   RECT 256.104000 544.282000 256.122000 544.320000 ;
  END
 END vi[222]
 PIN vi[223]
  DIRECTION INPUT ;
  USE SIGNAL ;
  PORT
   LAYER M5 ;
   RECT 257.136000 544.236000 257.160000 544.320000 ;
  END
 END vi[223]
 PIN vi[224]
  DIRECTION INPUT ;
  USE SIGNAL ;
  PORT
   LAYER M3 ;
   RECT 258.120000 544.282000 258.138000 544.320000 ;
  END
 END vi[224]
 PIN vi[225]
  DIRECTION INPUT ;
  USE SIGNAL ;
  PORT
   LAYER M5 ;
   RECT 259.152000 544.236000 259.176000 544.320000 ;
  END
 END vi[225]
 PIN vi[226]
  DIRECTION INPUT ;
  USE SIGNAL ;
  PORT
   LAYER M3 ;
   RECT 260.172000 544.282000 260.190000 544.320000 ;
  END
 END vi[226]
 PIN vi[227]
  DIRECTION INPUT ;
  USE SIGNAL ;
  PORT
   LAYER M5 ;
   RECT 261.168000 544.236000 261.192000 544.320000 ;
  END
 END vi[227]
 PIN vi[228]
  DIRECTION INPUT ;
  USE SIGNAL ;
  PORT
   LAYER M3 ;
   RECT 262.188000 544.282000 262.206000 544.320000 ;
  END
 END vi[228]
 PIN vi[229]
  DIRECTION INPUT ;
  USE SIGNAL ;
  PORT
   LAYER M5 ;
   RECT 263.232000 544.236000 263.256000 544.320000 ;
  END
 END vi[229]
 PIN vi[230]
  DIRECTION INPUT ;
  USE SIGNAL ;
  PORT
   LAYER M3 ;
   RECT 264.240000 544.282000 264.258000 544.320000 ;
  END
 END vi[230]
 PIN vi[231]
  DIRECTION INPUT ;
  USE SIGNAL ;
  PORT
   LAYER M5 ;
   RECT 265.248000 544.236000 265.272000 544.320000 ;
  END
 END vi[231]
 PIN vi[15]
  DIRECTION INPUT ;
  USE SIGNAL ;
  PORT
   LAYER M5 ;
   RECT 45.504000 544.236000 45.528000 544.320000 ;
  END
 END vi[15]
 PIN vi[232]
  DIRECTION INPUT ;
  USE SIGNAL ;
  PORT
   LAYER M3 ;
   RECT 266.292000 544.282000 266.310000 544.320000 ;
  END
 END vi[232]
 PIN vi[233]
  DIRECTION INPUT ;
  USE SIGNAL ;
  PORT
   LAYER M5 ;
   RECT 267.312000 544.236000 267.336000 544.320000 ;
  END
 END vi[233]
 PIN vi[234]
  DIRECTION INPUT ;
  USE SIGNAL ;
  PORT
   LAYER M3 ;
   RECT 268.308000 544.282000 268.326000 544.320000 ;
  END
 END vi[234]
 PIN vi[235]
  DIRECTION INPUT ;
  USE SIGNAL ;
  PORT
   LAYER M5 ;
   RECT 269.328000 544.236000 269.352000 544.320000 ;
  END
 END vi[235]
 PIN vi[236]
  DIRECTION INPUT ;
  USE SIGNAL ;
  PORT
   LAYER M3 ;
   RECT 270.360000 544.282000 270.378000 544.320000 ;
  END
 END vi[236]
 PIN vi[237]
  DIRECTION INPUT ;
  USE SIGNAL ;
  PORT
   LAYER M5 ;
   RECT 271.344000 544.236000 271.368000 544.320000 ;
  END
 END vi[237]
 PIN vi[238]
  DIRECTION INPUT ;
  USE SIGNAL ;
  PORT
   LAYER M3 ;
   RECT 272.376000 544.282000 272.394000 544.320000 ;
  END
 END vi[238]
 PIN vi[239]
  DIRECTION INPUT ;
  USE SIGNAL ;
  PORT
   LAYER M5 ;
   RECT 273.408000 544.236000 273.432000 544.320000 ;
  END
 END vi[239]
 PIN vi[240]
  DIRECTION INPUT ;
  USE SIGNAL ;
  PORT
   LAYER M3 ;
   RECT 274.428000 544.282000 274.446000 544.320000 ;
  END
 END vi[240]
 PIN vi[241]
  DIRECTION INPUT ;
  USE SIGNAL ;
  PORT
   LAYER M5 ;
   RECT 275.424000 544.236000 275.448000 544.320000 ;
  END
 END vi[241]
 PIN vi[16]
  DIRECTION INPUT ;
  USE SIGNAL ;
  PORT
   LAYER M3 ;
   RECT 46.512000 544.282000 46.530000 544.320000 ;
  END
 END vi[16]
 PIN vi[242]
  DIRECTION INPUT ;
  USE SIGNAL ;
  PORT
   LAYER M3 ;
   RECT 276.444000 544.282000 276.462000 544.320000 ;
  END
 END vi[242]
 PIN vi[243]
  DIRECTION INPUT ;
  USE SIGNAL ;
  PORT
   LAYER M5 ;
   RECT 277.440000 544.236000 277.464000 544.320000 ;
  END
 END vi[243]
 PIN vi[244]
  DIRECTION INPUT ;
  USE SIGNAL ;
  PORT
   LAYER M3 ;
   RECT 278.496000 544.282000 278.514000 544.320000 ;
  END
 END vi[244]
 PIN vi[245]
  DIRECTION INPUT ;
  USE SIGNAL ;
  PORT
   LAYER M5 ;
   RECT 279.504000 544.236000 279.528000 544.320000 ;
  END
 END vi[245]
 PIN vi[246]
  DIRECTION INPUT ;
  USE SIGNAL ;
  PORT
   LAYER M3 ;
   RECT 280.512000 544.282000 280.530000 544.320000 ;
  END
 END vi[246]
 PIN vi[247]
  DIRECTION INPUT ;
  USE SIGNAL ;
  PORT
   LAYER M5 ;
   RECT 281.520000 544.236000 281.544000 544.320000 ;
  END
 END vi[247]
 PIN vi[248]
  DIRECTION INPUT ;
  USE SIGNAL ;
  PORT
   LAYER M3 ;
   RECT 282.564000 544.282000 282.582000 544.320000 ;
  END
 END vi[248]
 PIN vi[249]
  DIRECTION INPUT ;
  USE SIGNAL ;
  PORT
   LAYER M5 ;
   RECT 283.584000 544.236000 283.608000 544.320000 ;
  END
 END vi[249]
 PIN vi[250]
  DIRECTION INPUT ;
  USE SIGNAL ;
  PORT
   LAYER M3 ;
   RECT 284.580000 544.282000 284.598000 544.320000 ;
  END
 END vi[250]
 PIN vi[251]
  DIRECTION INPUT ;
  USE SIGNAL ;
  PORT
   LAYER M5 ;
   RECT 285.600000 544.236000 285.624000 544.320000 ;
  END
 END vi[251]
 PIN vi[17]
  DIRECTION INPUT ;
  USE SIGNAL ;
  PORT
   LAYER M5 ;
   RECT 47.520000 544.236000 47.544000 544.320000 ;
  END
 END vi[17]
 PIN vi[252]
  DIRECTION INPUT ;
  USE SIGNAL ;
  PORT
   LAYER M3 ;
   RECT 286.632000 544.282000 286.650000 544.320000 ;
  END
 END vi[252]
 PIN vi[253]
  DIRECTION INPUT ;
  USE SIGNAL ;
  PORT
   LAYER M5 ;
   RECT 287.616000 544.236000 287.640000 544.320000 ;
  END
 END vi[253]
 PIN vi[254]
  DIRECTION INPUT ;
  USE SIGNAL ;
  PORT
   LAYER M3 ;
   RECT 288.648000 544.282000 288.666000 544.320000 ;
  END
 END vi[254]
 PIN vi[255]
  DIRECTION INPUT ;
  USE SIGNAL ;
  PORT
   LAYER M5 ;
   RECT 289.680000 544.236000 289.704000 544.320000 ;
  END
 END vi[255]
 PIN vi[256]
  DIRECTION INPUT ;
  USE SIGNAL ;
  PORT
   LAYER M3 ;
   RECT 290.700000 544.282000 290.718000 544.320000 ;
  END
 END vi[256]
 PIN vi[257]
  DIRECTION INPUT ;
  USE SIGNAL ;
  PORT
   LAYER M5 ;
   RECT 291.696000 544.236000 291.720000 544.320000 ;
  END
 END vi[257]
 PIN vi[258]
  DIRECTION INPUT ;
  USE SIGNAL ;
  PORT
   LAYER M3 ;
   RECT 292.716000 544.282000 292.734000 544.320000 ;
  END
 END vi[258]
 PIN vi[259]
  DIRECTION INPUT ;
  USE SIGNAL ;
  PORT
   LAYER M5 ;
   RECT 293.760000 544.236000 293.784000 544.320000 ;
  END
 END vi[259]
 PIN vi[260]
  DIRECTION INPUT ;
  USE SIGNAL ;
  PORT
   LAYER M3 ;
   RECT 294.768000 544.282000 294.786000 544.320000 ;
  END
 END vi[260]
 PIN vi[261]
  DIRECTION INPUT ;
  USE SIGNAL ;
  PORT
   LAYER M5 ;
   RECT 295.776000 544.236000 295.800000 544.320000 ;
  END
 END vi[261]
 PIN vi[18]
  DIRECTION INPUT ;
  USE SIGNAL ;
  PORT
   LAYER M3 ;
   RECT 48.564000 544.282000 48.582000 544.320000 ;
  END
 END vi[18]
 PIN vi[262]
  DIRECTION INPUT ;
  USE SIGNAL ;
  PORT
   LAYER M3 ;
   RECT 296.784000 544.282000 296.802000 544.320000 ;
  END
 END vi[262]
 PIN vi[263]
  DIRECTION INPUT ;
  USE SIGNAL ;
  PORT
   LAYER M5 ;
   RECT 297.792000 544.236000 297.816000 544.320000 ;
  END
 END vi[263]
 PIN vi[264]
  DIRECTION INPUT ;
  USE SIGNAL ;
  PORT
   LAYER M3 ;
   RECT 298.836000 544.282000 298.854000 544.320000 ;
  END
 END vi[264]
 PIN vi[265]
  DIRECTION INPUT ;
  USE SIGNAL ;
  PORT
   LAYER M5 ;
   RECT 299.856000 544.236000 299.880000 544.320000 ;
  END
 END vi[265]
 PIN vi[266]
  DIRECTION INPUT ;
  USE SIGNAL ;
  PORT
   LAYER M3 ;
   RECT 300.852000 544.282000 300.870000 544.320000 ;
  END
 END vi[266]
 PIN vi[267]
  DIRECTION INPUT ;
  USE SIGNAL ;
  PORT
   LAYER M5 ;
   RECT 301.872000 544.236000 301.896000 544.320000 ;
  END
 END vi[267]
 PIN vi[19]
  DIRECTION INPUT ;
  USE SIGNAL ;
  PORT
   LAYER M5 ;
   RECT 49.584000 544.236000 49.608000 544.320000 ;
  END
 END vi[19]
 PIN vi[20]
  DIRECTION INPUT ;
  USE SIGNAL ;
  PORT
   LAYER M3 ;
   RECT 50.580000 544.282000 50.598000 544.320000 ;
  END
 END vi[20]
 PIN vi[21]
  DIRECTION INPUT ;
  USE SIGNAL ;
  PORT
   LAYER M5 ;
   RECT 51.600000 544.236000 51.624000 544.320000 ;
  END
 END vi[21]
 PIN vi[2]
  DIRECTION INPUT ;
  USE SIGNAL ;
  PORT
   LAYER M3 ;
   RECT 24.120000 544.282000 24.138000 544.320000 ;
  END
 END vi[2]
 PIN vi[22]
  DIRECTION INPUT ;
  USE SIGNAL ;
  PORT
   LAYER M3 ;
   RECT 52.632000 544.282000 52.650000 544.320000 ;
  END
 END vi[22]
 PIN vi[23]
  DIRECTION INPUT ;
  USE SIGNAL ;
  PORT
   LAYER M5 ;
   RECT 53.616000 544.236000 53.640000 544.320000 ;
  END
 END vi[23]
 PIN vi[24]
  DIRECTION INPUT ;
  USE SIGNAL ;
  PORT
   LAYER M3 ;
   RECT 54.648000 544.282000 54.666000 544.320000 ;
  END
 END vi[24]
 PIN vi[25]
  DIRECTION INPUT ;
  USE SIGNAL ;
  PORT
   LAYER M5 ;
   RECT 55.680000 544.236000 55.704000 544.320000 ;
  END
 END vi[25]
 PIN vi[26]
  DIRECTION INPUT ;
  USE SIGNAL ;
  PORT
   LAYER M3 ;
   RECT 56.700000 544.282000 56.718000 544.320000 ;
  END
 END vi[26]
 PIN vi[27]
  DIRECTION INPUT ;
  USE SIGNAL ;
  PORT
   LAYER M5 ;
   RECT 57.696000 544.236000 57.720000 544.320000 ;
  END
 END vi[27]
 PIN vi[28]
  DIRECTION INPUT ;
  USE SIGNAL ;
  PORT
   LAYER M3 ;
   RECT 58.716000 544.282000 58.734000 544.320000 ;
  END
 END vi[28]
 PIN vi[29]
  DIRECTION INPUT ;
  USE SIGNAL ;
  PORT
   LAYER M5 ;
   RECT 59.760000 544.236000 59.784000 544.320000 ;
  END
 END vi[29]
 PIN vi[30]
  DIRECTION INPUT ;
  USE SIGNAL ;
  PORT
   LAYER M3 ;
   RECT 60.768000 544.282000 60.786000 544.320000 ;
  END
 END vi[30]
 PIN vi[31]
  DIRECTION INPUT ;
  USE SIGNAL ;
  PORT
   LAYER M5 ;
   RECT 61.776000 544.236000 61.800000 544.320000 ;
  END
 END vi[31]
 PIN vi[3]
  DIRECTION INPUT ;
  USE SIGNAL ;
  PORT
   LAYER M5 ;
   RECT 25.152000 544.236000 25.176000 544.320000 ;
  END
 END vi[3]
 PIN vi[32]
  DIRECTION INPUT ;
  USE SIGNAL ;
  PORT
   LAYER M3 ;
   RECT 62.784000 544.282000 62.802000 544.320000 ;
  END
 END vi[32]
 PIN vi[33]
  DIRECTION INPUT ;
  USE SIGNAL ;
  PORT
   LAYER M5 ;
   RECT 63.792000 544.236000 63.816000 544.320000 ;
  END
 END vi[33]
 PIN vi[34]
  DIRECTION INPUT ;
  USE SIGNAL ;
  PORT
   LAYER M3 ;
   RECT 64.836000 544.282000 64.854000 544.320000 ;
  END
 END vi[34]
 PIN vi[35]
  DIRECTION INPUT ;
  USE SIGNAL ;
  PORT
   LAYER M5 ;
   RECT 65.856000 544.236000 65.880000 544.320000 ;
  END
 END vi[35]
 PIN vi[36]
  DIRECTION INPUT ;
  USE SIGNAL ;
  PORT
   LAYER M3 ;
   RECT 66.852000 544.282000 66.870000 544.320000 ;
  END
 END vi[36]
 PIN vi[37]
  DIRECTION INPUT ;
  USE SIGNAL ;
  PORT
   LAYER M5 ;
   RECT 67.872000 544.236000 67.896000 544.320000 ;
  END
 END vi[37]
 PIN vi[38]
  DIRECTION INPUT ;
  USE SIGNAL ;
  PORT
   LAYER M3 ;
   RECT 68.904000 544.282000 68.922000 544.320000 ;
  END
 END vi[38]
 PIN vi[39]
  DIRECTION INPUT ;
  USE SIGNAL ;
  PORT
   LAYER M5 ;
   RECT 69.936000 544.236000 69.960000 544.320000 ;
  END
 END vi[39]
 PIN vi[40]
  DIRECTION INPUT ;
  USE SIGNAL ;
  PORT
   LAYER M3 ;
   RECT 70.920000 544.282000 70.938000 544.320000 ;
  END
 END vi[40]
 PIN vi[41]
  DIRECTION INPUT ;
  USE SIGNAL ;
  PORT
   LAYER M5 ;
   RECT 71.952000 544.236000 71.976000 544.320000 ;
  END
 END vi[41]
 PIN vi[4]
  DIRECTION INPUT ;
  USE SIGNAL ;
  PORT
   LAYER M3 ;
   RECT 26.172000 544.282000 26.190000 544.320000 ;
  END
 END vi[4]
 PIN vi[42]
  DIRECTION INPUT ;
  USE SIGNAL ;
  PORT
   LAYER M3 ;
   RECT 72.972000 544.282000 72.990000 544.320000 ;
  END
 END vi[42]
 PIN vi[43]
  DIRECTION INPUT ;
  USE SIGNAL ;
  PORT
   LAYER M5 ;
   RECT 73.968000 544.236000 73.992000 544.320000 ;
  END
 END vi[43]
 PIN vi[44]
  DIRECTION INPUT ;
  USE SIGNAL ;
  PORT
   LAYER M3 ;
   RECT 74.988000 544.282000 75.006000 544.320000 ;
  END
 END vi[44]
 PIN vi[45]
  DIRECTION INPUT ;
  USE SIGNAL ;
  PORT
   LAYER M5 ;
   RECT 76.032000 544.236000 76.056000 544.320000 ;
  END
 END vi[45]
 PIN vi[46]
  DIRECTION INPUT ;
  USE SIGNAL ;
  PORT
   LAYER M3 ;
   RECT 77.040000 544.282000 77.058000 544.320000 ;
  END
 END vi[46]
 PIN vi[47]
  DIRECTION INPUT ;
  USE SIGNAL ;
  PORT
   LAYER M5 ;
   RECT 78.048000 544.236000 78.072000 544.320000 ;
  END
 END vi[47]
 PIN vi[48]
  DIRECTION INPUT ;
  USE SIGNAL ;
  PORT
   LAYER M3 ;
   RECT 79.092000 544.282000 79.110000 544.320000 ;
  END
 END vi[48]
 PIN vi[49]
  DIRECTION INPUT ;
  USE SIGNAL ;
  PORT
   LAYER M5 ;
   RECT 80.112000 544.236000 80.136000 544.320000 ;
  END
 END vi[49]
 PIN vi[50]
  DIRECTION INPUT ;
  USE SIGNAL ;
  PORT
   LAYER M3 ;
   RECT 81.108000 544.282000 81.126000 544.320000 ;
  END
 END vi[50]
 PIN vi[51]
  DIRECTION INPUT ;
  USE SIGNAL ;
  PORT
   LAYER M5 ;
   RECT 82.128000 544.236000 82.152000 544.320000 ;
  END
 END vi[51]
 PIN vi[5]
  DIRECTION INPUT ;
  USE SIGNAL ;
  PORT
   LAYER M5 ;
   RECT 27.168000 544.236000 27.192000 544.320000 ;
  END
 END vi[5]
 PIN vi[52]
  DIRECTION INPUT ;
  USE SIGNAL ;
  PORT
   LAYER M3 ;
   RECT 83.160000 544.282000 83.178000 544.320000 ;
  END
 END vi[52]
 PIN vi[53]
  DIRECTION INPUT ;
  USE SIGNAL ;
  PORT
   LAYER M5 ;
   RECT 84.144000 544.236000 84.168000 544.320000 ;
  END
 END vi[53]
 PIN vi[54]
  DIRECTION INPUT ;
  USE SIGNAL ;
  PORT
   LAYER M3 ;
   RECT 85.176000 544.282000 85.194000 544.320000 ;
  END
 END vi[54]
 PIN vi[55]
  DIRECTION INPUT ;
  USE SIGNAL ;
  PORT
   LAYER M5 ;
   RECT 86.208000 544.236000 86.232000 544.320000 ;
  END
 END vi[55]
 PIN vi[56]
  DIRECTION INPUT ;
  USE SIGNAL ;
  PORT
   LAYER M3 ;
   RECT 87.228000 544.282000 87.246000 544.320000 ;
  END
 END vi[56]
 PIN vi[57]
  DIRECTION INPUT ;
  USE SIGNAL ;
  PORT
   LAYER M5 ;
   RECT 88.224000 544.236000 88.248000 544.320000 ;
  END
 END vi[57]
 PIN vi[58]
  DIRECTION INPUT ;
  USE SIGNAL ;
  PORT
   LAYER M3 ;
   RECT 89.244000 544.282000 89.262000 544.320000 ;
  END
 END vi[58]
 PIN vi[59]
  DIRECTION INPUT ;
  USE SIGNAL ;
  PORT
   LAYER M5 ;
   RECT 90.240000 544.236000 90.264000 544.320000 ;
  END
 END vi[59]
 PIN vi[60]
  DIRECTION INPUT ;
  USE SIGNAL ;
  PORT
   LAYER M3 ;
   RECT 91.296000 544.282000 91.314000 544.320000 ;
  END
 END vi[60]
 PIN vi[61]
  DIRECTION INPUT ;
  USE SIGNAL ;
  PORT
   LAYER M5 ;
   RECT 92.304000 544.236000 92.328000 544.320000 ;
  END
 END vi[61]
 PIN vi[6]
  DIRECTION INPUT ;
  USE SIGNAL ;
  PORT
   LAYER M3 ;
   RECT 28.188000 544.282000 28.206000 544.320000 ;
  END
 END vi[6]
 PIN vi[62]
  DIRECTION INPUT ;
  USE SIGNAL ;
  PORT
   LAYER M3 ;
   RECT 93.312000 544.282000 93.330000 544.320000 ;
  END
 END vi[62]
 PIN vi[63]
  DIRECTION INPUT ;
  USE SIGNAL ;
  PORT
   LAYER M5 ;
   RECT 94.320000 544.236000 94.344000 544.320000 ;
  END
 END vi[63]
 PIN vi[64]
  DIRECTION INPUT ;
  USE SIGNAL ;
  PORT
   LAYER M3 ;
   RECT 95.364000 544.282000 95.382000 544.320000 ;
  END
 END vi[64]
 PIN vi[65]
  DIRECTION INPUT ;
  USE SIGNAL ;
  PORT
   LAYER M5 ;
   RECT 96.384000 544.236000 96.408000 544.320000 ;
  END
 END vi[65]
 PIN vi[66]
  DIRECTION INPUT ;
  USE SIGNAL ;
  PORT
   LAYER M3 ;
   RECT 97.380000 544.282000 97.398000 544.320000 ;
  END
 END vi[66]
 PIN vi[67]
  DIRECTION INPUT ;
  USE SIGNAL ;
  PORT
   LAYER M5 ;
   RECT 98.400000 544.236000 98.424000 544.320000 ;
  END
 END vi[67]
 PIN vi[68]
  DIRECTION INPUT ;
  USE SIGNAL ;
  PORT
   LAYER M3 ;
   RECT 99.432000 544.282000 99.450000 544.320000 ;
  END
 END vi[68]
 PIN vi[69]
  DIRECTION INPUT ;
  USE SIGNAL ;
  PORT
   LAYER M5 ;
   RECT 100.416000 544.236000 100.440000 544.320000 ;
  END
 END vi[69]
 PIN vi[70]
  DIRECTION INPUT ;
  USE SIGNAL ;
  PORT
   LAYER M3 ;
   RECT 101.484000 544.282000 101.502000 544.320000 ;
  END
 END vi[70]
 PIN vi[71]
  DIRECTION INPUT ;
  USE SIGNAL ;
  PORT
   LAYER M5 ;
   RECT 102.480000 544.236000 102.504000 544.320000 ;
  END
 END vi[71]
 PIN vi[7]
  DIRECTION INPUT ;
  USE SIGNAL ;
  PORT
   LAYER M5 ;
   RECT 29.232000 544.236000 29.256000 544.320000 ;
  END
 END vi[7]
 PIN vi[72]
  DIRECTION INPUT ;
  USE SIGNAL ;
  PORT
   LAYER M3 ;
   RECT 103.500000 544.282000 103.518000 544.320000 ;
  END
 END vi[72]
 PIN vi[73]
  DIRECTION INPUT ;
  USE SIGNAL ;
  PORT
   LAYER M5 ;
   RECT 104.496000 544.236000 104.520000 544.320000 ;
  END
 END vi[73]
 PIN vi[74]
  DIRECTION INPUT ;
  USE SIGNAL ;
  PORT
   LAYER M3 ;
   RECT 105.516000 544.282000 105.534000 544.320000 ;
  END
 END vi[74]
 PIN vi[75]
  DIRECTION INPUT ;
  USE SIGNAL ;
  PORT
   LAYER M5 ;
   RECT 106.560000 544.236000 106.584000 544.320000 ;
  END
 END vi[75]
 PIN vi[76]
  DIRECTION INPUT ;
  USE SIGNAL ;
  PORT
   LAYER M3 ;
   RECT 107.568000 544.282000 107.586000 544.320000 ;
  END
 END vi[76]
 PIN vi[77]
  DIRECTION INPUT ;
  USE SIGNAL ;
  PORT
   LAYER M5 ;
   RECT 108.576000 544.236000 108.600000 544.320000 ;
  END
 END vi[77]
 PIN vi[78]
  DIRECTION INPUT ;
  USE SIGNAL ;
  PORT
   LAYER M3 ;
   RECT 109.584000 544.282000 109.602000 544.320000 ;
  END
 END vi[78]
 PIN vi[79]
  DIRECTION INPUT ;
  USE SIGNAL ;
  PORT
   LAYER M5 ;
   RECT 110.592000 544.236000 110.616000 544.320000 ;
  END
 END vi[79]
 PIN vi[80]
  DIRECTION INPUT ;
  USE SIGNAL ;
  PORT
   LAYER M3 ;
   RECT 111.636000 544.282000 111.654000 544.320000 ;
  END
 END vi[80]
 PIN vi[81]
  DIRECTION INPUT ;
  USE SIGNAL ;
  PORT
   LAYER M5 ;
   RECT 112.656000 544.236000 112.680000 544.320000 ;
  END
 END vi[81]
 PIN vi[82]
  DIRECTION INPUT ;
  USE SIGNAL ;
  PORT
   LAYER M3 ;
   RECT 113.652000 544.282000 113.670000 544.320000 ;
  END
 END vi[82]
 PIN vi[83]
  DIRECTION INPUT ;
  USE SIGNAL ;
  PORT
   LAYER M5 ;
   RECT 114.672000 544.236000 114.696000 544.320000 ;
  END
 END vi[83]
 PIN vi[84]
  DIRECTION INPUT ;
  USE SIGNAL ;
  PORT
   LAYER M3 ;
   RECT 115.704000 544.282000 115.722000 544.320000 ;
  END
 END vi[84]
 PIN vi[85]
  DIRECTION INPUT ;
  USE SIGNAL ;
  PORT
   LAYER M5 ;
   RECT 116.736000 544.236000 116.760000 544.320000 ;
  END
 END vi[85]
 PIN vi[86]
  DIRECTION INPUT ;
  USE SIGNAL ;
  PORT
   LAYER M3 ;
   RECT 117.720000 544.282000 117.738000 544.320000 ;
  END
 END vi[86]
 PIN vi[87]
  DIRECTION INPUT ;
  USE SIGNAL ;
  PORT
   LAYER M5 ;
   RECT 118.752000 544.236000 118.776000 544.320000 ;
  END
 END vi[87]
 PIN vi[88]
  DIRECTION INPUT ;
  USE SIGNAL ;
  PORT
   LAYER M3 ;
   RECT 119.772000 544.282000 119.790000 544.320000 ;
  END
 END vi[88]
 PIN vi[89]
  DIRECTION INPUT ;
  USE SIGNAL ;
  PORT
   LAYER M5 ;
   RECT 120.768000 544.236000 120.792000 544.320000 ;
  END
 END vi[89]
 PIN vi[90]
  DIRECTION INPUT ;
  USE SIGNAL ;
  PORT
   LAYER M3 ;
   RECT 121.788000 544.282000 121.806000 544.320000 ;
  END
 END vi[90]
 PIN vi[91]
  DIRECTION INPUT ;
  USE SIGNAL ;
  PORT
   LAYER M5 ;
   RECT 122.832000 544.236000 122.856000 544.320000 ;
  END
 END vi[91]
 PIN vo[0]
  DIRECTION INPUT ;
  USE SIGNAL ;
  PORT
   LAYER M3 ;
   RECT 324.468000 544.282000 324.486000 544.320000 ;
  END
 END vo[0]
 PIN vo[85]
  DIRECTION INPUT ;
  USE SIGNAL ;
  PORT
   LAYER M3 ;
   RECT 426.240000 544.282000 426.258000 544.320000 ;
  END
 END vo[85]
 PIN vo[86]
  DIRECTION INPUT ;
  USE SIGNAL ;
  PORT
   LAYER M5 ;
   RECT 427.248000 544.236000 427.272000 544.320000 ;
  END
 END vo[86]
 PIN vo[87]
  DIRECTION INPUT ;
  USE SIGNAL ;
  PORT
   LAYER M3 ;
   RECT 428.292000 544.282000 428.310000 544.320000 ;
  END
 END vo[87]
 PIN vo[88]
  DIRECTION INPUT ;
  USE SIGNAL ;
  PORT
   LAYER M5 ;
   RECT 429.312000 544.236000 429.336000 544.320000 ;
  END
 END vo[88]
 PIN vo[89]
  DIRECTION INPUT ;
  USE SIGNAL ;
  PORT
   LAYER M3 ;
   RECT 430.308000 544.282000 430.326000 544.320000 ;
  END
 END vo[89]
 PIN vo[90]
  DIRECTION INPUT ;
  USE SIGNAL ;
  PORT
   LAYER M5 ;
   RECT 431.328000 544.236000 431.352000 544.320000 ;
  END
 END vo[90]
 PIN vo[91]
  DIRECTION INPUT ;
  USE SIGNAL ;
  PORT
   LAYER M3 ;
   RECT 432.360000 544.282000 432.378000 544.320000 ;
  END
 END vo[91]
 PIN vo[92]
  DIRECTION INPUT ;
  USE SIGNAL ;
  PORT
   LAYER M5 ;
   RECT 433.344000 544.236000 433.368000 544.320000 ;
  END
 END vo[92]
 PIN vo[93]
  DIRECTION INPUT ;
  USE SIGNAL ;
  PORT
   LAYER M3 ;
   RECT 434.376000 544.282000 434.394000 544.320000 ;
  END
 END vo[93]
 PIN vo[94]
  DIRECTION INPUT ;
  USE SIGNAL ;
  PORT
   LAYER M5 ;
   RECT 435.408000 544.236000 435.432000 544.320000 ;
  END
 END vo[94]
 PIN vo[95]
  DIRECTION INPUT ;
  USE SIGNAL ;
  PORT
   LAYER M3 ;
   RECT 436.428000 544.282000 436.446000 544.320000 ;
  END
 END vo[95]
 PIN vo[96]
  DIRECTION INPUT ;
  USE SIGNAL ;
  PORT
   LAYER M5 ;
   RECT 437.424000 544.236000 437.448000 544.320000 ;
  END
 END vo[96]
 PIN vo[97]
  DIRECTION INPUT ;
  USE SIGNAL ;
  PORT
   LAYER M3 ;
   RECT 438.444000 544.282000 438.462000 544.320000 ;
  END
 END vo[97]
 PIN vo[98]
  DIRECTION INPUT ;
  USE SIGNAL ;
  PORT
   LAYER M5 ;
   RECT 439.440000 544.236000 439.464000 544.320000 ;
  END
 END vo[98]
 PIN vo[99]
  DIRECTION INPUT ;
  USE SIGNAL ;
  PORT
   LAYER M3 ;
   RECT 440.496000 544.282000 440.514000 544.320000 ;
  END
 END vo[99]
 PIN vo[100]
  DIRECTION INPUT ;
  USE SIGNAL ;
  PORT
   LAYER M5 ;
   RECT 441.504000 544.236000 441.528000 544.320000 ;
  END
 END vo[100]
 PIN vo[101]
  DIRECTION INPUT ;
  USE SIGNAL ;
  PORT
   LAYER M3 ;
   RECT 442.512000 544.282000 442.530000 544.320000 ;
  END
 END vo[101]
 PIN vo[102]
  DIRECTION INPUT ;
  USE SIGNAL ;
  PORT
   LAYER M5 ;
   RECT 443.520000 544.236000 443.544000 544.320000 ;
  END
 END vo[102]
 PIN vo[103]
  DIRECTION INPUT ;
  USE SIGNAL ;
  PORT
   LAYER M3 ;
   RECT 444.564000 544.282000 444.582000 544.320000 ;
  END
 END vo[103]
 PIN vo[104]
  DIRECTION INPUT ;
  USE SIGNAL ;
  PORT
   LAYER M5 ;
   RECT 445.584000 544.236000 445.608000 544.320000 ;
  END
 END vo[104]
 PIN vo[105]
  DIRECTION INPUT ;
  USE SIGNAL ;
  PORT
   LAYER M3 ;
   RECT 446.580000 544.282000 446.598000 544.320000 ;
  END
 END vo[105]
 PIN vo[106]
  DIRECTION INPUT ;
  USE SIGNAL ;
  PORT
   LAYER M5 ;
   RECT 447.600000 544.236000 447.624000 544.320000 ;
  END
 END vo[106]
 PIN vo[107]
  DIRECTION INPUT ;
  USE SIGNAL ;
  PORT
   LAYER M3 ;
   RECT 448.632000 544.282000 448.650000 544.320000 ;
  END
 END vo[107]
 PIN vo[108]
  DIRECTION INPUT ;
  USE SIGNAL ;
  PORT
   LAYER M5 ;
   RECT 449.616000 544.236000 449.640000 544.320000 ;
  END
 END vo[108]
 PIN vo[109]
  DIRECTION INPUT ;
  USE SIGNAL ;
  PORT
   LAYER M3 ;
   RECT 450.648000 544.282000 450.666000 544.320000 ;
  END
 END vo[109]
 PIN vo[110]
  DIRECTION INPUT ;
  USE SIGNAL ;
  PORT
   LAYER M5 ;
   RECT 451.680000 544.236000 451.704000 544.320000 ;
  END
 END vo[110]
 PIN vo[111]
  DIRECTION INPUT ;
  USE SIGNAL ;
  PORT
   LAYER M3 ;
   RECT 452.700000 544.282000 452.718000 544.320000 ;
  END
 END vo[111]
 PIN vo[112]
  DIRECTION INPUT ;
  USE SIGNAL ;
  PORT
   LAYER M5 ;
   RECT 453.696000 544.236000 453.720000 544.320000 ;
  END
 END vo[112]
 PIN vo[113]
  DIRECTION INPUT ;
  USE SIGNAL ;
  PORT
   LAYER M3 ;
   RECT 454.716000 544.282000 454.734000 544.320000 ;
  END
 END vo[113]
 PIN vo[114]
  DIRECTION INPUT ;
  USE SIGNAL ;
  PORT
   LAYER M5 ;
   RECT 455.760000 544.236000 455.784000 544.320000 ;
  END
 END vo[114]
 PIN vo[115]
  DIRECTION INPUT ;
  USE SIGNAL ;
  PORT
   LAYER M3 ;
   RECT 456.768000 544.282000 456.786000 544.320000 ;
  END
 END vo[115]
 PIN vo[116]
  DIRECTION INPUT ;
  USE SIGNAL ;
  PORT
   LAYER M5 ;
   RECT 457.776000 544.236000 457.800000 544.320000 ;
  END
 END vo[116]
 PIN vo[117]
  DIRECTION INPUT ;
  USE SIGNAL ;
  PORT
   LAYER M3 ;
   RECT 458.784000 544.282000 458.802000 544.320000 ;
  END
 END vo[117]
 PIN vo[118]
  DIRECTION INPUT ;
  USE SIGNAL ;
  PORT
   LAYER M5 ;
   RECT 459.792000 544.236000 459.816000 544.320000 ;
  END
 END vo[118]
 PIN vo[119]
  DIRECTION INPUT ;
  USE SIGNAL ;
  PORT
   LAYER M3 ;
   RECT 460.836000 544.282000 460.854000 544.320000 ;
  END
 END vo[119]
 PIN vo[120]
  DIRECTION INPUT ;
  USE SIGNAL ;
  PORT
   LAYER M5 ;
   RECT 461.856000 544.236000 461.880000 544.320000 ;
  END
 END vo[120]
 PIN vo[121]
  DIRECTION INPUT ;
  USE SIGNAL ;
  PORT
   LAYER M3 ;
   RECT 462.852000 544.282000 462.870000 544.320000 ;
  END
 END vo[121]
 PIN vo[122]
  DIRECTION INPUT ;
  USE SIGNAL ;
  PORT
   LAYER M5 ;
   RECT 463.872000 544.236000 463.896000 544.320000 ;
  END
 END vo[122]
 PIN vo[123]
  DIRECTION INPUT ;
  USE SIGNAL ;
  PORT
   LAYER M3 ;
   RECT 464.904000 544.282000 464.922000 544.320000 ;
  END
 END vo[123]
 PIN vo[124]
  DIRECTION INPUT ;
  USE SIGNAL ;
  PORT
   LAYER M5 ;
   RECT 466.368000 544.236000 466.392000 544.320000 ;
  END
 END vo[124]
 PIN vo[125]
  DIRECTION INPUT ;
  USE SIGNAL ;
  PORT
   LAYER M3 ;
   RECT 466.920000 544.282000 466.938000 544.320000 ;
  END
 END vo[125]
 PIN vo[126]
  DIRECTION INPUT ;
  USE SIGNAL ;
  PORT
   LAYER M5 ;
   RECT 467.952000 544.236000 467.976000 544.320000 ;
  END
 END vo[126]
 PIN vo[127]
  DIRECTION INPUT ;
  USE SIGNAL ;
  PORT
   LAYER M3 ;
   RECT 468.972000 544.282000 468.990000 544.320000 ;
  END
 END vo[127]
 PIN vo[128]
  DIRECTION INPUT ;
  USE SIGNAL ;
  PORT
   LAYER M5 ;
   RECT 469.968000 544.236000 469.992000 544.320000 ;
  END
 END vo[128]
 PIN vo[129]
  DIRECTION INPUT ;
  USE SIGNAL ;
  PORT
   LAYER M3 ;
   RECT 470.988000 544.282000 471.006000 544.320000 ;
  END
 END vo[129]
 PIN vo[130]
  DIRECTION INPUT ;
  USE SIGNAL ;
  PORT
   LAYER M5 ;
   RECT 472.032000 544.236000 472.056000 544.320000 ;
  END
 END vo[130]
 PIN vo[131]
  DIRECTION INPUT ;
  USE SIGNAL ;
  PORT
   LAYER M3 ;
   RECT 473.040000 544.282000 473.058000 544.320000 ;
  END
 END vo[131]
 PIN vo[132]
  DIRECTION INPUT ;
  USE SIGNAL ;
  PORT
   LAYER M5 ;
   RECT 474.048000 544.236000 474.072000 544.320000 ;
  END
 END vo[132]
 PIN vo[133]
  DIRECTION INPUT ;
  USE SIGNAL ;
  PORT
   LAYER M3 ;
   RECT 475.092000 544.282000 475.110000 544.320000 ;
  END
 END vo[133]
 PIN vo[134]
  DIRECTION INPUT ;
  USE SIGNAL ;
  PORT
   LAYER M5 ;
   RECT 476.112000 544.236000 476.136000 544.320000 ;
  END
 END vo[134]
 PIN vo[135]
  DIRECTION INPUT ;
  USE SIGNAL ;
  PORT
   LAYER M3 ;
   RECT 477.108000 544.282000 477.126000 544.320000 ;
  END
 END vo[135]
 PIN vo[136]
  DIRECTION INPUT ;
  USE SIGNAL ;
  PORT
   LAYER M5 ;
   RECT 478.128000 544.236000 478.152000 544.320000 ;
  END
 END vo[136]
 PIN vo[137]
  DIRECTION INPUT ;
  USE SIGNAL ;
  PORT
   LAYER M3 ;
   RECT 479.160000 544.282000 479.178000 544.320000 ;
  END
 END vo[137]
 PIN vo[138]
  DIRECTION INPUT ;
  USE SIGNAL ;
  PORT
   LAYER M5 ;
   RECT 480.144000 544.236000 480.168000 544.320000 ;
  END
 END vo[138]
 PIN vo[139]
  DIRECTION INPUT ;
  USE SIGNAL ;
  PORT
   LAYER M3 ;
   RECT 481.176000 544.282000 481.194000 544.320000 ;
  END
 END vo[139]
 PIN vo[140]
  DIRECTION INPUT ;
  USE SIGNAL ;
  PORT
   LAYER M5 ;
   RECT 482.208000 544.236000 482.232000 544.320000 ;
  END
 END vo[140]
 PIN vo[141]
  DIRECTION INPUT ;
  USE SIGNAL ;
  PORT
   LAYER M3 ;
   RECT 483.228000 544.282000 483.246000 544.320000 ;
  END
 END vo[141]
 PIN vo[142]
  DIRECTION INPUT ;
  USE SIGNAL ;
  PORT
   LAYER M5 ;
   RECT 484.224000 544.236000 484.248000 544.320000 ;
  END
 END vo[142]
 PIN vo[143]
  DIRECTION INPUT ;
  USE SIGNAL ;
  PORT
   LAYER M3 ;
   RECT 485.244000 544.282000 485.262000 544.320000 ;
  END
 END vo[143]
 PIN vo[144]
  DIRECTION INPUT ;
  USE SIGNAL ;
  PORT
   LAYER M5 ;
   RECT 486.240000 544.236000 486.264000 544.320000 ;
  END
 END vo[144]
 PIN vo[145]
  DIRECTION INPUT ;
  USE SIGNAL ;
  PORT
   LAYER M3 ;
   RECT 487.296000 544.282000 487.314000 544.320000 ;
  END
 END vo[145]
 PIN vo[146]
  DIRECTION INPUT ;
  USE SIGNAL ;
  PORT
   LAYER M5 ;
   RECT 488.304000 544.236000 488.328000 544.320000 ;
  END
 END vo[146]
 PIN vo[147]
  DIRECTION INPUT ;
  USE SIGNAL ;
  PORT
   LAYER M3 ;
   RECT 489.312000 544.282000 489.330000 544.320000 ;
  END
 END vo[147]
 PIN vo[148]
  DIRECTION INPUT ;
  USE SIGNAL ;
  PORT
   LAYER M5 ;
   RECT 490.320000 544.236000 490.344000 544.320000 ;
  END
 END vo[148]
 PIN vo[149]
  DIRECTION INPUT ;
  USE SIGNAL ;
  PORT
   LAYER M3 ;
   RECT 491.364000 544.282000 491.382000 544.320000 ;
  END
 END vo[149]
 PIN vo[150]
  DIRECTION INPUT ;
  USE SIGNAL ;
  PORT
   LAYER M5 ;
   RECT 492.384000 544.236000 492.408000 544.320000 ;
  END
 END vo[150]
 PIN vo[151]
  DIRECTION INPUT ;
  USE SIGNAL ;
  PORT
   LAYER M3 ;
   RECT 493.380000 544.282000 493.398000 544.320000 ;
  END
 END vo[151]
 PIN vo[152]
  DIRECTION INPUT ;
  USE SIGNAL ;
  PORT
   LAYER M5 ;
   RECT 494.400000 544.236000 494.424000 544.320000 ;
  END
 END vo[152]
 PIN vo[153]
  DIRECTION INPUT ;
  USE SIGNAL ;
  PORT
   LAYER M3 ;
   RECT 495.432000 544.282000 495.450000 544.320000 ;
  END
 END vo[153]
 PIN vo[154]
  DIRECTION INPUT ;
  USE SIGNAL ;
  PORT
   LAYER M5 ;
   RECT 496.416000 544.236000 496.440000 544.320000 ;
  END
 END vo[154]
 PIN vo[155]
  DIRECTION INPUT ;
  USE SIGNAL ;
  PORT
   LAYER M3 ;
   RECT 497.448000 544.282000 497.466000 544.320000 ;
  END
 END vo[155]
 PIN vo[156]
  DIRECTION INPUT ;
  USE SIGNAL ;
  PORT
   LAYER M5 ;
   RECT 498.480000 544.236000 498.504000 544.320000 ;
  END
 END vo[156]
 PIN vo[157]
  DIRECTION INPUT ;
  USE SIGNAL ;
  PORT
   LAYER M3 ;
   RECT 499.500000 544.282000 499.518000 544.320000 ;
  END
 END vo[157]
 PIN vo[158]
  DIRECTION INPUT ;
  USE SIGNAL ;
  PORT
   LAYER M5 ;
   RECT 500.496000 544.236000 500.520000 544.320000 ;
  END
 END vo[158]
 PIN vo[159]
  DIRECTION INPUT ;
  USE SIGNAL ;
  PORT
   LAYER M3 ;
   RECT 501.516000 544.282000 501.534000 544.320000 ;
  END
 END vo[159]
 PIN vo[160]
  DIRECTION INPUT ;
  USE SIGNAL ;
  PORT
   LAYER M5 ;
   RECT 502.560000 544.236000 502.584000 544.320000 ;
  END
 END vo[160]
 PIN vo[161]
  DIRECTION INPUT ;
  USE SIGNAL ;
  PORT
   LAYER M3 ;
   RECT 503.568000 544.282000 503.586000 544.320000 ;
  END
 END vo[161]
 PIN vo[162]
  DIRECTION INPUT ;
  USE SIGNAL ;
  PORT
   LAYER M5 ;
   RECT 504.576000 544.236000 504.600000 544.320000 ;
  END
 END vo[162]
 PIN vo[163]
  DIRECTION INPUT ;
  USE SIGNAL ;
  PORT
   LAYER M3 ;
   RECT 505.584000 544.282000 505.602000 544.320000 ;
  END
 END vo[163]
 PIN vo[164]
  DIRECTION INPUT ;
  USE SIGNAL ;
  PORT
   LAYER M5 ;
   RECT 506.592000 544.236000 506.616000 544.320000 ;
  END
 END vo[164]
 PIN vo[165]
  DIRECTION INPUT ;
  USE SIGNAL ;
  PORT
   LAYER M3 ;
   RECT 507.636000 544.282000 507.654000 544.320000 ;
  END
 END vo[165]
 PIN vo[166]
  DIRECTION INPUT ;
  USE SIGNAL ;
  PORT
   LAYER M5 ;
   RECT 508.656000 544.236000 508.680000 544.320000 ;
  END
 END vo[166]
 PIN vo[167]
  DIRECTION INPUT ;
  USE SIGNAL ;
  PORT
   LAYER M3 ;
   RECT 509.652000 544.282000 509.670000 544.320000 ;
  END
 END vo[167]
 PIN vo[168]
  DIRECTION INPUT ;
  USE SIGNAL ;
  PORT
   LAYER M5 ;
   RECT 510.672000 544.236000 510.696000 544.320000 ;
  END
 END vo[168]
 PIN vo[169]
  DIRECTION INPUT ;
  USE SIGNAL ;
  PORT
   LAYER M3 ;
   RECT 511.704000 544.282000 511.722000 544.320000 ;
  END
 END vo[169]
 PIN vo[170]
  DIRECTION INPUT ;
  USE SIGNAL ;
  PORT
   LAYER M5 ;
   RECT 512.736000 544.236000 512.760000 544.320000 ;
  END
 END vo[170]
 PIN vo[171]
  DIRECTION INPUT ;
  USE SIGNAL ;
  PORT
   LAYER M3 ;
   RECT 513.720000 544.282000 513.738000 544.320000 ;
  END
 END vo[171]
 PIN vo[172]
  DIRECTION INPUT ;
  USE SIGNAL ;
  PORT
   LAYER M5 ;
   RECT 514.752000 544.236000 514.776000 544.320000 ;
  END
 END vo[172]
 PIN vo[173]
  DIRECTION INPUT ;
  USE SIGNAL ;
  PORT
   LAYER M3 ;
   RECT 515.772000 544.282000 515.790000 544.320000 ;
  END
 END vo[173]
 PIN vo[174]
  DIRECTION INPUT ;
  USE SIGNAL ;
  PORT
   LAYER M5 ;
   RECT 516.768000 544.236000 516.792000 544.320000 ;
  END
 END vo[174]
 PIN vo[175]
  DIRECTION INPUT ;
  USE SIGNAL ;
  PORT
   LAYER M3 ;
   RECT 517.788000 544.282000 517.806000 544.320000 ;
  END
 END vo[175]
 PIN vo[176]
  DIRECTION INPUT ;
  USE SIGNAL ;
  PORT
   LAYER M5 ;
   RECT 518.832000 544.236000 518.856000 544.320000 ;
  END
 END vo[176]
 PIN vo[177]
  DIRECTION INPUT ;
  USE SIGNAL ;
  PORT
   LAYER M3 ;
   RECT 519.840000 544.282000 519.858000 544.320000 ;
  END
 END vo[177]
 PIN vo[178]
  DIRECTION INPUT ;
  USE SIGNAL ;
  PORT
   LAYER M5 ;
   RECT 520.848000 544.236000 520.872000 544.320000 ;
  END
 END vo[178]
 PIN vo[179]
  DIRECTION INPUT ;
  USE SIGNAL ;
  PORT
   LAYER M3 ;
   RECT 521.892000 544.282000 521.910000 544.320000 ;
  END
 END vo[179]
 PIN vo[180]
  DIRECTION INPUT ;
  USE SIGNAL ;
  PORT
   LAYER M5 ;
   RECT 522.912000 544.236000 522.936000 544.320000 ;
  END
 END vo[180]
 PIN vo[181]
  DIRECTION INPUT ;
  USE SIGNAL ;
  PORT
   LAYER M3 ;
   RECT 523.908000 544.282000 523.926000 544.320000 ;
  END
 END vo[181]
 PIN vo[182]
  DIRECTION INPUT ;
  USE SIGNAL ;
  PORT
   LAYER M5 ;
   RECT 524.928000 544.236000 524.952000 544.320000 ;
  END
 END vo[182]
 PIN vo[183]
  DIRECTION INPUT ;
  USE SIGNAL ;
  PORT
   LAYER M3 ;
   RECT 525.960000 544.282000 525.978000 544.320000 ;
  END
 END vo[183]
 PIN vo[184]
  DIRECTION INPUT ;
  USE SIGNAL ;
  PORT
   LAYER M5 ;
   RECT 526.464000 544.236000 526.488000 544.320000 ;
  END
 END vo[184]
 PIN vo[1]
  DIRECTION INPUT ;
  USE SIGNAL ;
  PORT
   LAYER M5 ;
   RECT 325.536000 544.236000 325.560000 544.320000 ;
  END
 END vo[1]
 PIN vo[185]
  DIRECTION INPUT ;
  USE SIGNAL ;
  PORT
   LAYER M3 ;
   RECT 527.976000 544.282000 527.994000 544.320000 ;
  END
 END vo[185]
 PIN vo[186]
  DIRECTION INPUT ;
  USE SIGNAL ;
  PORT
   LAYER M5 ;
   RECT 529.008000 544.236000 529.032000 544.320000 ;
  END
 END vo[186]
 PIN vo[187]
  DIRECTION INPUT ;
  USE SIGNAL ;
  PORT
   LAYER M3 ;
   RECT 530.028000 544.282000 530.046000 544.320000 ;
  END
 END vo[187]
 PIN vo[188]
  DIRECTION INPUT ;
  USE SIGNAL ;
  PORT
   LAYER M5 ;
   RECT 531.024000 544.236000 531.048000 544.320000 ;
  END
 END vo[188]
 PIN vo[189]
  DIRECTION INPUT ;
  USE SIGNAL ;
  PORT
   LAYER M3 ;
   RECT 532.044000 544.282000 532.062000 544.320000 ;
  END
 END vo[189]
 PIN vo[190]
  DIRECTION INPUT ;
  USE SIGNAL ;
  PORT
   LAYER M5 ;
   RECT 533.040000 544.236000 533.064000 544.320000 ;
  END
 END vo[190]
 PIN vo[191]
  DIRECTION INPUT ;
  USE SIGNAL ;
  PORT
   LAYER M3 ;
   RECT 534.096000 544.282000 534.114000 544.320000 ;
  END
 END vo[191]
 PIN vo[192]
  DIRECTION INPUT ;
  USE SIGNAL ;
  PORT
   LAYER M5 ;
   RECT 535.104000 544.236000 535.128000 544.320000 ;
  END
 END vo[192]
 PIN vo[193]
  DIRECTION INPUT ;
  USE SIGNAL ;
  PORT
   LAYER M3 ;
   RECT 536.112000 544.282000 536.130000 544.320000 ;
  END
 END vo[193]
 PIN vo[194]
  DIRECTION INPUT ;
  USE SIGNAL ;
  PORT
   LAYER M5 ;
   RECT 537.120000 544.236000 537.144000 544.320000 ;
  END
 END vo[194]
 PIN vo[5]
  DIRECTION INPUT ;
  USE SIGNAL ;
  PORT
   LAYER M3 ;
   RECT 344.844000 544.282000 344.862000 544.320000 ;
  END
 END vo[5]
 PIN vo[195]
  DIRECTION INPUT ;
  USE SIGNAL ;
  PORT
   LAYER M3 ;
   RECT 538.164000 544.282000 538.182000 544.320000 ;
  END
 END vo[195]
 PIN vo[196]
  DIRECTION INPUT ;
  USE SIGNAL ;
  PORT
   LAYER M5 ;
   RECT 539.184000 544.236000 539.208000 544.320000 ;
  END
 END vo[196]
 PIN vo[197]
  DIRECTION INPUT ;
  USE SIGNAL ;
  PORT
   LAYER M3 ;
   RECT 540.180000 544.282000 540.198000 544.320000 ;
  END
 END vo[197]
 PIN vo[198]
  DIRECTION INPUT ;
  USE SIGNAL ;
  PORT
   LAYER M5 ;
   RECT 541.200000 544.236000 541.224000 544.320000 ;
  END
 END vo[198]
 PIN vo[199]
  DIRECTION INPUT ;
  USE SIGNAL ;
  PORT
   LAYER M3 ;
   RECT 542.232000 544.282000 542.250000 544.320000 ;
  END
 END vo[199]
 PIN vo[200]
  DIRECTION INPUT ;
  USE SIGNAL ;
  PORT
   LAYER M5 ;
   RECT 543.216000 544.236000 543.240000 544.320000 ;
  END
 END vo[200]
 PIN vo[201]
  DIRECTION INPUT ;
  USE SIGNAL ;
  PORT
   LAYER M3 ;
   RECT 544.248000 544.282000 544.266000 544.320000 ;
  END
 END vo[201]
 PIN vo[202]
  DIRECTION INPUT ;
  USE SIGNAL ;
  PORT
   LAYER M5 ;
   RECT 545.280000 544.236000 545.304000 544.320000 ;
  END
 END vo[202]
 PIN vo[203]
  DIRECTION INPUT ;
  USE SIGNAL ;
  PORT
   LAYER M3 ;
   RECT 546.300000 544.282000 546.318000 544.320000 ;
  END
 END vo[203]
 PIN vo[204]
  DIRECTION INPUT ;
  USE SIGNAL ;
  PORT
   LAYER M5 ;
   RECT 547.296000 544.236000 547.320000 544.320000 ;
  END
 END vo[204]
 PIN vo[6]
  DIRECTION INPUT ;
  USE SIGNAL ;
  PORT
   LAYER M5 ;
   RECT 345.840000 544.236000 345.864000 544.320000 ;
  END
 END vo[6]
 PIN vo[205]
  DIRECTION INPUT ;
  USE SIGNAL ;
  PORT
   LAYER M3 ;
   RECT 548.316000 544.282000 548.334000 544.320000 ;
  END
 END vo[205]
 PIN vo[206]
  DIRECTION INPUT ;
  USE SIGNAL ;
  PORT
   LAYER M5 ;
   RECT 549.360000 544.236000 549.384000 544.320000 ;
  END
 END vo[206]
 PIN vo[207]
  DIRECTION INPUT ;
  USE SIGNAL ;
  PORT
   LAYER M3 ;
   RECT 550.368000 544.282000 550.386000 544.320000 ;
  END
 END vo[207]
 PIN vo[208]
  DIRECTION INPUT ;
  USE SIGNAL ;
  PORT
   LAYER M5 ;
   RECT 551.376000 544.236000 551.400000 544.320000 ;
  END
 END vo[208]
 PIN vo[209]
  DIRECTION INPUT ;
  USE SIGNAL ;
  PORT
   LAYER M3 ;
   RECT 552.384000 544.282000 552.402000 544.320000 ;
  END
 END vo[209]
 PIN vo[210]
  DIRECTION INPUT ;
  USE SIGNAL ;
  PORT
   LAYER M5 ;
   RECT 553.392000 544.236000 553.416000 544.320000 ;
  END
 END vo[210]
 PIN vo[211]
  DIRECTION INPUT ;
  USE SIGNAL ;
  PORT
   LAYER M3 ;
   RECT 554.436000 544.282000 554.454000 544.320000 ;
  END
 END vo[211]
 PIN vo[212]
  DIRECTION INPUT ;
  USE SIGNAL ;
  PORT
   LAYER M5 ;
   RECT 555.456000 544.236000 555.480000 544.320000 ;
  END
 END vo[212]
 PIN vo[213]
  DIRECTION INPUT ;
  USE SIGNAL ;
  PORT
   LAYER M3 ;
   RECT 556.452000 544.282000 556.470000 544.320000 ;
  END
 END vo[213]
 PIN vo[214]
  DIRECTION INPUT ;
  USE SIGNAL ;
  PORT
   LAYER M5 ;
   RECT 557.472000 544.236000 557.496000 544.320000 ;
  END
 END vo[214]
 PIN vo[7]
  DIRECTION INPUT ;
  USE SIGNAL ;
  PORT
   LAYER M3 ;
   RECT 346.896000 544.282000 346.914000 544.320000 ;
  END
 END vo[7]
 PIN vo[215]
  DIRECTION INPUT ;
  USE SIGNAL ;
  PORT
   LAYER M3 ;
   RECT 558.504000 544.282000 558.522000 544.320000 ;
  END
 END vo[215]
 PIN vo[216]
  DIRECTION INPUT ;
  USE SIGNAL ;
  PORT
   LAYER M5 ;
   RECT 559.536000 544.236000 559.560000 544.320000 ;
  END
 END vo[216]
 PIN vo[217]
  DIRECTION INPUT ;
  USE SIGNAL ;
  PORT
   LAYER M3 ;
   RECT 560.520000 544.282000 560.538000 544.320000 ;
  END
 END vo[217]
 PIN vo[218]
  DIRECTION INPUT ;
  USE SIGNAL ;
  PORT
   LAYER M5 ;
   RECT 561.552000 544.236000 561.576000 544.320000 ;
  END
 END vo[218]
 PIN vo[219]
  DIRECTION INPUT ;
  USE SIGNAL ;
  PORT
   LAYER M3 ;
   RECT 562.572000 544.282000 562.590000 544.320000 ;
  END
 END vo[219]
 PIN vo[220]
  DIRECTION INPUT ;
  USE SIGNAL ;
  PORT
   LAYER M5 ;
   RECT 563.568000 544.236000 563.592000 544.320000 ;
  END
 END vo[220]
 PIN vo[221]
  DIRECTION INPUT ;
  USE SIGNAL ;
  PORT
   LAYER M3 ;
   RECT 564.588000 544.282000 564.606000 544.320000 ;
  END
 END vo[221]
 PIN vo[222]
  DIRECTION INPUT ;
  USE SIGNAL ;
  PORT
   LAYER M5 ;
   RECT 565.632000 544.236000 565.656000 544.320000 ;
  END
 END vo[222]
 PIN vo[223]
  DIRECTION INPUT ;
  USE SIGNAL ;
  PORT
   LAYER M3 ;
   RECT 566.640000 544.282000 566.658000 544.320000 ;
  END
 END vo[223]
 PIN vo[224]
  DIRECTION INPUT ;
  USE SIGNAL ;
  PORT
   LAYER M5 ;
   RECT 567.648000 544.236000 567.672000 544.320000 ;
  END
 END vo[224]
 PIN vo[8]
  DIRECTION INPUT ;
  USE SIGNAL ;
  PORT
   LAYER M5 ;
   RECT 347.904000 544.236000 347.928000 544.320000 ;
  END
 END vo[8]
 PIN vo[225]
  DIRECTION INPUT ;
  USE SIGNAL ;
  PORT
   LAYER M3 ;
   RECT 568.692000 544.282000 568.710000 544.320000 ;
  END
 END vo[225]
 PIN vo[226]
  DIRECTION INPUT ;
  USE SIGNAL ;
  PORT
   LAYER M5 ;
   RECT 569.712000 544.236000 569.736000 544.320000 ;
  END
 END vo[226]
 PIN vo[227]
  DIRECTION INPUT ;
  USE SIGNAL ;
  PORT
   LAYER M3 ;
   RECT 570.708000 544.282000 570.726000 544.320000 ;
  END
 END vo[227]
 PIN vo[228]
  DIRECTION INPUT ;
  USE SIGNAL ;
  PORT
   LAYER M5 ;
   RECT 571.728000 544.236000 571.752000 544.320000 ;
  END
 END vo[228]
 PIN vo[229]
  DIRECTION INPUT ;
  USE SIGNAL ;
  PORT
   LAYER M3 ;
   RECT 572.760000 544.282000 572.778000 544.320000 ;
  END
 END vo[229]
 PIN vo[230]
  DIRECTION INPUT ;
  USE SIGNAL ;
  PORT
   LAYER M5 ;
   RECT 573.744000 544.236000 573.768000 544.320000 ;
  END
 END vo[230]
 PIN vo[231]
  DIRECTION INPUT ;
  USE SIGNAL ;
  PORT
   LAYER M3 ;
   RECT 574.776000 544.282000 574.794000 544.320000 ;
  END
 END vo[231]
 PIN vo[232]
  DIRECTION INPUT ;
  USE SIGNAL ;
  PORT
   LAYER M5 ;
   RECT 575.808000 544.236000 575.832000 544.320000 ;
  END
 END vo[232]
 PIN vo[233]
  DIRECTION INPUT ;
  USE SIGNAL ;
  PORT
   LAYER M3 ;
   RECT 576.828000 544.282000 576.846000 544.320000 ;
  END
 END vo[233]
 PIN vo[234]
  DIRECTION INPUT ;
  USE SIGNAL ;
  PORT
   LAYER M5 ;
   RECT 577.824000 544.236000 577.848000 544.320000 ;
  END
 END vo[234]
 PIN vo[9]
  DIRECTION INPUT ;
  USE SIGNAL ;
  PORT
   LAYER M3 ;
   RECT 348.912000 544.282000 348.930000 544.320000 ;
  END
 END vo[9]
 PIN vo[235]
  DIRECTION INPUT ;
  USE SIGNAL ;
  PORT
   LAYER M3 ;
   RECT 578.844000 544.282000 578.862000 544.320000 ;
  END
 END vo[235]
 PIN vo[236]
  DIRECTION INPUT ;
  USE SIGNAL ;
  PORT
   LAYER M5 ;
   RECT 579.840000 544.236000 579.864000 544.320000 ;
  END
 END vo[236]
 PIN vo[237]
  DIRECTION INPUT ;
  USE SIGNAL ;
  PORT
   LAYER M3 ;
   RECT 580.896000 544.282000 580.914000 544.320000 ;
  END
 END vo[237]
 PIN vo[238]
  DIRECTION INPUT ;
  USE SIGNAL ;
  PORT
   LAYER M5 ;
   RECT 581.904000 544.236000 581.928000 544.320000 ;
  END
 END vo[238]
 PIN vo[239]
  DIRECTION INPUT ;
  USE SIGNAL ;
  PORT
   LAYER M3 ;
   RECT 582.912000 544.282000 582.930000 544.320000 ;
  END
 END vo[239]
 PIN vo[240]
  DIRECTION INPUT ;
  USE SIGNAL ;
  PORT
   LAYER M5 ;
   RECT 583.920000 544.236000 583.944000 544.320000 ;
  END
 END vo[240]
 PIN vo[241]
  DIRECTION INPUT ;
  USE SIGNAL ;
  PORT
   LAYER M3 ;
   RECT 584.964000 544.282000 584.982000 544.320000 ;
  END
 END vo[241]
 PIN vo[242]
  DIRECTION INPUT ;
  USE SIGNAL ;
  PORT
   LAYER M5 ;
   RECT 585.984000 544.236000 586.008000 544.320000 ;
  END
 END vo[242]
 PIN vo[243]
  DIRECTION INPUT ;
  USE SIGNAL ;
  PORT
   LAYER M3 ;
   RECT 586.980000 544.282000 586.998000 544.320000 ;
  END
 END vo[243]
 PIN vo[244]
  DIRECTION INPUT ;
  USE SIGNAL ;
  PORT
   LAYER M5 ;
   RECT 588.000000 544.236000 588.024000 544.320000 ;
  END
 END vo[244]
 PIN vo[10]
  DIRECTION INPUT ;
  USE SIGNAL ;
  PORT
   LAYER M5 ;
   RECT 349.920000 544.236000 349.944000 544.320000 ;
  END
 END vo[10]
 PIN vo[245]
  DIRECTION INPUT ;
  USE SIGNAL ;
  PORT
   LAYER M3 ;
   RECT 589.032000 544.282000 589.050000 544.320000 ;
  END
 END vo[245]
 PIN vo[246]
  DIRECTION INPUT ;
  USE SIGNAL ;
  PORT
   LAYER M5 ;
   RECT 590.016000 544.236000 590.040000 544.320000 ;
  END
 END vo[246]
 PIN vo[247]
  DIRECTION INPUT ;
  USE SIGNAL ;
  PORT
   LAYER M3 ;
   RECT 591.012000 544.282000 591.030000 544.320000 ;
  END
 END vo[247]
 PIN vo[248]
  DIRECTION INPUT ;
  USE SIGNAL ;
  PORT
   LAYER M5 ;
   RECT 592.080000 544.236000 592.104000 544.320000 ;
  END
 END vo[248]
 PIN vo[249]
  DIRECTION INPUT ;
  USE SIGNAL ;
  PORT
   LAYER M3 ;
   RECT 593.100000 544.282000 593.118000 544.320000 ;
  END
 END vo[249]
 PIN vo[250]
  DIRECTION INPUT ;
  USE SIGNAL ;
  PORT
   LAYER M5 ;
   RECT 594.096000 544.236000 594.120000 544.320000 ;
  END
 END vo[250]
 PIN vo[251]
  DIRECTION INPUT ;
  USE SIGNAL ;
  PORT
   LAYER M3 ;
   RECT 595.116000 544.282000 595.134000 544.320000 ;
  END
 END vo[251]
 PIN vo[252]
  DIRECTION INPUT ;
  USE SIGNAL ;
  PORT
   LAYER M5 ;
   RECT 596.160000 544.236000 596.184000 544.320000 ;
  END
 END vo[252]
 PIN vo[253]
  DIRECTION INPUT ;
  USE SIGNAL ;
  PORT
   LAYER M3 ;
   RECT 597.168000 544.282000 597.186000 544.320000 ;
  END
 END vo[253]
 PIN vo[254]
  DIRECTION INPUT ;
  USE SIGNAL ;
  PORT
   LAYER M5 ;
   RECT 598.176000 544.236000 598.200000 544.320000 ;
  END
 END vo[254]
 PIN vo[11]
  DIRECTION INPUT ;
  USE SIGNAL ;
  PORT
   LAYER M3 ;
   RECT 350.964000 544.282000 350.982000 544.320000 ;
  END
 END vo[11]
 PIN vo[255]
  DIRECTION INPUT ;
  USE SIGNAL ;
  PORT
   LAYER M3 ;
   RECT 599.184000 544.282000 599.202000 544.320000 ;
  END
 END vo[255]
 PIN vo[256]
  DIRECTION INPUT ;
  USE SIGNAL ;
  PORT
   LAYER M5 ;
   RECT 600.192000 544.236000 600.216000 544.320000 ;
  END
 END vo[256]
 PIN vo[257]
  DIRECTION INPUT ;
  USE SIGNAL ;
  PORT
   LAYER M3 ;
   RECT 601.236000 544.282000 601.254000 544.320000 ;
  END
 END vo[257]
 PIN vo[258]
  DIRECTION INPUT ;
  USE SIGNAL ;
  PORT
   LAYER M5 ;
   RECT 602.256000 544.236000 602.280000 544.320000 ;
  END
 END vo[258]
 PIN vo[259]
  DIRECTION INPUT ;
  USE SIGNAL ;
  PORT
   LAYER M3 ;
   RECT 603.252000 544.282000 603.270000 544.320000 ;
  END
 END vo[259]
 PIN vo[260]
  DIRECTION INPUT ;
  USE SIGNAL ;
  PORT
   LAYER M5 ;
   RECT 604.272000 544.236000 604.296000 544.320000 ;
  END
 END vo[260]
 PIN vo[12]
  DIRECTION INPUT ;
  USE SIGNAL ;
  PORT
   LAYER M5 ;
   RECT 351.984000 544.236000 352.008000 544.320000 ;
  END
 END vo[12]
 PIN vo[13]
  DIRECTION INPUT ;
  USE SIGNAL ;
  PORT
   LAYER M3 ;
   RECT 352.980000 544.282000 352.998000 544.320000 ;
  END
 END vo[13]
 PIN vo[14]
  DIRECTION INPUT ;
  USE SIGNAL ;
  PORT
   LAYER M5 ;
   RECT 354.000000 544.236000 354.024000 544.320000 ;
  END
 END vo[14]
 PIN vo[2]
  DIRECTION INPUT ;
  USE SIGNAL ;
  PORT
   LAYER M3 ;
   RECT 326.520000 544.282000 326.538000 544.320000 ;
  END
 END vo[2]
 PIN vo[15]
  DIRECTION INPUT ;
  USE SIGNAL ;
  PORT
   LAYER M3 ;
   RECT 355.032000 544.282000 355.050000 544.320000 ;
  END
 END vo[15]
 PIN vo[16]
  DIRECTION INPUT ;
  USE SIGNAL ;
  PORT
   LAYER M5 ;
   RECT 356.016000 544.236000 356.040000 544.320000 ;
  END
 END vo[16]
 PIN vo[17]
  DIRECTION INPUT ;
  USE SIGNAL ;
  PORT
   LAYER M3 ;
   RECT 357.048000 544.282000 357.066000 544.320000 ;
  END
 END vo[17]
 PIN vo[18]
  DIRECTION INPUT ;
  USE SIGNAL ;
  PORT
   LAYER M5 ;
   RECT 358.080000 544.236000 358.104000 544.320000 ;
  END
 END vo[18]
 PIN vo[19]
  DIRECTION INPUT ;
  USE SIGNAL ;
  PORT
   LAYER M3 ;
   RECT 359.100000 544.282000 359.118000 544.320000 ;
  END
 END vo[19]
 PIN vo[20]
  DIRECTION INPUT ;
  USE SIGNAL ;
  PORT
   LAYER M5 ;
   RECT 360.096000 544.236000 360.120000 544.320000 ;
  END
 END vo[20]
 PIN vo[21]
  DIRECTION INPUT ;
  USE SIGNAL ;
  PORT
   LAYER M3 ;
   RECT 361.116000 544.282000 361.134000 544.320000 ;
  END
 END vo[21]
 PIN vo[22]
  DIRECTION INPUT ;
  USE SIGNAL ;
  PORT
   LAYER M5 ;
   RECT 362.160000 544.236000 362.184000 544.320000 ;
  END
 END vo[22]
 PIN vo[23]
  DIRECTION INPUT ;
  USE SIGNAL ;
  PORT
   LAYER M3 ;
   RECT 363.168000 544.282000 363.186000 544.320000 ;
  END
 END vo[23]
 PIN vo[24]
  DIRECTION INPUT ;
  USE SIGNAL ;
  PORT
   LAYER M5 ;
   RECT 364.176000 544.236000 364.200000 544.320000 ;
  END
 END vo[24]
 PIN vo[3]
  DIRECTION INPUT ;
  USE SIGNAL ;
  PORT
   LAYER M5 ;
   RECT 327.552000 544.236000 327.576000 544.320000 ;
  END
 END vo[3]
 PIN vo[25]
  DIRECTION INPUT ;
  USE SIGNAL ;
  PORT
   LAYER M3 ;
   RECT 365.184000 544.282000 365.202000 544.320000 ;
  END
 END vo[25]
 PIN vo[26]
  DIRECTION INPUT ;
  USE SIGNAL ;
  PORT
   LAYER M5 ;
   RECT 366.192000 544.236000 366.216000 544.320000 ;
  END
 END vo[26]
 PIN vo[27]
  DIRECTION INPUT ;
  USE SIGNAL ;
  PORT
   LAYER M3 ;
   RECT 367.236000 544.282000 367.254000 544.320000 ;
  END
 END vo[27]
 PIN vo[28]
  DIRECTION INPUT ;
  USE SIGNAL ;
  PORT
   LAYER M5 ;
   RECT 368.256000 544.236000 368.280000 544.320000 ;
  END
 END vo[28]
 PIN vo[29]
  DIRECTION INPUT ;
  USE SIGNAL ;
  PORT
   LAYER M3 ;
   RECT 369.252000 544.282000 369.270000 544.320000 ;
  END
 END vo[29]
 PIN vo[30]
  DIRECTION INPUT ;
  USE SIGNAL ;
  PORT
   LAYER M5 ;
   RECT 370.656000 544.236000 370.680000 544.320000 ;
  END
 END vo[30]
 PIN vo[31]
  DIRECTION INPUT ;
  USE SIGNAL ;
  PORT
   LAYER M3 ;
   RECT 371.304000 544.282000 371.322000 544.320000 ;
  END
 END vo[31]
 PIN vo[32]
  DIRECTION INPUT ;
  USE SIGNAL ;
  PORT
   LAYER M5 ;
   RECT 372.336000 544.236000 372.360000 544.320000 ;
  END
 END vo[32]
 PIN vo[33]
  DIRECTION INPUT ;
  USE SIGNAL ;
  PORT
   LAYER M3 ;
   RECT 373.320000 544.282000 373.338000 544.320000 ;
  END
 END vo[33]
 PIN vo[34]
  DIRECTION INPUT ;
  USE SIGNAL ;
  PORT
   LAYER M5 ;
   RECT 374.352000 544.236000 374.376000 544.320000 ;
  END
 END vo[34]
 PIN vo[35]
  DIRECTION INPUT ;
  USE SIGNAL ;
  PORT
   LAYER M3 ;
   RECT 375.372000 544.282000 375.390000 544.320000 ;
  END
 END vo[35]
 PIN vo[36]
  DIRECTION INPUT ;
  USE SIGNAL ;
  PORT
   LAYER M5 ;
   RECT 376.368000 544.236000 376.392000 544.320000 ;
  END
 END vo[36]
 PIN vo[37]
  DIRECTION INPUT ;
  USE SIGNAL ;
  PORT
   LAYER M3 ;
   RECT 377.388000 544.282000 377.406000 544.320000 ;
  END
 END vo[37]
 PIN vo[38]
  DIRECTION INPUT ;
  USE SIGNAL ;
  PORT
   LAYER M5 ;
   RECT 378.432000 544.236000 378.456000 544.320000 ;
  END
 END vo[38]
 PIN vo[39]
  DIRECTION INPUT ;
  USE SIGNAL ;
  PORT
   LAYER M3 ;
   RECT 379.440000 544.282000 379.458000 544.320000 ;
  END
 END vo[39]
 PIN vo[40]
  DIRECTION INPUT ;
  USE SIGNAL ;
  PORT
   LAYER M5 ;
   RECT 380.448000 544.236000 380.472000 544.320000 ;
  END
 END vo[40]
 PIN vo[41]
  DIRECTION INPUT ;
  USE SIGNAL ;
  PORT
   LAYER M3 ;
   RECT 381.492000 544.282000 381.510000 544.320000 ;
  END
 END vo[41]
 PIN vo[42]
  DIRECTION INPUT ;
  USE SIGNAL ;
  PORT
   LAYER M5 ;
   RECT 382.512000 544.236000 382.536000 544.320000 ;
  END
 END vo[42]
 PIN vo[43]
  DIRECTION INPUT ;
  USE SIGNAL ;
  PORT
   LAYER M3 ;
   RECT 383.508000 544.282000 383.526000 544.320000 ;
  END
 END vo[43]
 PIN vo[44]
  DIRECTION INPUT ;
  USE SIGNAL ;
  PORT
   LAYER M5 ;
   RECT 384.528000 544.236000 384.552000 544.320000 ;
  END
 END vo[44]
 PIN vo[45]
  DIRECTION INPUT ;
  USE SIGNAL ;
  PORT
   LAYER M3 ;
   RECT 385.560000 544.282000 385.578000 544.320000 ;
  END
 END vo[45]
 PIN vo[46]
  DIRECTION INPUT ;
  USE SIGNAL ;
  PORT
   LAYER M5 ;
   RECT 386.544000 544.236000 386.568000 544.320000 ;
  END
 END vo[46]
 PIN vo[47]
  DIRECTION INPUT ;
  USE SIGNAL ;
  PORT
   LAYER M3 ;
   RECT 387.576000 544.282000 387.594000 544.320000 ;
  END
 END vo[47]
 PIN vo[48]
  DIRECTION INPUT ;
  USE SIGNAL ;
  PORT
   LAYER M5 ;
   RECT 388.608000 544.236000 388.632000 544.320000 ;
  END
 END vo[48]
 PIN vo[49]
  DIRECTION INPUT ;
  USE SIGNAL ;
  PORT
   LAYER M3 ;
   RECT 389.628000 544.282000 389.646000 544.320000 ;
  END
 END vo[49]
 PIN vo[50]
  DIRECTION INPUT ;
  USE SIGNAL ;
  PORT
   LAYER M5 ;
   RECT 390.624000 544.236000 390.648000 544.320000 ;
  END
 END vo[50]
 PIN vo[51]
  DIRECTION INPUT ;
  USE SIGNAL ;
  PORT
   LAYER M3 ;
   RECT 391.644000 544.282000 391.662000 544.320000 ;
  END
 END vo[51]
 PIN vo[52]
  DIRECTION INPUT ;
  USE SIGNAL ;
  PORT
   LAYER M5 ;
   RECT 392.640000 544.236000 392.664000 544.320000 ;
  END
 END vo[52]
 PIN vo[53]
  DIRECTION INPUT ;
  USE SIGNAL ;
  PORT
   LAYER M3 ;
   RECT 393.696000 544.282000 393.714000 544.320000 ;
  END
 END vo[53]
 PIN vo[54]
  DIRECTION INPUT ;
  USE SIGNAL ;
  PORT
   LAYER M5 ;
   RECT 394.704000 544.236000 394.728000 544.320000 ;
  END
 END vo[54]
 PIN vo[4]
  DIRECTION INPUT ;
  USE SIGNAL ;
  PORT
   LAYER M3 ;
   RECT 330.588000 544.282000 330.606000 544.320000 ;
  END
 END vo[4]
 PIN vo[55]
  DIRECTION INPUT ;
  USE SIGNAL ;
  PORT
   LAYER M3 ;
   RECT 395.712000 544.282000 395.730000 544.320000 ;
  END
 END vo[55]
 PIN vo[56]
  DIRECTION INPUT ;
  USE SIGNAL ;
  PORT
   LAYER M5 ;
   RECT 396.720000 544.236000 396.744000 544.320000 ;
  END
 END vo[56]
 PIN vo[57]
  DIRECTION INPUT ;
  USE SIGNAL ;
  PORT
   LAYER M3 ;
   RECT 397.764000 544.282000 397.782000 544.320000 ;
  END
 END vo[57]
 PIN vo[58]
  DIRECTION INPUT ;
  USE SIGNAL ;
  PORT
   LAYER M5 ;
   RECT 398.784000 544.236000 398.808000 544.320000 ;
  END
 END vo[58]
 PIN vo[59]
  DIRECTION INPUT ;
  USE SIGNAL ;
  PORT
   LAYER M3 ;
   RECT 399.780000 544.282000 399.798000 544.320000 ;
  END
 END vo[59]
 PIN vo[60]
  DIRECTION INPUT ;
  USE SIGNAL ;
  PORT
   LAYER M5 ;
   RECT 400.800000 544.236000 400.824000 544.320000 ;
  END
 END vo[60]
 PIN vo[61]
  DIRECTION INPUT ;
  USE SIGNAL ;
  PORT
   LAYER M3 ;
   RECT 401.832000 544.282000 401.850000 544.320000 ;
  END
 END vo[61]
 PIN vo[62]
  DIRECTION INPUT ;
  USE SIGNAL ;
  PORT
   LAYER M5 ;
   RECT 402.816000 544.236000 402.840000 544.320000 ;
  END
 END vo[62]
 PIN vo[63]
  DIRECTION INPUT ;
  USE SIGNAL ;
  PORT
   LAYER M3 ;
   RECT 403.848000 544.282000 403.866000 544.320000 ;
  END
 END vo[63]
 PIN vo[64]
  DIRECTION INPUT ;
  USE SIGNAL ;
  PORT
   LAYER M5 ;
   RECT 404.880000 544.236000 404.904000 544.320000 ;
  END
 END vo[64]
 PIN vo[65]
  DIRECTION INPUT ;
  USE SIGNAL ;
  PORT
   LAYER M3 ;
   RECT 405.900000 544.282000 405.918000 544.320000 ;
  END
 END vo[65]
 PIN vo[66]
  DIRECTION INPUT ;
  USE SIGNAL ;
  PORT
   LAYER M5 ;
   RECT 406.896000 544.236000 406.920000 544.320000 ;
  END
 END vo[66]
 PIN vo[67]
  DIRECTION INPUT ;
  USE SIGNAL ;
  PORT
   LAYER M3 ;
   RECT 407.916000 544.282000 407.934000 544.320000 ;
  END
 END vo[67]
 PIN vo[68]
  DIRECTION INPUT ;
  USE SIGNAL ;
  PORT
   LAYER M5 ;
   RECT 408.960000 544.236000 408.984000 544.320000 ;
  END
 END vo[68]
 PIN vo[69]
  DIRECTION INPUT ;
  USE SIGNAL ;
  PORT
   LAYER M3 ;
   RECT 409.968000 544.282000 409.986000 544.320000 ;
  END
 END vo[69]
 PIN vo[70]
  DIRECTION INPUT ;
  USE SIGNAL ;
  PORT
   LAYER M5 ;
   RECT 410.976000 544.236000 411.000000 544.320000 ;
  END
 END vo[70]
 PIN vo[71]
  DIRECTION INPUT ;
  USE SIGNAL ;
  PORT
   LAYER M3 ;
   RECT 411.984000 544.282000 412.002000 544.320000 ;
  END
 END vo[71]
 PIN vo[72]
  DIRECTION INPUT ;
  USE SIGNAL ;
  PORT
   LAYER M5 ;
   RECT 412.992000 544.236000 413.016000 544.320000 ;
  END
 END vo[72]
 PIN vo[73]
  DIRECTION INPUT ;
  USE SIGNAL ;
  PORT
   LAYER M3 ;
   RECT 414.036000 544.282000 414.054000 544.320000 ;
  END
 END vo[73]
 PIN vo[74]
  DIRECTION INPUT ;
  USE SIGNAL ;
  PORT
   LAYER M5 ;
   RECT 415.056000 544.236000 415.080000 544.320000 ;
  END
 END vo[74]
 PIN vo[75]
  DIRECTION INPUT ;
  USE SIGNAL ;
  PORT
   LAYER M3 ;
   RECT 416.052000 544.282000 416.070000 544.320000 ;
  END
 END vo[75]
 PIN vo[76]
  DIRECTION INPUT ;
  USE SIGNAL ;
  PORT
   LAYER M5 ;
   RECT 417.072000 544.236000 417.096000 544.320000 ;
  END
 END vo[76]
 PIN vo[77]
  DIRECTION INPUT ;
  USE SIGNAL ;
  PORT
   LAYER M3 ;
   RECT 418.104000 544.282000 418.122000 544.320000 ;
  END
 END vo[77]
 PIN vo[78]
  DIRECTION INPUT ;
  USE SIGNAL ;
  PORT
   LAYER M5 ;
   RECT 419.136000 544.236000 419.160000 544.320000 ;
  END
 END vo[78]
 PIN vo[79]
  DIRECTION INPUT ;
  USE SIGNAL ;
  PORT
   LAYER M3 ;
   RECT 420.120000 544.282000 420.138000 544.320000 ;
  END
 END vo[79]
 PIN vo[80]
  DIRECTION INPUT ;
  USE SIGNAL ;
  PORT
   LAYER M5 ;
   RECT 421.152000 544.236000 421.176000 544.320000 ;
  END
 END vo[80]
 PIN vo[81]
  DIRECTION INPUT ;
  USE SIGNAL ;
  PORT
   LAYER M3 ;
   RECT 422.172000 544.282000 422.190000 544.320000 ;
  END
 END vo[81]
 PIN vo[82]
  DIRECTION INPUT ;
  USE SIGNAL ;
  PORT
   LAYER M5 ;
   RECT 423.168000 544.236000 423.192000 544.320000 ;
  END
 END vo[82]
 PIN vo[83]
  DIRECTION INPUT ;
  USE SIGNAL ;
  PORT
   LAYER M3 ;
   RECT 424.188000 544.282000 424.206000 544.320000 ;
  END
 END vo[83]
 PIN vo[84]
  DIRECTION INPUT ;
  USE SIGNAL ;
  PORT
   LAYER M5 ;
   RECT 425.232000 544.236000 425.256000 544.320000 ;
  END
 END vo[84]
 PIN VDD
  DIRECTION INOUT ;
  USE POWER ;
  PORT
   LAYER M5 ;
   RECT 6.516000 4.311000 6.636000 540.009000 ;
   RECT 10.836000 4.311000 10.956000 540.009000 ;
   RECT 15.156000 4.311000 15.276000 540.009000 ;
   RECT 19.476000 4.311000 19.596000 540.009000 ;
   RECT 23.796000 4.311000 23.916000 540.009000 ;
   RECT 28.116000 4.311000 28.236000 540.009000 ;
   RECT 32.436000 4.311000 32.556000 540.009000 ;
   RECT 36.756000 4.311000 36.876000 540.009000 ;
   RECT 41.076000 4.311000 41.196000 540.009000 ;
   RECT 45.396000 4.311000 45.516000 540.009000 ;
   RECT 49.716000 4.311000 49.836000 540.009000 ;
   RECT 54.036000 4.311000 54.156000 540.009000 ;
   RECT 58.356000 4.311000 58.476000 540.009000 ;
   RECT 62.676000 4.311000 62.796000 540.009000 ;
   RECT 66.996000 4.311000 67.116000 540.009000 ;
   RECT 71.316000 4.311000 71.436000 540.009000 ;
   RECT 75.636000 4.311000 75.756000 540.009000 ;
   RECT 79.956000 4.311000 80.076000 540.009000 ;
   RECT 84.276000 4.311000 84.396000 540.009000 ;
   RECT 88.596000 4.311000 88.716000 540.009000 ;
   RECT 92.916000 4.311000 93.036000 540.009000 ;
   RECT 97.236000 4.311000 97.356000 540.009000 ;
   RECT 101.556000 4.311000 101.676000 540.009000 ;
   RECT 105.876000 4.311000 105.996000 540.009000 ;
   RECT 110.196000 4.311000 110.316000 540.009000 ;
   RECT 114.516000 4.311000 114.636000 540.009000 ;
   RECT 118.836000 4.311000 118.956000 540.009000 ;
   RECT 123.156000 4.311000 123.276000 540.009000 ;
   RECT 127.476000 4.311000 127.596000 540.009000 ;
   RECT 131.796000 4.311000 131.916000 540.009000 ;
   RECT 136.116000 4.311000 136.236000 540.009000 ;
   RECT 140.436000 4.311000 140.556000 540.009000 ;
   RECT 144.756000 4.311000 144.876000 540.009000 ;
   RECT 149.076000 4.311000 149.196000 540.009000 ;
   RECT 153.396000 4.311000 153.516000 540.009000 ;
   RECT 157.716000 4.311000 157.836000 540.009000 ;
   RECT 162.036000 4.311000 162.156000 540.009000 ;
   RECT 166.356000 4.311000 166.476000 540.009000 ;
   RECT 170.676000 4.311000 170.796000 540.009000 ;
   RECT 174.996000 4.311000 175.116000 540.009000 ;
   RECT 179.316000 4.311000 179.436000 540.009000 ;
   RECT 183.636000 4.311000 183.756000 540.009000 ;
   RECT 187.956000 4.311000 188.076000 540.009000 ;
   RECT 192.276000 4.311000 192.396000 540.009000 ;
   RECT 196.596000 4.311000 196.716000 540.009000 ;
   RECT 200.916000 4.311000 201.036000 540.009000 ;
   RECT 205.236000 4.311000 205.356000 540.009000 ;
   RECT 209.556000 4.311000 209.676000 540.009000 ;
   RECT 213.876000 4.311000 213.996000 540.009000 ;
   RECT 218.196000 4.311000 218.316000 540.009000 ;
   RECT 222.516000 4.311000 222.636000 540.009000 ;
   RECT 226.836000 4.311000 226.956000 540.009000 ;
   RECT 231.156000 4.311000 231.276000 540.009000 ;
   RECT 235.476000 4.311000 235.596000 540.009000 ;
   RECT 239.796000 4.311000 239.916000 540.009000 ;
   RECT 244.116000 4.311000 244.236000 540.009000 ;
   RECT 248.436000 4.311000 248.556000 540.009000 ;
   RECT 252.756000 4.311000 252.876000 540.009000 ;
   RECT 257.076000 4.311000 257.196000 540.009000 ;
   RECT 261.396000 4.311000 261.516000 540.009000 ;
   RECT 265.716000 4.311000 265.836000 540.009000 ;
   RECT 270.036000 4.311000 270.156000 540.009000 ;
   RECT 274.356000 4.311000 274.476000 540.009000 ;
   RECT 278.676000 4.311000 278.796000 540.009000 ;
   RECT 282.996000 4.311000 283.116000 540.009000 ;
   RECT 287.316000 4.311000 287.436000 540.009000 ;
   RECT 291.636000 4.311000 291.756000 540.009000 ;
   RECT 295.956000 4.311000 296.076000 540.009000 ;
   RECT 300.276000 4.311000 300.396000 540.009000 ;
   RECT 304.596000 4.311000 304.716000 540.009000 ;
   RECT 308.916000 4.311000 309.036000 540.009000 ;
   RECT 313.236000 4.311000 313.356000 540.009000 ;
   RECT 317.556000 4.311000 317.676000 540.009000 ;
   RECT 321.876000 4.311000 321.996000 540.009000 ;
   RECT 326.196000 4.311000 326.316000 540.009000 ;
   RECT 330.516000 4.311000 330.636000 540.009000 ;
   RECT 334.836000 4.311000 334.956000 540.009000 ;
   RECT 339.156000 4.311000 339.276000 540.009000 ;
   RECT 343.476000 4.311000 343.596000 540.009000 ;
   RECT 347.796000 4.311000 347.916000 540.009000 ;
   RECT 352.116000 4.311000 352.236000 540.009000 ;
   RECT 356.436000 4.311000 356.556000 540.009000 ;
   RECT 360.756000 4.311000 360.876000 540.009000 ;
   RECT 365.076000 4.311000 365.196000 540.009000 ;
   RECT 369.396000 4.311000 369.516000 540.009000 ;
   RECT 373.716000 4.311000 373.836000 540.009000 ;
   RECT 378.036000 4.311000 378.156000 540.009000 ;
   RECT 382.356000 4.311000 382.476000 540.009000 ;
   RECT 386.676000 4.311000 386.796000 540.009000 ;
   RECT 390.996000 4.311000 391.116000 540.009000 ;
   RECT 395.316000 4.311000 395.436000 540.009000 ;
   RECT 399.636000 4.311000 399.756000 540.009000 ;
   RECT 403.956000 4.311000 404.076000 540.009000 ;
   RECT 408.276000 4.311000 408.396000 540.009000 ;
   RECT 412.596000 4.311000 412.716000 540.009000 ;
   RECT 416.916000 4.311000 417.036000 540.009000 ;
   RECT 421.236000 4.311000 421.356000 540.009000 ;
   RECT 425.556000 4.311000 425.676000 540.009000 ;
   RECT 429.876000 4.311000 429.996000 540.009000 ;
   RECT 434.196000 4.311000 434.316000 540.009000 ;
   RECT 438.516000 4.311000 438.636000 540.009000 ;
   RECT 442.836000 4.311000 442.956000 540.009000 ;
   RECT 447.156000 4.311000 447.276000 540.009000 ;
   RECT 451.476000 4.311000 451.596000 540.009000 ;
   RECT 455.796000 4.311000 455.916000 540.009000 ;
   RECT 460.116000 4.311000 460.236000 540.009000 ;
   RECT 464.436000 4.311000 464.556000 540.009000 ;
   RECT 468.756000 4.311000 468.876000 540.009000 ;
   RECT 473.076000 4.311000 473.196000 540.009000 ;
   RECT 477.396000 4.311000 477.516000 540.009000 ;
   RECT 481.716000 4.311000 481.836000 540.009000 ;
   RECT 486.036000 4.311000 486.156000 540.009000 ;
   RECT 490.356000 4.311000 490.476000 540.009000 ;
   RECT 494.676000 4.311000 494.796000 540.009000 ;
   RECT 498.996000 4.311000 499.116000 540.009000 ;
   RECT 503.316000 4.311000 503.436000 540.009000 ;
   RECT 507.636000 4.311000 507.756000 540.009000 ;
   RECT 511.956000 4.311000 512.076000 540.009000 ;
   RECT 516.276000 4.311000 516.396000 540.009000 ;
   RECT 520.596000 4.311000 520.716000 540.009000 ;
   RECT 524.916000 4.311000 525.036000 540.009000 ;
   RECT 529.236000 4.311000 529.356000 540.009000 ;
   RECT 533.556000 4.311000 533.676000 540.009000 ;
   RECT 537.876000 4.311000 537.996000 540.009000 ;
   RECT 542.196000 4.311000 542.316000 540.009000 ;
   RECT 546.516000 4.311000 546.636000 540.009000 ;
   RECT 550.836000 4.311000 550.956000 540.009000 ;
   RECT 555.156000 4.311000 555.276000 540.009000 ;
   RECT 559.476000 4.311000 559.596000 540.009000 ;
   RECT 563.796000 4.311000 563.916000 540.009000 ;
   RECT 568.116000 4.311000 568.236000 540.009000 ;
   RECT 572.436000 4.311000 572.556000 540.009000 ;
   RECT 576.756000 4.311000 576.876000 540.009000 ;
   RECT 581.076000 4.311000 581.196000 540.009000 ;
   RECT 585.396000 4.311000 585.516000 540.009000 ;
   RECT 589.716000 4.311000 589.836000 540.009000 ;
   RECT 594.036000 4.311000 594.156000 540.009000 ;
   RECT 598.356000 4.311000 598.476000 540.009000 ;
   RECT 602.676000 4.311000 602.796000 540.009000 ;
   RECT 606.996000 4.311000 607.116000 540.009000 ;
   RECT 611.316000 4.311000 611.436000 540.009000 ;
   RECT 615.636000 4.311000 615.756000 540.009000 ;
   RECT 619.956000 4.311000 620.076000 540.009000 ;
  END
 END VDD
 PIN VSS
  DIRECTION INOUT ;
  USE GROUND ;
  PORT
   LAYER M5 ;
   RECT 6.324000 4.297000 6.444000 540.023000 ;
   RECT 10.644000 4.297000 10.764000 540.023000 ;
   RECT 14.964000 4.297000 15.084000 540.023000 ;
   RECT 19.284000 4.297000 19.404000 540.023000 ;
   RECT 23.604000 4.297000 23.724000 540.023000 ;
   RECT 27.924000 4.297000 28.044000 540.023000 ;
   RECT 32.244000 4.297000 32.364000 540.023000 ;
   RECT 36.564000 4.297000 36.684000 540.023000 ;
   RECT 40.884000 4.297000 41.004000 540.023000 ;
   RECT 45.204000 4.297000 45.324000 540.023000 ;
   RECT 49.524000 4.297000 49.644000 540.023000 ;
   RECT 53.844000 4.297000 53.964000 540.023000 ;
   RECT 58.164000 4.297000 58.284000 540.023000 ;
   RECT 62.484000 4.297000 62.604000 540.023000 ;
   RECT 66.804000 4.297000 66.924000 540.023000 ;
   RECT 71.124000 4.297000 71.244000 540.023000 ;
   RECT 75.444000 4.297000 75.564000 540.023000 ;
   RECT 79.764000 4.297000 79.884000 540.023000 ;
   RECT 84.084000 4.297000 84.204000 540.023000 ;
   RECT 88.404000 4.297000 88.524000 540.023000 ;
   RECT 92.724000 4.297000 92.844000 540.023000 ;
   RECT 97.044000 4.297000 97.164000 540.023000 ;
   RECT 101.364000 4.297000 101.484000 540.023000 ;
   RECT 105.684000 4.297000 105.804000 540.023000 ;
   RECT 110.004000 4.297000 110.124000 540.023000 ;
   RECT 114.324000 4.297000 114.444000 540.023000 ;
   RECT 118.644000 4.297000 118.764000 540.023000 ;
   RECT 122.964000 4.297000 123.084000 540.023000 ;
   RECT 127.284000 4.297000 127.404000 540.023000 ;
   RECT 131.604000 4.297000 131.724000 540.023000 ;
   RECT 135.924000 4.297000 136.044000 540.023000 ;
   RECT 140.244000 4.297000 140.364000 540.023000 ;
   RECT 144.564000 4.297000 144.684000 540.023000 ;
   RECT 148.884000 4.297000 149.004000 540.023000 ;
   RECT 153.204000 4.297000 153.324000 540.023000 ;
   RECT 157.524000 4.297000 157.644000 540.023000 ;
   RECT 161.844000 4.297000 161.964000 540.023000 ;
   RECT 166.164000 4.297000 166.284000 540.023000 ;
   RECT 170.484000 4.297000 170.604000 540.023000 ;
   RECT 174.804000 4.297000 174.924000 540.023000 ;
   RECT 179.124000 4.297000 179.244000 540.023000 ;
   RECT 183.444000 4.297000 183.564000 540.023000 ;
   RECT 187.764000 4.297000 187.884000 540.023000 ;
   RECT 192.084000 4.297000 192.204000 540.023000 ;
   RECT 196.404000 4.297000 196.524000 540.023000 ;
   RECT 200.724000 4.297000 200.844000 540.023000 ;
   RECT 205.044000 4.297000 205.164000 540.023000 ;
   RECT 209.364000 4.297000 209.484000 540.023000 ;
   RECT 213.684000 4.297000 213.804000 540.023000 ;
   RECT 218.004000 4.297000 218.124000 540.023000 ;
   RECT 222.324000 4.297000 222.444000 540.023000 ;
   RECT 226.644000 4.297000 226.764000 540.023000 ;
   RECT 230.964000 4.297000 231.084000 540.023000 ;
   RECT 235.284000 4.297000 235.404000 540.023000 ;
   RECT 239.604000 4.297000 239.724000 540.023000 ;
   RECT 243.924000 4.297000 244.044000 540.023000 ;
   RECT 248.244000 4.297000 248.364000 540.023000 ;
   RECT 252.564000 4.297000 252.684000 540.023000 ;
   RECT 256.884000 4.297000 257.004000 540.023000 ;
   RECT 261.204000 4.297000 261.324000 540.023000 ;
   RECT 265.524000 4.297000 265.644000 540.023000 ;
   RECT 269.844000 4.297000 269.964000 540.023000 ;
   RECT 274.164000 4.297000 274.284000 540.023000 ;
   RECT 278.484000 4.297000 278.604000 540.023000 ;
   RECT 282.804000 4.297000 282.924000 540.023000 ;
   RECT 287.124000 4.297000 287.244000 540.023000 ;
   RECT 291.444000 4.297000 291.564000 540.023000 ;
   RECT 295.764000 4.297000 295.884000 540.023000 ;
   RECT 300.084000 4.297000 300.204000 540.023000 ;
   RECT 304.404000 4.297000 304.524000 540.023000 ;
   RECT 308.724000 4.297000 308.844000 540.023000 ;
   RECT 313.044000 4.297000 313.164000 540.023000 ;
   RECT 317.364000 4.297000 317.484000 540.023000 ;
   RECT 321.684000 4.297000 321.804000 540.023000 ;
   RECT 326.004000 4.297000 326.124000 540.023000 ;
   RECT 330.324000 4.297000 330.444000 540.023000 ;
   RECT 334.644000 4.297000 334.764000 540.023000 ;
   RECT 338.964000 4.297000 339.084000 540.023000 ;
   RECT 343.284000 4.297000 343.404000 540.023000 ;
   RECT 347.604000 4.297000 347.724000 540.023000 ;
   RECT 351.924000 4.297000 352.044000 540.023000 ;
   RECT 356.244000 4.297000 356.364000 540.023000 ;
   RECT 360.564000 4.297000 360.684000 540.023000 ;
   RECT 364.884000 4.297000 365.004000 540.023000 ;
   RECT 369.204000 4.297000 369.324000 540.023000 ;
   RECT 373.524000 4.297000 373.644000 540.023000 ;
   RECT 377.844000 4.297000 377.964000 540.023000 ;
   RECT 382.164000 4.297000 382.284000 540.023000 ;
   RECT 386.484000 4.297000 386.604000 540.023000 ;
   RECT 390.804000 4.297000 390.924000 540.023000 ;
   RECT 395.124000 4.297000 395.244000 540.023000 ;
   RECT 399.444000 4.297000 399.564000 540.023000 ;
   RECT 403.764000 4.297000 403.884000 540.023000 ;
   RECT 408.084000 4.297000 408.204000 540.023000 ;
   RECT 412.404000 4.297000 412.524000 540.023000 ;
   RECT 416.724000 4.297000 416.844000 540.023000 ;
   RECT 421.044000 4.297000 421.164000 540.023000 ;
   RECT 425.364000 4.297000 425.484000 540.023000 ;
   RECT 429.684000 4.297000 429.804000 540.023000 ;
   RECT 434.004000 4.297000 434.124000 540.023000 ;
   RECT 438.324000 4.297000 438.444000 540.023000 ;
   RECT 442.644000 4.297000 442.764000 540.023000 ;
   RECT 446.964000 4.297000 447.084000 540.023000 ;
   RECT 451.284000 4.297000 451.404000 540.023000 ;
   RECT 455.604000 4.297000 455.724000 540.023000 ;
   RECT 459.924000 4.297000 460.044000 540.023000 ;
   RECT 464.244000 4.297000 464.364000 540.023000 ;
   RECT 468.564000 4.297000 468.684000 540.023000 ;
   RECT 472.884000 4.297000 473.004000 540.023000 ;
   RECT 477.204000 4.297000 477.324000 540.023000 ;
   RECT 481.524000 4.297000 481.644000 540.023000 ;
   RECT 485.844000 4.297000 485.964000 540.023000 ;
   RECT 490.164000 4.297000 490.284000 540.023000 ;
   RECT 494.484000 4.297000 494.604000 540.023000 ;
   RECT 498.804000 4.297000 498.924000 540.023000 ;
   RECT 503.124000 4.297000 503.244000 540.023000 ;
   RECT 507.444000 4.297000 507.564000 540.023000 ;
   RECT 511.764000 4.297000 511.884000 540.023000 ;
   RECT 516.084000 4.297000 516.204000 540.023000 ;
   RECT 520.404000 4.297000 520.524000 540.023000 ;
   RECT 524.724000 4.297000 524.844000 540.023000 ;
   RECT 529.044000 4.297000 529.164000 540.023000 ;
   RECT 533.364000 4.297000 533.484000 540.023000 ;
   RECT 537.684000 4.297000 537.804000 540.023000 ;
   RECT 542.004000 4.297000 542.124000 540.023000 ;
   RECT 546.324000 4.297000 546.444000 540.023000 ;
   RECT 550.644000 4.297000 550.764000 540.023000 ;
   RECT 554.964000 4.297000 555.084000 540.023000 ;
   RECT 559.284000 4.297000 559.404000 540.023000 ;
   RECT 563.604000 4.297000 563.724000 540.023000 ;
   RECT 567.924000 4.297000 568.044000 540.023000 ;
   RECT 572.244000 4.297000 572.364000 540.023000 ;
   RECT 576.564000 4.297000 576.684000 540.023000 ;
   RECT 580.884000 4.297000 581.004000 540.023000 ;
   RECT 585.204000 4.297000 585.324000 540.023000 ;
   RECT 589.524000 4.297000 589.644000 540.023000 ;
   RECT 593.844000 4.297000 593.964000 540.023000 ;
   RECT 598.164000 4.297000 598.284000 540.023000 ;
   RECT 602.484000 4.297000 602.604000 540.023000 ;
   RECT 606.804000 4.297000 606.924000 540.023000 ;
   RECT 611.124000 4.297000 611.244000 540.023000 ;
   RECT 615.444000 4.297000 615.564000 540.023000 ;
   RECT 619.764000 4.297000 619.884000 540.023000 ;
  END
 END VSS
 OBS
  LAYER M1 ;
  RECT 0.5 0.5 625.9 543.82 ;
  LAYER M2 ;
  RECT 0.5 0.5 625.9 543.82 ;
  LAYER M3 ;
  RECT 0.5 0.5 625.9 543.82 ;
  LAYER M4 ;
  RECT 0.5 0.5 625.9 543.82 ;
  LAYER M5 ;
  RECT 0.5 0.5 625.9 543.82 ;
 END
END dsdv_idx_tx_n32_phys
END LIBRARY
